VERSION 5.8 ;
BUSBITCHARS "[]" ;
DIVIDERCHAR "/" ;
UNITS
    DATABASE MICRONS 1000 ;
END UNITS

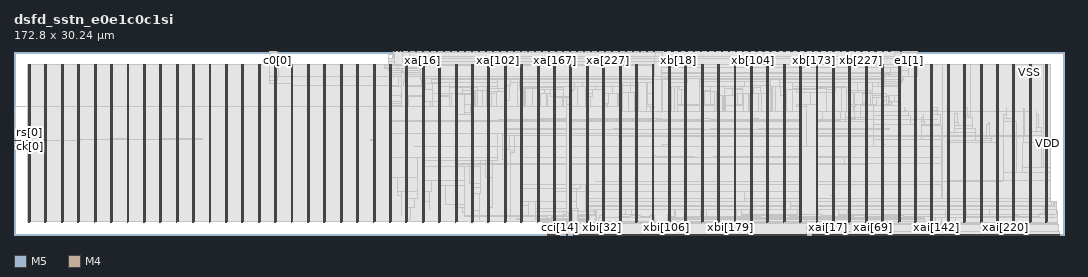
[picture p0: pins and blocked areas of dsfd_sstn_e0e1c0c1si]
MACRO dsfd_sstn_e0e1c0c1si
  FOREIGN dsfd_sstn_e0e1c0c1si 0 0 ;
  CLASS BLOCK ;
  SIZE 172.8 BY 30.24 ;
  PIN c0[0]
    DIRECTION INPUT ;
    USE SIGNAL ;
    PORT
      LAYER M5 ;
        RECT  43.296 30.156 43.32 30.24 ;
    END
  END c0[0]
  PIN c0[1]
    DIRECTION INPUT ;
    USE SIGNAL ;
    PORT
      LAYER M5 ;
        RECT  43.44 30.156 43.464 30.24 ;
    END
  END c0[1]
  PIN c1[0]
    DIRECTION INPUT ;
    USE SIGNAL ;
    PORT
      LAYER M5 ;
        RECT  148.464 30.156 148.488 30.24 ;
    END
  END c1[0]
  PIN c1[1]
    DIRECTION INPUT ;
    USE SIGNAL ;
    PORT
      LAYER M5 ;
        RECT  148.608 30.156 148.632 30.24 ;
    END
  END c1[1]
  PIN cc[0]
    DIRECTION OUTPUT ;
    USE SIGNAL ;
    PORT
      LAYER M5 ;
        RECT  62.592 30.156 62.616 30.24 ;
    END
  END cc[0]
  PIN cc[10]
    DIRECTION OUTPUT ;
    USE SIGNAL ;
    PORT
      LAYER M5 ;
        RECT  63.552 30.156 63.576 30.24 ;
    END
  END cc[10]
  PIN cc[11]
    DIRECTION OUTPUT ;
    USE SIGNAL ;
    PORT
      LAYER M5 ;
        RECT  63.648 30.156 63.672 30.24 ;
    END
  END cc[11]
  PIN cc[12]
    DIRECTION OUTPUT ;
    USE SIGNAL ;
    PORT
      LAYER M5 ;
        RECT  63.744 30.156 63.768 30.24 ;
    END
  END cc[12]
  PIN cc[13]
    DIRECTION OUTPUT ;
    USE SIGNAL ;
    PORT
      LAYER M5 ;
        RECT  63.84 30.156 63.864 30.24 ;
    END
  END cc[13]
  PIN cc[14]
    DIRECTION OUTPUT ;
    USE SIGNAL ;
    PORT
      LAYER M5 ;
        RECT  63.936 30.156 63.96 30.24 ;
    END
  END cc[14]
  PIN cc[1]
    DIRECTION OUTPUT ;
    USE SIGNAL ;
    PORT
      LAYER M5 ;
        RECT  62.688 30.156 62.712 30.24 ;
    END
  END cc[1]
  PIN cc[2]
    DIRECTION OUTPUT ;
    USE SIGNAL ;
    PORT
      LAYER M5 ;
        RECT  62.784 30.156 62.808 30.24 ;
    END
  END cc[2]
  PIN cc[3]
    DIRECTION OUTPUT ;
    USE SIGNAL ;
    PORT
      LAYER M5 ;
        RECT  62.88 30.156 62.904 30.24 ;
    END
  END cc[3]
  PIN cc[4]
    DIRECTION OUTPUT ;
    USE SIGNAL ;
    PORT
      LAYER M5 ;
        RECT  62.976 30.156 63 30.24 ;
    END
  END cc[4]
  PIN cc[5]
    DIRECTION OUTPUT ;
    USE SIGNAL ;
    PORT
      LAYER M5 ;
        RECT  63.072 30.156 63.096 30.24 ;
    END
  END cc[5]
  PIN cc[6]
    DIRECTION OUTPUT ;
    USE SIGNAL ;
    PORT
      LAYER M5 ;
        RECT  63.168 30.156 63.192 30.24 ;
    END
  END cc[6]
  PIN cc[7]
    DIRECTION OUTPUT ;
    USE SIGNAL ;
    PORT
      LAYER M5 ;
        RECT  63.264 30.156 63.288 30.24 ;
    END
  END cc[7]
  PIN cc[8]
    DIRECTION OUTPUT ;
    USE SIGNAL ;
    PORT
      LAYER M5 ;
        RECT  63.36 30.156 63.384 30.24 ;
    END
  END cc[8]
  PIN cc[9]
    DIRECTION OUTPUT ;
    USE SIGNAL ;
    PORT
      LAYER M5 ;
        RECT  63.456 30.156 63.48 30.24 ;
    END
  END cc[9]
  PIN cci[0]
    DIRECTION INPUT ;
    USE SIGNAL ;
    PORT
      LAYER M5 ;
        RECT  87.792 0 87.816 0.084 ;
    END
  END cci[0]
  PIN cci[10]
    DIRECTION INPUT ;
    USE SIGNAL ;
    PORT
      LAYER M5 ;
        RECT  89.232 0 89.256 0.084 ;
    END
  END cci[10]
  PIN cci[11]
    DIRECTION INPUT ;
    USE SIGNAL ;
    PORT
      LAYER M5 ;
        RECT  89.376 0 89.4 0.084 ;
    END
  END cci[11]
  PIN cci[12]
    DIRECTION INPUT ;
    USE SIGNAL ;
    PORT
      LAYER M5 ;
        RECT  89.52 0 89.544 0.084 ;
    END
  END cci[12]
  PIN cci[13]
    DIRECTION INPUT ;
    USE SIGNAL ;
    PORT
      LAYER M5 ;
        RECT  89.664 0 89.688 0.084 ;
    END
  END cci[13]
  PIN cci[14]
    DIRECTION INPUT ;
    USE SIGNAL ;
    PORT
      LAYER M5 ;
        RECT  89.808 0 89.832 0.084 ;
    END
  END cci[14]
  PIN cci[1]
    DIRECTION INPUT ;
    USE SIGNAL ;
    PORT
      LAYER M5 ;
        RECT  87.936 0 87.96 0.084 ;
    END
  END cci[1]
  PIN cci[2]
    DIRECTION INPUT ;
    USE SIGNAL ;
    PORT
      LAYER M5 ;
        RECT  88.08 0 88.104 0.084 ;
    END
  END cci[2]
  PIN cci[3]
    DIRECTION INPUT ;
    USE SIGNAL ;
    PORT
      LAYER M5 ;
        RECT  88.224 0 88.248 0.084 ;
    END
  END cci[3]
  PIN cci[4]
    DIRECTION INPUT ;
    USE SIGNAL ;
    PORT
      LAYER M5 ;
        RECT  88.368 0 88.392 0.084 ;
    END
  END cci[4]
  PIN cci[5]
    DIRECTION INPUT ;
    USE SIGNAL ;
    PORT
      LAYER M5 ;
        RECT  88.512 0 88.536 0.084 ;
    END
  END cci[5]
  PIN cci[6]
    DIRECTION INPUT ;
    USE SIGNAL ;
    PORT
      LAYER M5 ;
        RECT  88.656 0 88.68 0.084 ;
    END
  END cci[6]
  PIN cci[7]
    DIRECTION INPUT ;
    USE SIGNAL ;
    PORT
      LAYER M5 ;
        RECT  88.8 0 88.824 0.084 ;
    END
  END cci[7]
  PIN cci[8]
    DIRECTION INPUT ;
    USE SIGNAL ;
    PORT
      LAYER M5 ;
        RECT  88.944 0 88.968 0.084 ;
    END
  END cci[8]
  PIN cci[9]
    DIRECTION INPUT ;
    USE SIGNAL ;
    PORT
      LAYER M5 ;
        RECT  89.088 0 89.112 0.084 ;
    END
  END cci[9]
  PIN ck[0]
    DIRECTION INPUT ;
    USE SIGNAL ;
    PORT
      LAYER M4 ;
        RECT  0 14.592 0.084 14.616 ;
    END
    PORT
      LAYER M4 ;
        RECT  0.06 14.592 0.227 14.616 ;
    END
  END ck[0]
  PIN e0[0]
    DIRECTION INPUT ;
    USE SIGNAL ;
    PORT
      LAYER M5 ;
        RECT  42.048 30.156 42.072 30.24 ;
    END
  END e0[0]
  PIN e0[1]
    DIRECTION INPUT ;
    USE SIGNAL ;
    PORT
      LAYER M5 ;
        RECT  42.192 30.156 42.216 30.24 ;
    END
  END e0[1]
  PIN e1[0]
    DIRECTION INPUT ;
    USE SIGNAL ;
    PORT
      LAYER M5 ;
        RECT  147.216 30.156 147.24 30.24 ;
    END
  END e1[0]
  PIN e1[1]
    DIRECTION INPUT ;
    USE SIGNAL ;
    PORT
      LAYER M5 ;
        RECT  147.36 30.156 147.384 30.24 ;
    END
  END e1[1]
  PIN rs[0]
    DIRECTION INPUT ;
    USE SIGNAL ;
    PORT
      LAYER M4 ;
        RECT  0 15.6 0.084 15.624 ;
    END
    PORT
      LAYER M4 ;
        RECT  0.06 15.6 2.408 15.624 ;
    END
  END rs[0]
  PIN si[0]
    DIRECTION INPUT ;
    USE SIGNAL ;
    PORT
      LAYER M5 ;
        RECT  145.968 30.156 145.992 30.24 ;
    END
  END si[0]
  PIN si[1]
    DIRECTION INPUT ;
    USE SIGNAL ;
    PORT
      LAYER M5 ;
        RECT  146.112 30.156 146.136 30.24 ;
    END
  END si[1]
  PIN so[0]
    DIRECTION OUTPUT ;
    USE SIGNAL ;
    PORT
      LAYER M5 ;
        RECT  90.912 0 90.936 0.084 ;
    END
  END so[0]
  PIN so[1]
    DIRECTION OUTPUT ;
    USE SIGNAL ;
    PORT
      LAYER M5 ;
        RECT  91.056 0 91.08 0.084 ;
    END
  END so[1]
  PIN xa[0]
    DIRECTION OUTPUT ;
    USE SIGNAL ;
    PORT
      LAYER M5 ;
        RECT  64.992 30.156 65.016 30.24 ;
    END
  END xa[0]
  PIN xa[100]
    DIRECTION OUTPUT ;
    USE SIGNAL ;
    PORT
      LAYER M5 ;
        RECT  79.392 30.156 79.416 30.24 ;
    END
  END xa[100]
  PIN xa[101]
    DIRECTION OUTPUT ;
    USE SIGNAL ;
    PORT
      LAYER M5 ;
        RECT  79.536 30.156 79.56 30.24 ;
    END
  END xa[101]
  PIN xa[102]
    DIRECTION OUTPUT ;
    USE SIGNAL ;
    PORT
      LAYER M5 ;
        RECT  79.68 30.156 79.704 30.24 ;
    END
  END xa[102]
  PIN xa[103]
    DIRECTION OUTPUT ;
    USE SIGNAL ;
    PORT
      LAYER M5 ;
        RECT  79.824 30.156 79.848 30.24 ;
    END
  END xa[103]
  PIN xa[104]
    DIRECTION OUTPUT ;
    USE SIGNAL ;
    PORT
      LAYER M5 ;
        RECT  79.968 30.156 79.992 30.24 ;
    END
  END xa[104]
  PIN xa[105]
    DIRECTION OUTPUT ;
    USE SIGNAL ;
    PORT
      LAYER M5 ;
        RECT  80.112 30.156 80.136 30.24 ;
    END
  END xa[105]
  PIN xa[106]
    DIRECTION OUTPUT ;
    USE SIGNAL ;
    PORT
      LAYER M5 ;
        RECT  80.256 30.156 80.28 30.24 ;
    END
  END xa[106]
  PIN xa[107]
    DIRECTION OUTPUT ;
    USE SIGNAL ;
    PORT
      LAYER M5 ;
        RECT  80.4 30.156 80.424 30.24 ;
    END
  END xa[107]
  PIN xa[108]
    DIRECTION OUTPUT ;
    USE SIGNAL ;
    PORT
      LAYER M5 ;
        RECT  80.544 30.156 80.568 30.24 ;
    END
  END xa[108]
  PIN xa[109]
    DIRECTION OUTPUT ;
    USE SIGNAL ;
    PORT
      LAYER M5 ;
        RECT  80.688 30.156 80.712 30.24 ;
    END
  END xa[109]
  PIN xa[10]
    DIRECTION OUTPUT ;
    USE SIGNAL ;
    PORT
      LAYER M5 ;
        RECT  66.432 30.156 66.456 30.24 ;
    END
  END xa[10]
  PIN xa[110]
    DIRECTION OUTPUT ;
    USE SIGNAL ;
    PORT
      LAYER M5 ;
        RECT  80.832 30.156 80.856 30.24 ;
    END
  END xa[110]
  PIN xa[111]
    DIRECTION OUTPUT ;
    USE SIGNAL ;
    PORT
      LAYER M5 ;
        RECT  80.976 30.156 81 30.24 ;
    END
  END xa[111]
  PIN xa[112]
    DIRECTION OUTPUT ;
    USE SIGNAL ;
    PORT
      LAYER M5 ;
        RECT  81.12 30.156 81.144 30.24 ;
    END
  END xa[112]
  PIN xa[113]
    DIRECTION OUTPUT ;
    USE SIGNAL ;
    PORT
      LAYER M5 ;
        RECT  81.264 30.156 81.288 30.24 ;
    END
  END xa[113]
  PIN xa[114]
    DIRECTION OUTPUT ;
    USE SIGNAL ;
    PORT
      LAYER M5 ;
        RECT  81.408 30.156 81.432 30.24 ;
    END
  END xa[114]
  PIN xa[115]
    DIRECTION OUTPUT ;
    USE SIGNAL ;
    PORT
      LAYER M5 ;
        RECT  81.552 30.156 81.576 30.24 ;
    END
  END xa[115]
  PIN xa[116]
    DIRECTION OUTPUT ;
    USE SIGNAL ;
    PORT
      LAYER M5 ;
        RECT  81.696 30.156 81.72 30.24 ;
    END
  END xa[116]
  PIN xa[117]
    DIRECTION OUTPUT ;
    USE SIGNAL ;
    PORT
      LAYER M5 ;
        RECT  81.84 30.156 81.864 30.24 ;
    END
  END xa[117]
  PIN xa[118]
    DIRECTION OUTPUT ;
    USE SIGNAL ;
    PORT
      LAYER M5 ;
        RECT  81.984 30.156 82.008 30.24 ;
    END
  END xa[118]
  PIN xa[119]
    DIRECTION OUTPUT ;
    USE SIGNAL ;
    PORT
      LAYER M5 ;
        RECT  82.128 30.156 82.152 30.24 ;
    END
  END xa[119]
  PIN xa[11]
    DIRECTION OUTPUT ;
    USE SIGNAL ;
    PORT
      LAYER M5 ;
        RECT  66.576 30.156 66.6 30.24 ;
    END
  END xa[11]
  PIN xa[120]
    DIRECTION OUTPUT ;
    USE SIGNAL ;
    PORT
      LAYER M5 ;
        RECT  82.272 30.156 82.296 30.24 ;
    END
  END xa[120]
  PIN xa[121]
    DIRECTION OUTPUT ;
    USE SIGNAL ;
    PORT
      LAYER M5 ;
        RECT  82.416 30.156 82.44 30.24 ;
    END
  END xa[121]
  PIN xa[122]
    DIRECTION OUTPUT ;
    USE SIGNAL ;
    PORT
      LAYER M5 ;
        RECT  82.56 30.156 82.584 30.24 ;
    END
  END xa[122]
  PIN xa[123]
    DIRECTION OUTPUT ;
    USE SIGNAL ;
    PORT
      LAYER M5 ;
        RECT  82.704 30.156 82.728 30.24 ;
    END
  END xa[123]
  PIN xa[124]
    DIRECTION OUTPUT ;
    USE SIGNAL ;
    PORT
      LAYER M5 ;
        RECT  82.848 30.156 82.872 30.24 ;
    END
  END xa[124]
  PIN xa[125]
    DIRECTION OUTPUT ;
    USE SIGNAL ;
    PORT
      LAYER M5 ;
        RECT  82.992 30.156 83.016 30.24 ;
    END
  END xa[125]
  PIN xa[126]
    DIRECTION OUTPUT ;
    USE SIGNAL ;
    PORT
      LAYER M5 ;
        RECT  83.136 30.156 83.16 30.24 ;
    END
  END xa[126]
  PIN xa[127]
    DIRECTION OUTPUT ;
    USE SIGNAL ;
    PORT
      LAYER M5 ;
        RECT  83.28 30.156 83.304 30.24 ;
    END
  END xa[127]
  PIN xa[128]
    DIRECTION OUTPUT ;
    USE SIGNAL ;
    PORT
      LAYER M5 ;
        RECT  83.424 30.156 83.448 30.24 ;
    END
  END xa[128]
  PIN xa[129]
    DIRECTION OUTPUT ;
    USE SIGNAL ;
    PORT
      LAYER M5 ;
        RECT  83.568 30.156 83.592 30.24 ;
    END
  END xa[129]
  PIN xa[12]
    DIRECTION OUTPUT ;
    USE SIGNAL ;
    PORT
      LAYER M5 ;
        RECT  66.72 30.156 66.744 30.24 ;
    END
  END xa[12]
  PIN xa[130]
    DIRECTION OUTPUT ;
    USE SIGNAL ;
    PORT
      LAYER M5 ;
        RECT  83.712 30.156 83.736 30.24 ;
    END
  END xa[130]
  PIN xa[131]
    DIRECTION OUTPUT ;
    USE SIGNAL ;
    PORT
      LAYER M5 ;
        RECT  83.856 30.156 83.88 30.24 ;
    END
  END xa[131]
  PIN xa[132]
    DIRECTION OUTPUT ;
    USE SIGNAL ;
    PORT
      LAYER M5 ;
        RECT  84 30.156 84.024 30.24 ;
    END
  END xa[132]
  PIN xa[133]
    DIRECTION OUTPUT ;
    USE SIGNAL ;
    PORT
      LAYER M5 ;
        RECT  84.144 30.156 84.168 30.24 ;
    END
  END xa[133]
  PIN xa[134]
    DIRECTION OUTPUT ;
    USE SIGNAL ;
    PORT
      LAYER M5 ;
        RECT  84.288 30.156 84.312 30.24 ;
    END
  END xa[134]
  PIN xa[135]
    DIRECTION OUTPUT ;
    USE SIGNAL ;
    PORT
      LAYER M5 ;
        RECT  84.432 30.156 84.456 30.24 ;
    END
  END xa[135]
  PIN xa[136]
    DIRECTION OUTPUT ;
    USE SIGNAL ;
    PORT
      LAYER M5 ;
        RECT  84.576 30.156 84.6 30.24 ;
    END
  END xa[136]
  PIN xa[137]
    DIRECTION OUTPUT ;
    USE SIGNAL ;
    PORT
      LAYER M5 ;
        RECT  84.72 30.156 84.744 30.24 ;
    END
  END xa[137]
  PIN xa[138]
    DIRECTION OUTPUT ;
    USE SIGNAL ;
    PORT
      LAYER M5 ;
        RECT  84.864 30.156 84.888 30.24 ;
    END
  END xa[138]
  PIN xa[139]
    DIRECTION OUTPUT ;
    USE SIGNAL ;
    PORT
      LAYER M5 ;
        RECT  85.008 30.156 85.032 30.24 ;
    END
  END xa[139]
  PIN xa[13]
    DIRECTION OUTPUT ;
    USE SIGNAL ;
    PORT
      LAYER M5 ;
        RECT  66.864 30.156 66.888 30.24 ;
    END
  END xa[13]
  PIN xa[140]
    DIRECTION OUTPUT ;
    USE SIGNAL ;
    PORT
      LAYER M5 ;
        RECT  85.152 30.156 85.176 30.24 ;
    END
  END xa[140]
  PIN xa[141]
    DIRECTION OUTPUT ;
    USE SIGNAL ;
    PORT
      LAYER M5 ;
        RECT  85.296 30.156 85.32 30.24 ;
    END
  END xa[141]
  PIN xa[142]
    DIRECTION OUTPUT ;
    USE SIGNAL ;
    PORT
      LAYER M5 ;
        RECT  85.44 30.156 85.464 30.24 ;
    END
  END xa[142]
  PIN xa[143]
    DIRECTION OUTPUT ;
    USE SIGNAL ;
    PORT
      LAYER M5 ;
        RECT  85.584 30.156 85.608 30.24 ;
    END
  END xa[143]
  PIN xa[144]
    DIRECTION OUTPUT ;
    USE SIGNAL ;
    PORT
      LAYER M5 ;
        RECT  85.728 30.156 85.752 30.24 ;
    END
  END xa[144]
  PIN xa[145]
    DIRECTION OUTPUT ;
    USE SIGNAL ;
    PORT
      LAYER M5 ;
        RECT  85.872 30.156 85.896 30.24 ;
    END
  END xa[145]
  PIN xa[146]
    DIRECTION OUTPUT ;
    USE SIGNAL ;
    PORT
      LAYER M5 ;
        RECT  86.016 30.156 86.04 30.24 ;
    END
  END xa[146]
  PIN xa[147]
    DIRECTION OUTPUT ;
    USE SIGNAL ;
    PORT
      LAYER M5 ;
        RECT  86.16 30.156 86.184 30.24 ;
    END
  END xa[147]
  PIN xa[148]
    DIRECTION OUTPUT ;
    USE SIGNAL ;
    PORT
      LAYER M5 ;
        RECT  86.304 30.156 86.328 30.24 ;
    END
  END xa[148]
  PIN xa[149]
    DIRECTION OUTPUT ;
    USE SIGNAL ;
    PORT
      LAYER M5 ;
        RECT  86.448 30.156 86.472 30.24 ;
    END
  END xa[149]
  PIN xa[14]
    DIRECTION OUTPUT ;
    USE SIGNAL ;
    PORT
      LAYER M5 ;
        RECT  67.008 30.156 67.032 30.24 ;
    END
  END xa[14]
  PIN xa[150]
    DIRECTION OUTPUT ;
    USE SIGNAL ;
    PORT
      LAYER M5 ;
        RECT  86.592 30.156 86.616 30.24 ;
    END
  END xa[150]
  PIN xa[151]
    DIRECTION OUTPUT ;
    USE SIGNAL ;
    PORT
      LAYER M5 ;
        RECT  86.736 30.156 86.76 30.24 ;
    END
  END xa[151]
  PIN xa[152]
    DIRECTION OUTPUT ;
    USE SIGNAL ;
    PORT
      LAYER M5 ;
        RECT  86.88 30.156 86.904 30.24 ;
    END
  END xa[152]
  PIN xa[153]
    DIRECTION OUTPUT ;
    USE SIGNAL ;
    PORT
      LAYER M5 ;
        RECT  87.024 30.156 87.048 30.24 ;
    END
  END xa[153]
  PIN xa[154]
    DIRECTION OUTPUT ;
    USE SIGNAL ;
    PORT
      LAYER M5 ;
        RECT  87.168 30.156 87.192 30.24 ;
    END
  END xa[154]
  PIN xa[155]
    DIRECTION OUTPUT ;
    USE SIGNAL ;
    PORT
      LAYER M5 ;
        RECT  87.312 30.156 87.336 30.24 ;
    END
  END xa[155]
  PIN xa[156]
    DIRECTION OUTPUT ;
    USE SIGNAL ;
    PORT
      LAYER M5 ;
        RECT  87.456 30.156 87.48 30.24 ;
    END
  END xa[156]
  PIN xa[157]
    DIRECTION OUTPUT ;
    USE SIGNAL ;
    PORT
      LAYER M5 ;
        RECT  87.6 30.156 87.624 30.24 ;
    END
  END xa[157]
  PIN xa[158]
    DIRECTION OUTPUT ;
    USE SIGNAL ;
    PORT
      LAYER M5 ;
        RECT  87.744 30.156 87.768 30.24 ;
    END
  END xa[158]
  PIN xa[159]
    DIRECTION OUTPUT ;
    USE SIGNAL ;
    PORT
      LAYER M5 ;
        RECT  87.888 30.156 87.912 30.24 ;
    END
  END xa[159]
  PIN xa[15]
    DIRECTION OUTPUT ;
    USE SIGNAL ;
    PORT
      LAYER M5 ;
        RECT  67.152 30.156 67.176 30.24 ;
    END
  END xa[15]
  PIN xa[160]
    DIRECTION OUTPUT ;
    USE SIGNAL ;
    PORT
      LAYER M5 ;
        RECT  88.032 30.156 88.056 30.24 ;
    END
  END xa[160]
  PIN xa[161]
    DIRECTION OUTPUT ;
    USE SIGNAL ;
    PORT
      LAYER M5 ;
        RECT  88.176 30.156 88.2 30.24 ;
    END
  END xa[161]
  PIN xa[162]
    DIRECTION OUTPUT ;
    USE SIGNAL ;
    PORT
      LAYER M5 ;
        RECT  88.32 30.156 88.344 30.24 ;
    END
  END xa[162]
  PIN xa[163]
    DIRECTION OUTPUT ;
    USE SIGNAL ;
    PORT
      LAYER M5 ;
        RECT  88.464 30.156 88.488 30.24 ;
    END
  END xa[163]
  PIN xa[164]
    DIRECTION OUTPUT ;
    USE SIGNAL ;
    PORT
      LAYER M5 ;
        RECT  88.608 30.156 88.632 30.24 ;
    END
  END xa[164]
  PIN xa[165]
    DIRECTION OUTPUT ;
    USE SIGNAL ;
    PORT
      LAYER M5 ;
        RECT  88.752 30.156 88.776 30.24 ;
    END
  END xa[165]
  PIN xa[166]
    DIRECTION OUTPUT ;
    USE SIGNAL ;
    PORT
      LAYER M5 ;
        RECT  88.896 30.156 88.92 30.24 ;
    END
  END xa[166]
  PIN xa[167]
    DIRECTION OUTPUT ;
    USE SIGNAL ;
    PORT
      LAYER M5 ;
        RECT  89.04 30.156 89.064 30.24 ;
    END
  END xa[167]
  PIN xa[168]
    DIRECTION OUTPUT ;
    USE SIGNAL ;
    PORT
      LAYER M5 ;
        RECT  89.184 30.156 89.208 30.24 ;
    END
  END xa[168]
  PIN xa[169]
    DIRECTION OUTPUT ;
    USE SIGNAL ;
    PORT
      LAYER M5 ;
        RECT  89.328 30.156 89.352 30.24 ;
    END
  END xa[169]
  PIN xa[16]
    DIRECTION OUTPUT ;
    USE SIGNAL ;
    PORT
      LAYER M5 ;
        RECT  67.296 30.156 67.32 30.24 ;
    END
  END xa[16]
  PIN xa[170]
    DIRECTION OUTPUT ;
    USE SIGNAL ;
    PORT
      LAYER M5 ;
        RECT  89.472 30.156 89.496 30.24 ;
    END
  END xa[170]
  PIN xa[171]
    DIRECTION OUTPUT ;
    USE SIGNAL ;
    PORT
      LAYER M5 ;
        RECT  89.616 30.156 89.64 30.24 ;
    END
  END xa[171]
  PIN xa[172]
    DIRECTION OUTPUT ;
    USE SIGNAL ;
    PORT
      LAYER M5 ;
        RECT  89.76 30.156 89.784 30.24 ;
    END
  END xa[172]
  PIN xa[173]
    DIRECTION OUTPUT ;
    USE SIGNAL ;
    PORT
      LAYER M5 ;
        RECT  89.904 30.156 89.928 30.24 ;
    END
  END xa[173]
  PIN xa[174]
    DIRECTION OUTPUT ;
    USE SIGNAL ;
    PORT
      LAYER M5 ;
        RECT  90.048 30.156 90.072 30.24 ;
    END
  END xa[174]
  PIN xa[175]
    DIRECTION OUTPUT ;
    USE SIGNAL ;
    PORT
      LAYER M5 ;
        RECT  90.192 30.156 90.216 30.24 ;
    END
  END xa[175]
  PIN xa[176]
    DIRECTION OUTPUT ;
    USE SIGNAL ;
    PORT
      LAYER M5 ;
        RECT  90.336 30.156 90.36 30.24 ;
    END
  END xa[176]
  PIN xa[177]
    DIRECTION OUTPUT ;
    USE SIGNAL ;
    PORT
      LAYER M5 ;
        RECT  90.48 30.156 90.504 30.24 ;
    END
  END xa[177]
  PIN xa[178]
    DIRECTION OUTPUT ;
    USE SIGNAL ;
    PORT
      LAYER M5 ;
        RECT  90.624 30.156 90.648 30.24 ;
    END
  END xa[178]
  PIN xa[179]
    DIRECTION OUTPUT ;
    USE SIGNAL ;
    PORT
      LAYER M5 ;
        RECT  90.768 30.156 90.792 30.24 ;
    END
  END xa[179]
  PIN xa[17]
    DIRECTION OUTPUT ;
    USE SIGNAL ;
    PORT
      LAYER M5 ;
        RECT  67.44 30.156 67.464 30.24 ;
    END
  END xa[17]
  PIN xa[180]
    DIRECTION OUTPUT ;
    USE SIGNAL ;
    PORT
      LAYER M5 ;
        RECT  90.912 30.156 90.936 30.24 ;
    END
  END xa[180]
  PIN xa[181]
    DIRECTION OUTPUT ;
    USE SIGNAL ;
    PORT
      LAYER M5 ;
        RECT  91.056 30.156 91.08 30.24 ;
    END
  END xa[181]
  PIN xa[182]
    DIRECTION OUTPUT ;
    USE SIGNAL ;
    PORT
      LAYER M5 ;
        RECT  91.2 30.156 91.224 30.24 ;
    END
  END xa[182]
  PIN xa[183]
    DIRECTION OUTPUT ;
    USE SIGNAL ;
    PORT
      LAYER M5 ;
        RECT  91.344 30.156 91.368 30.24 ;
    END
  END xa[183]
  PIN xa[184]
    DIRECTION OUTPUT ;
    USE SIGNAL ;
    PORT
      LAYER M5 ;
        RECT  91.488 30.156 91.512 30.24 ;
    END
  END xa[184]
  PIN xa[185]
    DIRECTION OUTPUT ;
    USE SIGNAL ;
    PORT
      LAYER M5 ;
        RECT  91.632 30.156 91.656 30.24 ;
    END
  END xa[185]
  PIN xa[186]
    DIRECTION OUTPUT ;
    USE SIGNAL ;
    PORT
      LAYER M5 ;
        RECT  91.776 30.156 91.8 30.24 ;
    END
  END xa[186]
  PIN xa[187]
    DIRECTION OUTPUT ;
    USE SIGNAL ;
    PORT
      LAYER M5 ;
        RECT  91.92 30.156 91.944 30.24 ;
    END
  END xa[187]
  PIN xa[188]
    DIRECTION OUTPUT ;
    USE SIGNAL ;
    PORT
      LAYER M5 ;
        RECT  92.064 30.156 92.088 30.24 ;
    END
  END xa[188]
  PIN xa[189]
    DIRECTION OUTPUT ;
    USE SIGNAL ;
    PORT
      LAYER M5 ;
        RECT  92.208 30.156 92.232 30.24 ;
    END
  END xa[189]
  PIN xa[18]
    DIRECTION OUTPUT ;
    USE SIGNAL ;
    PORT
      LAYER M5 ;
        RECT  67.584 30.156 67.608 30.24 ;
    END
  END xa[18]
  PIN xa[190]
    DIRECTION OUTPUT ;
    USE SIGNAL ;
    PORT
      LAYER M5 ;
        RECT  92.352 30.156 92.376 30.24 ;
    END
  END xa[190]
  PIN xa[191]
    DIRECTION OUTPUT ;
    USE SIGNAL ;
    PORT
      LAYER M5 ;
        RECT  92.496 30.156 92.52 30.24 ;
    END
  END xa[191]
  PIN xa[192]
    DIRECTION OUTPUT ;
    USE SIGNAL ;
    PORT
      LAYER M5 ;
        RECT  92.64 30.156 92.664 30.24 ;
    END
  END xa[192]
  PIN xa[193]
    DIRECTION OUTPUT ;
    USE SIGNAL ;
    PORT
      LAYER M5 ;
        RECT  92.784 30.156 92.808 30.24 ;
    END
  END xa[193]
  PIN xa[194]
    DIRECTION OUTPUT ;
    USE SIGNAL ;
    PORT
      LAYER M5 ;
        RECT  92.928 30.156 92.952 30.24 ;
    END
  END xa[194]
  PIN xa[195]
    DIRECTION OUTPUT ;
    USE SIGNAL ;
    PORT
      LAYER M5 ;
        RECT  93.072 30.156 93.096 30.24 ;
    END
  END xa[195]
  PIN xa[196]
    DIRECTION OUTPUT ;
    USE SIGNAL ;
    PORT
      LAYER M5 ;
        RECT  93.216 30.156 93.24 30.24 ;
    END
  END xa[196]
  PIN xa[197]
    DIRECTION OUTPUT ;
    USE SIGNAL ;
    PORT
      LAYER M5 ;
        RECT  93.36 30.156 93.384 30.24 ;
    END
  END xa[197]
  PIN xa[198]
    DIRECTION OUTPUT ;
    USE SIGNAL ;
    PORT
      LAYER M5 ;
        RECT  93.504 30.156 93.528 30.24 ;
    END
  END xa[198]
  PIN xa[199]
    DIRECTION OUTPUT ;
    USE SIGNAL ;
    PORT
      LAYER M5 ;
        RECT  93.648 30.156 93.672 30.24 ;
    END
  END xa[199]
  PIN xa[19]
    DIRECTION OUTPUT ;
    USE SIGNAL ;
    PORT
      LAYER M5 ;
        RECT  67.728 30.156 67.752 30.24 ;
    END
  END xa[19]
  PIN xa[1]
    DIRECTION OUTPUT ;
    USE SIGNAL ;
    PORT
      LAYER M5 ;
        RECT  65.136 30.156 65.16 30.24 ;
    END
  END xa[1]
  PIN xa[200]
    DIRECTION OUTPUT ;
    USE SIGNAL ;
    PORT
      LAYER M5 ;
        RECT  93.792 30.156 93.816 30.24 ;
    END
  END xa[200]
  PIN xa[201]
    DIRECTION OUTPUT ;
    USE SIGNAL ;
    PORT
      LAYER M5 ;
        RECT  93.936 30.156 93.96 30.24 ;
    END
  END xa[201]
  PIN xa[202]
    DIRECTION OUTPUT ;
    USE SIGNAL ;
    PORT
      LAYER M5 ;
        RECT  94.08 30.156 94.104 30.24 ;
    END
  END xa[202]
  PIN xa[203]
    DIRECTION OUTPUT ;
    USE SIGNAL ;
    PORT
      LAYER M5 ;
        RECT  94.224 30.156 94.248 30.24 ;
    END
  END xa[203]
  PIN xa[204]
    DIRECTION OUTPUT ;
    USE SIGNAL ;
    PORT
      LAYER M5 ;
        RECT  94.368 30.156 94.392 30.24 ;
    END
  END xa[204]
  PIN xa[205]
    DIRECTION OUTPUT ;
    USE SIGNAL ;
    PORT
      LAYER M5 ;
        RECT  94.512 30.156 94.536 30.24 ;
    END
  END xa[205]
  PIN xa[206]
    DIRECTION OUTPUT ;
    USE SIGNAL ;
    PORT
      LAYER M5 ;
        RECT  94.656 30.156 94.68 30.24 ;
    END
  END xa[206]
  PIN xa[207]
    DIRECTION OUTPUT ;
    USE SIGNAL ;
    PORT
      LAYER M5 ;
        RECT  94.8 30.156 94.824 30.24 ;
    END
  END xa[207]
  PIN xa[208]
    DIRECTION OUTPUT ;
    USE SIGNAL ;
    PORT
      LAYER M5 ;
        RECT  94.944 30.156 94.968 30.24 ;
    END
  END xa[208]
  PIN xa[209]
    DIRECTION OUTPUT ;
    USE SIGNAL ;
    PORT
      LAYER M5 ;
        RECT  95.088 30.156 95.112 30.24 ;
    END
  END xa[209]
  PIN xa[20]
    DIRECTION OUTPUT ;
    USE SIGNAL ;
    PORT
      LAYER M5 ;
        RECT  67.872 30.156 67.896 30.24 ;
    END
  END xa[20]
  PIN xa[210]
    DIRECTION OUTPUT ;
    USE SIGNAL ;
    PORT
      LAYER M5 ;
        RECT  95.232 30.156 95.256 30.24 ;
    END
  END xa[210]
  PIN xa[211]
    DIRECTION OUTPUT ;
    USE SIGNAL ;
    PORT
      LAYER M5 ;
        RECT  95.376 30.156 95.4 30.24 ;
    END
  END xa[211]
  PIN xa[212]
    DIRECTION OUTPUT ;
    USE SIGNAL ;
    PORT
      LAYER M5 ;
        RECT  95.52 30.156 95.544 30.24 ;
    END
  END xa[212]
  PIN xa[213]
    DIRECTION OUTPUT ;
    USE SIGNAL ;
    PORT
      LAYER M5 ;
        RECT  95.664 30.156 95.688 30.24 ;
    END
  END xa[213]
  PIN xa[214]
    DIRECTION OUTPUT ;
    USE SIGNAL ;
    PORT
      LAYER M5 ;
        RECT  95.808 30.156 95.832 30.24 ;
    END
  END xa[214]
  PIN xa[215]
    DIRECTION OUTPUT ;
    USE SIGNAL ;
    PORT
      LAYER M5 ;
        RECT  95.952 30.156 95.976 30.24 ;
    END
  END xa[215]
  PIN xa[216]
    DIRECTION OUTPUT ;
    USE SIGNAL ;
    PORT
      LAYER M5 ;
        RECT  96.096 30.156 96.12 30.24 ;
    END
  END xa[216]
  PIN xa[217]
    DIRECTION OUTPUT ;
    USE SIGNAL ;
    PORT
      LAYER M5 ;
        RECT  96.24 30.156 96.264 30.24 ;
    END
  END xa[217]
  PIN xa[218]
    DIRECTION OUTPUT ;
    USE SIGNAL ;
    PORT
      LAYER M5 ;
        RECT  96.384 30.156 96.408 30.24 ;
    END
  END xa[218]
  PIN xa[219]
    DIRECTION OUTPUT ;
    USE SIGNAL ;
    PORT
      LAYER M5 ;
        RECT  96.528 30.156 96.552 30.24 ;
    END
  END xa[219]
  PIN xa[21]
    DIRECTION OUTPUT ;
    USE SIGNAL ;
    PORT
      LAYER M5 ;
        RECT  68.016 30.156 68.04 30.24 ;
    END
  END xa[21]
  PIN xa[220]
    DIRECTION OUTPUT ;
    USE SIGNAL ;
    PORT
      LAYER M5 ;
        RECT  96.672 30.156 96.696 30.24 ;
    END
  END xa[220]
  PIN xa[221]
    DIRECTION OUTPUT ;
    USE SIGNAL ;
    PORT
      LAYER M5 ;
        RECT  96.816 30.156 96.84 30.24 ;
    END
  END xa[221]
  PIN xa[222]
    DIRECTION OUTPUT ;
    USE SIGNAL ;
    PORT
      LAYER M5 ;
        RECT  96.96 30.156 96.984 30.24 ;
    END
  END xa[222]
  PIN xa[223]
    DIRECTION OUTPUT ;
    USE SIGNAL ;
    PORT
      LAYER M5 ;
        RECT  97.104 30.156 97.128 30.24 ;
    END
  END xa[223]
  PIN xa[224]
    DIRECTION OUTPUT ;
    USE SIGNAL ;
    PORT
      LAYER M5 ;
        RECT  97.248 30.156 97.272 30.24 ;
    END
  END xa[224]
  PIN xa[225]
    DIRECTION OUTPUT ;
    USE SIGNAL ;
    PORT
      LAYER M5 ;
        RECT  97.392 30.156 97.416 30.24 ;
    END
  END xa[225]
  PIN xa[226]
    DIRECTION OUTPUT ;
    USE SIGNAL ;
    PORT
      LAYER M5 ;
        RECT  97.536 30.156 97.56 30.24 ;
    END
  END xa[226]
  PIN xa[227]
    DIRECTION OUTPUT ;
    USE SIGNAL ;
    PORT
      LAYER M5 ;
        RECT  97.68 30.156 97.704 30.24 ;
    END
  END xa[227]
  PIN xa[228]
    DIRECTION OUTPUT ;
    USE SIGNAL ;
    PORT
      LAYER M5 ;
        RECT  97.824 30.156 97.848 30.24 ;
    END
  END xa[228]
  PIN xa[229]
    DIRECTION OUTPUT ;
    USE SIGNAL ;
    PORT
      LAYER M5 ;
        RECT  97.968 30.156 97.992 30.24 ;
    END
  END xa[229]
  PIN xa[22]
    DIRECTION OUTPUT ;
    USE SIGNAL ;
    PORT
      LAYER M5 ;
        RECT  68.16 30.156 68.184 30.24 ;
    END
  END xa[22]
  PIN xa[230]
    DIRECTION OUTPUT ;
    USE SIGNAL ;
    PORT
      LAYER M5 ;
        RECT  98.112 30.156 98.136 30.24 ;
    END
  END xa[230]
  PIN xa[231]
    DIRECTION OUTPUT ;
    USE SIGNAL ;
    PORT
      LAYER M5 ;
        RECT  98.256 30.156 98.28 30.24 ;
    END
  END xa[231]
  PIN xa[232]
    DIRECTION OUTPUT ;
    USE SIGNAL ;
    PORT
      LAYER M5 ;
        RECT  98.4 30.156 98.424 30.24 ;
    END
  END xa[232]
  PIN xa[233]
    DIRECTION OUTPUT ;
    USE SIGNAL ;
    PORT
      LAYER M5 ;
        RECT  98.544 30.156 98.568 30.24 ;
    END
  END xa[233]
  PIN xa[234]
    DIRECTION OUTPUT ;
    USE SIGNAL ;
    PORT
      LAYER M5 ;
        RECT  98.688 30.156 98.712 30.24 ;
    END
  END xa[234]
  PIN xa[235]
    DIRECTION OUTPUT ;
    USE SIGNAL ;
    PORT
      LAYER M5 ;
        RECT  98.832 30.156 98.856 30.24 ;
    END
  END xa[235]
  PIN xa[236]
    DIRECTION OUTPUT ;
    USE SIGNAL ;
    PORT
      LAYER M5 ;
        RECT  98.976 30.156 99 30.24 ;
    END
  END xa[236]
  PIN xa[237]
    DIRECTION OUTPUT ;
    USE SIGNAL ;
    PORT
      LAYER M5 ;
        RECT  99.12 30.156 99.144 30.24 ;
    END
  END xa[237]
  PIN xa[238]
    DIRECTION OUTPUT ;
    USE SIGNAL ;
    PORT
      LAYER M5 ;
        RECT  99.264 30.156 99.288 30.24 ;
    END
  END xa[238]
  PIN xa[239]
    DIRECTION OUTPUT ;
    USE SIGNAL ;
    PORT
      LAYER M5 ;
        RECT  99.408 30.156 99.432 30.24 ;
    END
  END xa[239]
  PIN xa[23]
    DIRECTION OUTPUT ;
    USE SIGNAL ;
    PORT
      LAYER M5 ;
        RECT  68.304 30.156 68.328 30.24 ;
    END
  END xa[23]
  PIN xa[240]
    DIRECTION OUTPUT ;
    USE SIGNAL ;
    PORT
      LAYER M5 ;
        RECT  99.552 30.156 99.576 30.24 ;
    END
  END xa[240]
  PIN xa[241]
    DIRECTION OUTPUT ;
    USE SIGNAL ;
    PORT
      LAYER M5 ;
        RECT  99.696 30.156 99.72 30.24 ;
    END
  END xa[241]
  PIN xa[242]
    DIRECTION OUTPUT ;
    USE SIGNAL ;
    PORT
      LAYER M5 ;
        RECT  99.84 30.156 99.864 30.24 ;
    END
  END xa[242]
  PIN xa[243]
    DIRECTION OUTPUT ;
    USE SIGNAL ;
    PORT
      LAYER M5 ;
        RECT  99.984 30.156 100.008 30.24 ;
    END
  END xa[243]
  PIN xa[244]
    DIRECTION OUTPUT ;
    USE SIGNAL ;
    PORT
      LAYER M5 ;
        RECT  100.128 30.156 100.152 30.24 ;
    END
  END xa[244]
  PIN xa[245]
    DIRECTION OUTPUT ;
    USE SIGNAL ;
    PORT
      LAYER M5 ;
        RECT  100.272 30.156 100.296 30.24 ;
    END
  END xa[245]
  PIN xa[246]
    DIRECTION OUTPUT ;
    USE SIGNAL ;
    PORT
      LAYER M5 ;
        RECT  100.416 30.156 100.44 30.24 ;
    END
  END xa[246]
  PIN xa[247]
    DIRECTION OUTPUT ;
    USE SIGNAL ;
    PORT
      LAYER M5 ;
        RECT  100.56 30.156 100.584 30.24 ;
    END
  END xa[247]
  PIN xa[248]
    DIRECTION OUTPUT ;
    USE SIGNAL ;
    PORT
      LAYER M5 ;
        RECT  100.704 30.156 100.728 30.24 ;
    END
  END xa[248]
  PIN xa[249]
    DIRECTION OUTPUT ;
    USE SIGNAL ;
    PORT
      LAYER M5 ;
        RECT  100.848 30.156 100.872 30.24 ;
    END
  END xa[249]
  PIN xa[24]
    DIRECTION OUTPUT ;
    USE SIGNAL ;
    PORT
      LAYER M5 ;
        RECT  68.448 30.156 68.472 30.24 ;
    END
  END xa[24]
  PIN xa[250]
    DIRECTION OUTPUT ;
    USE SIGNAL ;
    PORT
      LAYER M5 ;
        RECT  100.992 30.156 101.016 30.24 ;
    END
  END xa[250]
  PIN xa[251]
    DIRECTION OUTPUT ;
    USE SIGNAL ;
    PORT
      LAYER M5 ;
        RECT  101.136 30.156 101.16 30.24 ;
    END
  END xa[251]
  PIN xa[252]
    DIRECTION OUTPUT ;
    USE SIGNAL ;
    PORT
      LAYER M5 ;
        RECT  101.28 30.156 101.304 30.24 ;
    END
  END xa[252]
  PIN xa[253]
    DIRECTION OUTPUT ;
    USE SIGNAL ;
    PORT
      LAYER M5 ;
        RECT  101.424 30.156 101.448 30.24 ;
    END
  END xa[253]
  PIN xa[254]
    DIRECTION OUTPUT ;
    USE SIGNAL ;
    PORT
      LAYER M5 ;
        RECT  101.568 30.156 101.592 30.24 ;
    END
  END xa[254]
  PIN xa[255]
    DIRECTION OUTPUT ;
    USE SIGNAL ;
    PORT
      LAYER M5 ;
        RECT  101.712 30.156 101.736 30.24 ;
    END
  END xa[255]
  PIN xa[256]
    DIRECTION OUTPUT ;
    USE SIGNAL ;
    PORT
      LAYER M5 ;
        RECT  101.856 30.156 101.88 30.24 ;
    END
  END xa[256]
  PIN xa[257]
    DIRECTION OUTPUT ;
    USE SIGNAL ;
    PORT
      LAYER M5 ;
        RECT  102 30.156 102.024 30.24 ;
    END
  END xa[257]
  PIN xa[258]
    DIRECTION OUTPUT ;
    USE SIGNAL ;
    PORT
      LAYER M5 ;
        RECT  102.144 30.156 102.168 30.24 ;
    END
  END xa[258]
  PIN xa[259]
    DIRECTION OUTPUT ;
    USE SIGNAL ;
    PORT
      LAYER M5 ;
        RECT  102.288 30.156 102.312 30.24 ;
    END
  END xa[259]
  PIN xa[25]
    DIRECTION OUTPUT ;
    USE SIGNAL ;
    PORT
      LAYER M5 ;
        RECT  68.592 30.156 68.616 30.24 ;
    END
  END xa[25]
  PIN xa[260]
    DIRECTION OUTPUT ;
    USE SIGNAL ;
    PORT
      LAYER M5 ;
        RECT  102.432 30.156 102.456 30.24 ;
    END
  END xa[260]
  PIN xa[261]
    DIRECTION OUTPUT ;
    USE SIGNAL ;
    PORT
      LAYER M5 ;
        RECT  102.576 30.156 102.6 30.24 ;
    END
  END xa[261]
  PIN xa[262]
    DIRECTION OUTPUT ;
    USE SIGNAL ;
    PORT
      LAYER M5 ;
        RECT  102.72 30.156 102.744 30.24 ;
    END
  END xa[262]
  PIN xa[263]
    DIRECTION OUTPUT ;
    USE SIGNAL ;
    PORT
      LAYER M5 ;
        RECT  102.864 30.156 102.888 30.24 ;
    END
  END xa[263]
  PIN xa[264]
    DIRECTION OUTPUT ;
    USE SIGNAL ;
    PORT
      LAYER M5 ;
        RECT  103.008 30.156 103.032 30.24 ;
    END
  END xa[264]
  PIN xa[265]
    DIRECTION OUTPUT ;
    USE SIGNAL ;
    PORT
      LAYER M5 ;
        RECT  103.152 30.156 103.176 30.24 ;
    END
  END xa[265]
  PIN xa[266]
    DIRECTION OUTPUT ;
    USE SIGNAL ;
    PORT
      LAYER M5 ;
        RECT  103.296 30.156 103.32 30.24 ;
    END
  END xa[266]
  PIN xa[267]
    DIRECTION OUTPUT ;
    USE SIGNAL ;
    PORT
      LAYER M5 ;
        RECT  103.44 30.156 103.464 30.24 ;
    END
  END xa[267]
  PIN xa[268]
    DIRECTION OUTPUT ;
    USE SIGNAL ;
    PORT
      LAYER M5 ;
        RECT  103.584 30.156 103.608 30.24 ;
    END
  END xa[268]
  PIN xa[269]
    DIRECTION OUTPUT ;
    USE SIGNAL ;
    PORT
      LAYER M5 ;
        RECT  103.728 30.156 103.752 30.24 ;
    END
  END xa[269]
  PIN xa[26]
    DIRECTION OUTPUT ;
    USE SIGNAL ;
    PORT
      LAYER M5 ;
        RECT  68.736 30.156 68.76 30.24 ;
    END
  END xa[26]
  PIN xa[270]
    DIRECTION OUTPUT ;
    USE SIGNAL ;
    PORT
      LAYER M5 ;
        RECT  103.872 30.156 103.896 30.24 ;
    END
  END xa[270]
  PIN xa[271]
    DIRECTION OUTPUT ;
    USE SIGNAL ;
    PORT
      LAYER M5 ;
        RECT  104.016 30.156 104.04 30.24 ;
    END
  END xa[271]
  PIN xa[272]
    DIRECTION OUTPUT ;
    USE SIGNAL ;
    PORT
      LAYER M5 ;
        RECT  104.16 30.156 104.184 30.24 ;
    END
  END xa[272]
  PIN xa[273]
    DIRECTION OUTPUT ;
    USE SIGNAL ;
    PORT
      LAYER M5 ;
        RECT  104.304 30.156 104.328 30.24 ;
    END
  END xa[273]
  PIN xa[274]
    DIRECTION OUTPUT ;
    USE SIGNAL ;
    PORT
      LAYER M5 ;
        RECT  104.448 30.156 104.472 30.24 ;
    END
  END xa[274]
  PIN xa[275]
    DIRECTION OUTPUT ;
    USE SIGNAL ;
    PORT
      LAYER M5 ;
        RECT  104.592 30.156 104.616 30.24 ;
    END
  END xa[275]
  PIN xa[276]
    DIRECTION OUTPUT ;
    USE SIGNAL ;
    PORT
      LAYER M5 ;
        RECT  104.736 30.156 104.76 30.24 ;
    END
  END xa[276]
  PIN xa[277]
    DIRECTION OUTPUT ;
    USE SIGNAL ;
    PORT
      LAYER M5 ;
        RECT  104.88 30.156 104.904 30.24 ;
    END
  END xa[277]
  PIN xa[278]
    DIRECTION OUTPUT ;
    USE SIGNAL ;
    PORT
      LAYER M5 ;
        RECT  105.024 30.156 105.048 30.24 ;
    END
  END xa[278]
  PIN xa[279]
    DIRECTION OUTPUT ;
    USE SIGNAL ;
    PORT
      LAYER M5 ;
        RECT  105.168 30.156 105.192 30.24 ;
    END
  END xa[279]
  PIN xa[27]
    DIRECTION OUTPUT ;
    USE SIGNAL ;
    PORT
      LAYER M5 ;
        RECT  68.88 30.156 68.904 30.24 ;
    END
  END xa[27]
  PIN xa[280]
    DIRECTION OUTPUT ;
    USE SIGNAL ;
    PORT
      LAYER M5 ;
        RECT  105.312 30.156 105.336 30.24 ;
    END
  END xa[280]
  PIN xa[281]
    DIRECTION OUTPUT ;
    USE SIGNAL ;
    PORT
      LAYER M5 ;
        RECT  105.456 30.156 105.48 30.24 ;
    END
  END xa[281]
  PIN xa[282]
    DIRECTION OUTPUT ;
    USE SIGNAL ;
    PORT
      LAYER M5 ;
        RECT  105.6 30.156 105.624 30.24 ;
    END
  END xa[282]
  PIN xa[28]
    DIRECTION OUTPUT ;
    USE SIGNAL ;
    PORT
      LAYER M5 ;
        RECT  69.024 30.156 69.048 30.24 ;
    END
  END xa[28]
  PIN xa[29]
    DIRECTION OUTPUT ;
    USE SIGNAL ;
    PORT
      LAYER M5 ;
        RECT  69.168 30.156 69.192 30.24 ;
    END
  END xa[29]
  PIN xa[2]
    DIRECTION OUTPUT ;
    USE SIGNAL ;
    PORT
      LAYER M5 ;
        RECT  65.28 30.156 65.304 30.24 ;
    END
  END xa[2]
  PIN xa[30]
    DIRECTION OUTPUT ;
    USE SIGNAL ;
    PORT
      LAYER M5 ;
        RECT  69.312 30.156 69.336 30.24 ;
    END
  END xa[30]
  PIN xa[31]
    DIRECTION OUTPUT ;
    USE SIGNAL ;
    PORT
      LAYER M5 ;
        RECT  69.456 30.156 69.48 30.24 ;
    END
  END xa[31]
  PIN xa[32]
    DIRECTION OUTPUT ;
    USE SIGNAL ;
    PORT
      LAYER M5 ;
        RECT  69.6 30.156 69.624 30.24 ;
    END
  END xa[32]
  PIN xa[33]
    DIRECTION OUTPUT ;
    USE SIGNAL ;
    PORT
      LAYER M5 ;
        RECT  69.744 30.156 69.768 30.24 ;
    END
  END xa[33]
  PIN xa[34]
    DIRECTION OUTPUT ;
    USE SIGNAL ;
    PORT
      LAYER M5 ;
        RECT  69.888 30.156 69.912 30.24 ;
    END
  END xa[34]
  PIN xa[35]
    DIRECTION OUTPUT ;
    USE SIGNAL ;
    PORT
      LAYER M5 ;
        RECT  70.032 30.156 70.056 30.24 ;
    END
  END xa[35]
  PIN xa[36]
    DIRECTION OUTPUT ;
    USE SIGNAL ;
    PORT
      LAYER M5 ;
        RECT  70.176 30.156 70.2 30.24 ;
    END
  END xa[36]
  PIN xa[37]
    DIRECTION OUTPUT ;
    USE SIGNAL ;
    PORT
      LAYER M5 ;
        RECT  70.32 30.156 70.344 30.24 ;
    END
  END xa[37]
  PIN xa[38]
    DIRECTION OUTPUT ;
    USE SIGNAL ;
    PORT
      LAYER M5 ;
        RECT  70.464 30.156 70.488 30.24 ;
    END
  END xa[38]
  PIN xa[39]
    DIRECTION OUTPUT ;
    USE SIGNAL ;
    PORT
      LAYER M5 ;
        RECT  70.608 30.156 70.632 30.24 ;
    END
  END xa[39]
  PIN xa[3]
    DIRECTION OUTPUT ;
    USE SIGNAL ;
    PORT
      LAYER M5 ;
        RECT  65.424 30.156 65.448 30.24 ;
    END
  END xa[3]
  PIN xa[40]
    DIRECTION OUTPUT ;
    USE SIGNAL ;
    PORT
      LAYER M5 ;
        RECT  70.752 30.156 70.776 30.24 ;
    END
  END xa[40]
  PIN xa[41]
    DIRECTION OUTPUT ;
    USE SIGNAL ;
    PORT
      LAYER M5 ;
        RECT  70.896 30.156 70.92 30.24 ;
    END
  END xa[41]
  PIN xa[42]
    DIRECTION OUTPUT ;
    USE SIGNAL ;
    PORT
      LAYER M5 ;
        RECT  71.04 30.156 71.064 30.24 ;
    END
  END xa[42]
  PIN xa[43]
    DIRECTION OUTPUT ;
    USE SIGNAL ;
    PORT
      LAYER M5 ;
        RECT  71.184 30.156 71.208 30.24 ;
    END
  END xa[43]
  PIN xa[44]
    DIRECTION OUTPUT ;
    USE SIGNAL ;
    PORT
      LAYER M5 ;
        RECT  71.328 30.156 71.352 30.24 ;
    END
  END xa[44]
  PIN xa[45]
    DIRECTION OUTPUT ;
    USE SIGNAL ;
    PORT
      LAYER M5 ;
        RECT  71.472 30.156 71.496 30.24 ;
    END
  END xa[45]
  PIN xa[46]
    DIRECTION OUTPUT ;
    USE SIGNAL ;
    PORT
      LAYER M5 ;
        RECT  71.616 30.156 71.64 30.24 ;
    END
  END xa[46]
  PIN xa[47]
    DIRECTION OUTPUT ;
    USE SIGNAL ;
    PORT
      LAYER M5 ;
        RECT  71.76 30.156 71.784 30.24 ;
    END
  END xa[47]
  PIN xa[48]
    DIRECTION OUTPUT ;
    USE SIGNAL ;
    PORT
      LAYER M5 ;
        RECT  71.904 30.156 71.928 30.24 ;
    END
  END xa[48]
  PIN xa[49]
    DIRECTION OUTPUT ;
    USE SIGNAL ;
    PORT
      LAYER M5 ;
        RECT  72.048 30.156 72.072 30.24 ;
    END
  END xa[49]
  PIN xa[4]
    DIRECTION OUTPUT ;
    USE SIGNAL ;
    PORT
      LAYER M5 ;
        RECT  65.568 30.156 65.592 30.24 ;
    END
  END xa[4]
  PIN xa[50]
    DIRECTION OUTPUT ;
    USE SIGNAL ;
    PORT
      LAYER M5 ;
        RECT  72.192 30.156 72.216 30.24 ;
    END
  END xa[50]
  PIN xa[51]
    DIRECTION OUTPUT ;
    USE SIGNAL ;
    PORT
      LAYER M5 ;
        RECT  72.336 30.156 72.36 30.24 ;
    END
  END xa[51]
  PIN xa[52]
    DIRECTION OUTPUT ;
    USE SIGNAL ;
    PORT
      LAYER M5 ;
        RECT  72.48 30.156 72.504 30.24 ;
    END
  END xa[52]
  PIN xa[53]
    DIRECTION OUTPUT ;
    USE SIGNAL ;
    PORT
      LAYER M5 ;
        RECT  72.624 30.156 72.648 30.24 ;
    END
  END xa[53]
  PIN xa[54]
    DIRECTION OUTPUT ;
    USE SIGNAL ;
    PORT
      LAYER M5 ;
        RECT  72.768 30.156 72.792 30.24 ;
    END
  END xa[54]
  PIN xa[55]
    DIRECTION OUTPUT ;
    USE SIGNAL ;
    PORT
      LAYER M5 ;
        RECT  72.912 30.156 72.936 30.24 ;
    END
  END xa[55]
  PIN xa[56]
    DIRECTION OUTPUT ;
    USE SIGNAL ;
    PORT
      LAYER M5 ;
        RECT  73.056 30.156 73.08 30.24 ;
    END
  END xa[56]
  PIN xa[57]
    DIRECTION OUTPUT ;
    USE SIGNAL ;
    PORT
      LAYER M5 ;
        RECT  73.2 30.156 73.224 30.24 ;
    END
  END xa[57]
  PIN xa[58]
    DIRECTION OUTPUT ;
    USE SIGNAL ;
    PORT
      LAYER M5 ;
        RECT  73.344 30.156 73.368 30.24 ;
    END
  END xa[58]
  PIN xa[59]
    DIRECTION OUTPUT ;
    USE SIGNAL ;
    PORT
      LAYER M5 ;
        RECT  73.488 30.156 73.512 30.24 ;
    END
  END xa[59]
  PIN xa[5]
    DIRECTION OUTPUT ;
    USE SIGNAL ;
    PORT
      LAYER M5 ;
        RECT  65.712 30.156 65.736 30.24 ;
    END
  END xa[5]
  PIN xa[60]
    DIRECTION OUTPUT ;
    USE SIGNAL ;
    PORT
      LAYER M5 ;
        RECT  73.632 30.156 73.656 30.24 ;
    END
  END xa[60]
  PIN xa[61]
    DIRECTION OUTPUT ;
    USE SIGNAL ;
    PORT
      LAYER M5 ;
        RECT  73.776 30.156 73.8 30.24 ;
    END
  END xa[61]
  PIN xa[62]
    DIRECTION OUTPUT ;
    USE SIGNAL ;
    PORT
      LAYER M5 ;
        RECT  73.92 30.156 73.944 30.24 ;
    END
  END xa[62]
  PIN xa[63]
    DIRECTION OUTPUT ;
    USE SIGNAL ;
    PORT
      LAYER M5 ;
        RECT  74.064 30.156 74.088 30.24 ;
    END
  END xa[63]
  PIN xa[64]
    DIRECTION OUTPUT ;
    USE SIGNAL ;
    PORT
      LAYER M5 ;
        RECT  74.208 30.156 74.232 30.24 ;
    END
  END xa[64]
  PIN xa[65]
    DIRECTION OUTPUT ;
    USE SIGNAL ;
    PORT
      LAYER M5 ;
        RECT  74.352 30.156 74.376 30.24 ;
    END
  END xa[65]
  PIN xa[66]
    DIRECTION OUTPUT ;
    USE SIGNAL ;
    PORT
      LAYER M5 ;
        RECT  74.496 30.156 74.52 30.24 ;
    END
  END xa[66]
  PIN xa[67]
    DIRECTION OUTPUT ;
    USE SIGNAL ;
    PORT
      LAYER M5 ;
        RECT  74.64 30.156 74.664 30.24 ;
    END
  END xa[67]
  PIN xa[68]
    DIRECTION OUTPUT ;
    USE SIGNAL ;
    PORT
      LAYER M5 ;
        RECT  74.784 30.156 74.808 30.24 ;
    END
  END xa[68]
  PIN xa[69]
    DIRECTION OUTPUT ;
    USE SIGNAL ;
    PORT
      LAYER M5 ;
        RECT  74.928 30.156 74.952 30.24 ;
    END
  END xa[69]
  PIN xa[6]
    DIRECTION OUTPUT ;
    USE SIGNAL ;
    PORT
      LAYER M5 ;
        RECT  65.856 30.156 65.88 30.24 ;
    END
  END xa[6]
  PIN xa[70]
    DIRECTION OUTPUT ;
    USE SIGNAL ;
    PORT
      LAYER M5 ;
        RECT  75.072 30.156 75.096 30.24 ;
    END
  END xa[70]
  PIN xa[71]
    DIRECTION OUTPUT ;
    USE SIGNAL ;
    PORT
      LAYER M5 ;
        RECT  75.216 30.156 75.24 30.24 ;
    END
  END xa[71]
  PIN xa[72]
    DIRECTION OUTPUT ;
    USE SIGNAL ;
    PORT
      LAYER M5 ;
        RECT  75.36 30.156 75.384 30.24 ;
    END
  END xa[72]
  PIN xa[73]
    DIRECTION OUTPUT ;
    USE SIGNAL ;
    PORT
      LAYER M5 ;
        RECT  75.504 30.156 75.528 30.24 ;
    END
  END xa[73]
  PIN xa[74]
    DIRECTION OUTPUT ;
    USE SIGNAL ;
    PORT
      LAYER M5 ;
        RECT  75.648 30.156 75.672 30.24 ;
    END
  END xa[74]
  PIN xa[75]
    DIRECTION OUTPUT ;
    USE SIGNAL ;
    PORT
      LAYER M5 ;
        RECT  75.792 30.156 75.816 30.24 ;
    END
  END xa[75]
  PIN xa[76]
    DIRECTION OUTPUT ;
    USE SIGNAL ;
    PORT
      LAYER M5 ;
        RECT  75.936 30.156 75.96 30.24 ;
    END
  END xa[76]
  PIN xa[77]
    DIRECTION OUTPUT ;
    USE SIGNAL ;
    PORT
      LAYER M5 ;
        RECT  76.08 30.156 76.104 30.24 ;
    END
  END xa[77]
  PIN xa[78]
    DIRECTION OUTPUT ;
    USE SIGNAL ;
    PORT
      LAYER M5 ;
        RECT  76.224 30.156 76.248 30.24 ;
    END
  END xa[78]
  PIN xa[79]
    DIRECTION OUTPUT ;
    USE SIGNAL ;
    PORT
      LAYER M5 ;
        RECT  76.368 30.156 76.392 30.24 ;
    END
  END xa[79]
  PIN xa[7]
    DIRECTION OUTPUT ;
    USE SIGNAL ;
    PORT
      LAYER M5 ;
        RECT  66 30.156 66.024 30.24 ;
    END
  END xa[7]
  PIN xa[80]
    DIRECTION OUTPUT ;
    USE SIGNAL ;
    PORT
      LAYER M5 ;
        RECT  76.512 30.156 76.536 30.24 ;
    END
  END xa[80]
  PIN xa[81]
    DIRECTION OUTPUT ;
    USE SIGNAL ;
    PORT
      LAYER M5 ;
        RECT  76.656 30.156 76.68 30.24 ;
    END
  END xa[81]
  PIN xa[82]
    DIRECTION OUTPUT ;
    USE SIGNAL ;
    PORT
      LAYER M5 ;
        RECT  76.8 30.156 76.824 30.24 ;
    END
  END xa[82]
  PIN xa[83]
    DIRECTION OUTPUT ;
    USE SIGNAL ;
    PORT
      LAYER M5 ;
        RECT  76.944 30.156 76.968 30.24 ;
    END
  END xa[83]
  PIN xa[84]
    DIRECTION OUTPUT ;
    USE SIGNAL ;
    PORT
      LAYER M5 ;
        RECT  77.088 30.156 77.112 30.24 ;
    END
  END xa[84]
  PIN xa[85]
    DIRECTION OUTPUT ;
    USE SIGNAL ;
    PORT
      LAYER M5 ;
        RECT  77.232 30.156 77.256 30.24 ;
    END
  END xa[85]
  PIN xa[86]
    DIRECTION OUTPUT ;
    USE SIGNAL ;
    PORT
      LAYER M5 ;
        RECT  77.376 30.156 77.4 30.24 ;
    END
  END xa[86]
  PIN xa[87]
    DIRECTION OUTPUT ;
    USE SIGNAL ;
    PORT
      LAYER M5 ;
        RECT  77.52 30.156 77.544 30.24 ;
    END
  END xa[87]
  PIN xa[88]
    DIRECTION OUTPUT ;
    USE SIGNAL ;
    PORT
      LAYER M5 ;
        RECT  77.664 30.156 77.688 30.24 ;
    END
  END xa[88]
  PIN xa[89]
    DIRECTION OUTPUT ;
    USE SIGNAL ;
    PORT
      LAYER M5 ;
        RECT  77.808 30.156 77.832 30.24 ;
    END
  END xa[89]
  PIN xa[8]
    DIRECTION OUTPUT ;
    USE SIGNAL ;
    PORT
      LAYER M5 ;
        RECT  66.144 30.156 66.168 30.24 ;
    END
  END xa[8]
  PIN xa[90]
    DIRECTION OUTPUT ;
    USE SIGNAL ;
    PORT
      LAYER M5 ;
        RECT  77.952 30.156 77.976 30.24 ;
    END
  END xa[90]
  PIN xa[91]
    DIRECTION OUTPUT ;
    USE SIGNAL ;
    PORT
      LAYER M5 ;
        RECT  78.096 30.156 78.12 30.24 ;
    END
  END xa[91]
  PIN xa[92]
    DIRECTION OUTPUT ;
    USE SIGNAL ;
    PORT
      LAYER M5 ;
        RECT  78.24 30.156 78.264 30.24 ;
    END
  END xa[92]
  PIN xa[93]
    DIRECTION OUTPUT ;
    USE SIGNAL ;
    PORT
      LAYER M5 ;
        RECT  78.384 30.156 78.408 30.24 ;
    END
  END xa[93]
  PIN xa[94]
    DIRECTION OUTPUT ;
    USE SIGNAL ;
    PORT
      LAYER M5 ;
        RECT  78.528 30.156 78.552 30.24 ;
    END
  END xa[94]
  PIN xa[95]
    DIRECTION OUTPUT ;
    USE SIGNAL ;
    PORT
      LAYER M5 ;
        RECT  78.672 30.156 78.696 30.24 ;
    END
  END xa[95]
  PIN xa[96]
    DIRECTION OUTPUT ;
    USE SIGNAL ;
    PORT
      LAYER M5 ;
        RECT  78.816 30.156 78.84 30.24 ;
    END
  END xa[96]
  PIN xa[97]
    DIRECTION OUTPUT ;
    USE SIGNAL ;
    PORT
      LAYER M5 ;
        RECT  78.96 30.156 78.984 30.24 ;
    END
  END xa[97]
  PIN xa[98]
    DIRECTION OUTPUT ;
    USE SIGNAL ;
    PORT
      LAYER M5 ;
        RECT  79.104 30.156 79.128 30.24 ;
    END
  END xa[98]
  PIN xa[99]
    DIRECTION OUTPUT ;
    USE SIGNAL ;
    PORT
      LAYER M5 ;
        RECT  79.248 30.156 79.272 30.24 ;
    END
  END xa[99]
  PIN xa[9]
    DIRECTION OUTPUT ;
    USE SIGNAL ;
    PORT
      LAYER M5 ;
        RECT  66.288 30.156 66.312 30.24 ;
    END
  END xa[9]
  PIN xai[0]
    DIRECTION INPUT ;
    USE SIGNAL ;
    PORT
      LAYER M5 ;
        RECT  131.424 0 131.448 0.084 ;
    END
  END xai[0]
  PIN xai[100]
    DIRECTION INPUT ;
    USE SIGNAL ;
    PORT
      LAYER M5 ;
        RECT  145.824 0 145.848 0.084 ;
    END
  END xai[100]
  PIN xai[101]
    DIRECTION INPUT ;
    USE SIGNAL ;
    PORT
      LAYER M5 ;
        RECT  145.968 0 145.992 0.084 ;
    END
  END xai[101]
  PIN xai[102]
    DIRECTION INPUT ;
    USE SIGNAL ;
    PORT
      LAYER M5 ;
        RECT  146.112 0 146.136 0.084 ;
    END
  END xai[102]
  PIN xai[103]
    DIRECTION INPUT ;
    USE SIGNAL ;
    PORT
      LAYER M5 ;
        RECT  146.256 0 146.28 0.084 ;
    END
  END xai[103]
  PIN xai[104]
    DIRECTION INPUT ;
    USE SIGNAL ;
    PORT
      LAYER M5 ;
        RECT  146.4 0 146.424 0.084 ;
    END
  END xai[104]
  PIN xai[105]
    DIRECTION INPUT ;
    USE SIGNAL ;
    PORT
      LAYER M5 ;
        RECT  146.544 0 146.568 0.084 ;
    END
  END xai[105]
  PIN xai[106]
    DIRECTION INPUT ;
    USE SIGNAL ;
    PORT
      LAYER M5 ;
        RECT  146.688 0 146.712 0.084 ;
    END
  END xai[106]
  PIN xai[107]
    DIRECTION INPUT ;
    USE SIGNAL ;
    PORT
      LAYER M5 ;
        RECT  146.832 0 146.856 0.084 ;
    END
  END xai[107]
  PIN xai[108]
    DIRECTION INPUT ;
    USE SIGNAL ;
    PORT
      LAYER M5 ;
        RECT  146.976 0 147 0.084 ;
    END
  END xai[108]
  PIN xai[109]
    DIRECTION INPUT ;
    USE SIGNAL ;
    PORT
      LAYER M5 ;
        RECT  147.12 0 147.144 0.084 ;
    END
  END xai[109]
  PIN xai[10]
    DIRECTION INPUT ;
    USE SIGNAL ;
    PORT
      LAYER M5 ;
        RECT  132.864 0 132.888 0.084 ;
    END
  END xai[10]
  PIN xai[110]
    DIRECTION INPUT ;
    USE SIGNAL ;
    PORT
      LAYER M5 ;
        RECT  147.264 0 147.288 0.084 ;
    END
  END xai[110]
  PIN xai[111]
    DIRECTION INPUT ;
    USE SIGNAL ;
    PORT
      LAYER M5 ;
        RECT  147.408 0 147.432 0.084 ;
    END
  END xai[111]
  PIN xai[112]
    DIRECTION INPUT ;
    USE SIGNAL ;
    PORT
      LAYER M5 ;
        RECT  147.552 0 147.576 0.084 ;
    END
  END xai[112]
  PIN xai[113]
    DIRECTION INPUT ;
    USE SIGNAL ;
    PORT
      LAYER M5 ;
        RECT  147.696 0 147.72 0.084 ;
    END
  END xai[113]
  PIN xai[114]
    DIRECTION INPUT ;
    USE SIGNAL ;
    PORT
      LAYER M5 ;
        RECT  147.84 0 147.864 0.084 ;
    END
  END xai[114]
  PIN xai[115]
    DIRECTION INPUT ;
    USE SIGNAL ;
    PORT
      LAYER M5 ;
        RECT  147.984 0 148.008 0.084 ;
    END
  END xai[115]
  PIN xai[116]
    DIRECTION INPUT ;
    USE SIGNAL ;
    PORT
      LAYER M5 ;
        RECT  148.128 0 148.152 0.084 ;
    END
  END xai[116]
  PIN xai[117]
    DIRECTION INPUT ;
    USE SIGNAL ;
    PORT
      LAYER M5 ;
        RECT  148.272 0 148.296 0.084 ;
    END
  END xai[117]
  PIN xai[118]
    DIRECTION INPUT ;
    USE SIGNAL ;
    PORT
      LAYER M5 ;
        RECT  148.416 0 148.44 0.084 ;
    END
  END xai[118]
  PIN xai[119]
    DIRECTION INPUT ;
    USE SIGNAL ;
    PORT
      LAYER M5 ;
        RECT  148.56 0 148.584 0.084 ;
    END
  END xai[119]
  PIN xai[11]
    DIRECTION INPUT ;
    USE SIGNAL ;
    PORT
      LAYER M5 ;
        RECT  133.008 0 133.032 0.084 ;
    END
  END xai[11]
  PIN xai[120]
    DIRECTION INPUT ;
    USE SIGNAL ;
    PORT
      LAYER M5 ;
        RECT  148.704 0 148.728 0.084 ;
    END
  END xai[120]
  PIN xai[121]
    DIRECTION INPUT ;
    USE SIGNAL ;
    PORT
      LAYER M5 ;
        RECT  148.848 0 148.872 0.084 ;
    END
  END xai[121]
  PIN xai[122]
    DIRECTION INPUT ;
    USE SIGNAL ;
    PORT
      LAYER M5 ;
        RECT  148.992 0 149.016 0.084 ;
    END
  END xai[122]
  PIN xai[123]
    DIRECTION INPUT ;
    USE SIGNAL ;
    PORT
      LAYER M5 ;
        RECT  149.136 0 149.16 0.084 ;
    END
  END xai[123]
  PIN xai[124]
    DIRECTION INPUT ;
    USE SIGNAL ;
    PORT
      LAYER M5 ;
        RECT  149.28 0 149.304 0.084 ;
    END
  END xai[124]
  PIN xai[125]
    DIRECTION INPUT ;
    USE SIGNAL ;
    PORT
      LAYER M5 ;
        RECT  149.424 0 149.448 0.084 ;
    END
  END xai[125]
  PIN xai[126]
    DIRECTION INPUT ;
    USE SIGNAL ;
    PORT
      LAYER M5 ;
        RECT  149.568 0 149.592 0.084 ;
    END
  END xai[126]
  PIN xai[127]
    DIRECTION INPUT ;
    USE SIGNAL ;
    PORT
      LAYER M5 ;
        RECT  149.712 0 149.736 0.084 ;
    END
  END xai[127]
  PIN xai[128]
    DIRECTION INPUT ;
    USE SIGNAL ;
    PORT
      LAYER M5 ;
        RECT  149.856 0 149.88 0.084 ;
    END
  END xai[128]
  PIN xai[129]
    DIRECTION INPUT ;
    USE SIGNAL ;
    PORT
      LAYER M5 ;
        RECT  150 0 150.024 0.084 ;
    END
  END xai[129]
  PIN xai[12]
    DIRECTION INPUT ;
    USE SIGNAL ;
    PORT
      LAYER M5 ;
        RECT  133.152 0 133.176 0.084 ;
    END
  END xai[12]
  PIN xai[130]
    DIRECTION INPUT ;
    USE SIGNAL ;
    PORT
      LAYER M5 ;
        RECT  150.144 0 150.168 0.084 ;
    END
  END xai[130]
  PIN xai[131]
    DIRECTION INPUT ;
    USE SIGNAL ;
    PORT
      LAYER M5 ;
        RECT  150.288 0 150.312 0.084 ;
    END
  END xai[131]
  PIN xai[132]
    DIRECTION INPUT ;
    USE SIGNAL ;
    PORT
      LAYER M5 ;
        RECT  150.432 0 150.456 0.084 ;
    END
  END xai[132]
  PIN xai[133]
    DIRECTION INPUT ;
    USE SIGNAL ;
    PORT
      LAYER M5 ;
        RECT  150.576 0 150.6 0.084 ;
    END
  END xai[133]
  PIN xai[134]
    DIRECTION INPUT ;
    USE SIGNAL ;
    PORT
      LAYER M5 ;
        RECT  150.72 0 150.744 0.084 ;
    END
  END xai[134]
  PIN xai[135]
    DIRECTION INPUT ;
    USE SIGNAL ;
    PORT
      LAYER M5 ;
        RECT  150.864 0 150.888 0.084 ;
    END
  END xai[135]
  PIN xai[136]
    DIRECTION INPUT ;
    USE SIGNAL ;
    PORT
      LAYER M5 ;
        RECT  151.008 0 151.032 0.084 ;
    END
  END xai[136]
  PIN xai[137]
    DIRECTION INPUT ;
    USE SIGNAL ;
    PORT
      LAYER M5 ;
        RECT  151.152 0 151.176 0.084 ;
    END
  END xai[137]
  PIN xai[138]
    DIRECTION INPUT ;
    USE SIGNAL ;
    PORT
      LAYER M5 ;
        RECT  151.296 0 151.32 0.084 ;
    END
  END xai[138]
  PIN xai[139]
    DIRECTION INPUT ;
    USE SIGNAL ;
    PORT
      LAYER M5 ;
        RECT  151.44 0 151.464 0.084 ;
    END
  END xai[139]
  PIN xai[13]
    DIRECTION INPUT ;
    USE SIGNAL ;
    PORT
      LAYER M5 ;
        RECT  133.296 0 133.32 0.084 ;
    END
  END xai[13]
  PIN xai[140]
    DIRECTION INPUT ;
    USE SIGNAL ;
    PORT
      LAYER M5 ;
        RECT  151.584 0 151.608 0.084 ;
    END
  END xai[140]
  PIN xai[141]
    DIRECTION INPUT ;
    USE SIGNAL ;
    PORT
      LAYER M5 ;
        RECT  151.728 0 151.752 0.084 ;
    END
  END xai[141]
  PIN xai[142]
    DIRECTION INPUT ;
    USE SIGNAL ;
    PORT
      LAYER M5 ;
        RECT  151.872 0 151.896 0.084 ;
    END
  END xai[142]
  PIN xai[143]
    DIRECTION INPUT ;
    USE SIGNAL ;
    PORT
      LAYER M5 ;
        RECT  152.016 0 152.04 0.084 ;
    END
  END xai[143]
  PIN xai[144]
    DIRECTION INPUT ;
    USE SIGNAL ;
    PORT
      LAYER M5 ;
        RECT  152.16 0 152.184 0.084 ;
    END
  END xai[144]
  PIN xai[145]
    DIRECTION INPUT ;
    USE SIGNAL ;
    PORT
      LAYER M5 ;
        RECT  152.304 0 152.328 0.084 ;
    END
  END xai[145]
  PIN xai[146]
    DIRECTION INPUT ;
    USE SIGNAL ;
    PORT
      LAYER M5 ;
        RECT  152.448 0 152.472 0.084 ;
    END
  END xai[146]
  PIN xai[147]
    DIRECTION INPUT ;
    USE SIGNAL ;
    PORT
      LAYER M5 ;
        RECT  152.592 0 152.616 0.084 ;
    END
  END xai[147]
  PIN xai[148]
    DIRECTION INPUT ;
    USE SIGNAL ;
    PORT
      LAYER M5 ;
        RECT  152.736 0 152.76 0.084 ;
    END
  END xai[148]
  PIN xai[149]
    DIRECTION INPUT ;
    USE SIGNAL ;
    PORT
      LAYER M5 ;
        RECT  152.88 0 152.904 0.084 ;
    END
  END xai[149]
  PIN xai[14]
    DIRECTION INPUT ;
    USE SIGNAL ;
    PORT
      LAYER M5 ;
        RECT  133.44 0 133.464 0.084 ;
    END
  END xai[14]
  PIN xai[150]
    DIRECTION INPUT ;
    USE SIGNAL ;
    PORT
      LAYER M5 ;
        RECT  153.024 0 153.048 0.084 ;
    END
  END xai[150]
  PIN xai[151]
    DIRECTION INPUT ;
    USE SIGNAL ;
    PORT
      LAYER M5 ;
        RECT  153.168 0 153.192 0.084 ;
    END
  END xai[151]
  PIN xai[152]
    DIRECTION INPUT ;
    USE SIGNAL ;
    PORT
      LAYER M5 ;
        RECT  153.312 0 153.336 0.084 ;
    END
  END xai[152]
  PIN xai[153]
    DIRECTION INPUT ;
    USE SIGNAL ;
    PORT
      LAYER M5 ;
        RECT  153.456 0 153.48 0.084 ;
    END
  END xai[153]
  PIN xai[154]
    DIRECTION INPUT ;
    USE SIGNAL ;
    PORT
      LAYER M5 ;
        RECT  153.6 0 153.624 0.084 ;
    END
  END xai[154]
  PIN xai[155]
    DIRECTION INPUT ;
    USE SIGNAL ;
    PORT
      LAYER M5 ;
        RECT  153.744 0 153.768 0.084 ;
    END
  END xai[155]
  PIN xai[156]
    DIRECTION INPUT ;
    USE SIGNAL ;
    PORT
      LAYER M5 ;
        RECT  153.888 0 153.912 0.084 ;
    END
  END xai[156]
  PIN xai[157]
    DIRECTION INPUT ;
    USE SIGNAL ;
    PORT
      LAYER M5 ;
        RECT  154.032 0 154.056 0.084 ;
    END
  END xai[157]
  PIN xai[158]
    DIRECTION INPUT ;
    USE SIGNAL ;
    PORT
      LAYER M5 ;
        RECT  154.176 0 154.2 0.084 ;
    END
  END xai[158]
  PIN xai[159]
    DIRECTION INPUT ;
    USE SIGNAL ;
    PORT
      LAYER M5 ;
        RECT  154.32 0 154.344 0.084 ;
    END
  END xai[159]
  PIN xai[15]
    DIRECTION INPUT ;
    USE SIGNAL ;
    PORT
      LAYER M5 ;
        RECT  133.584 0 133.608 0.084 ;
    END
  END xai[15]
  PIN xai[160]
    DIRECTION INPUT ;
    USE SIGNAL ;
    PORT
      LAYER M5 ;
        RECT  154.464 0 154.488 0.084 ;
    END
  END xai[160]
  PIN xai[161]
    DIRECTION INPUT ;
    USE SIGNAL ;
    PORT
      LAYER M5 ;
        RECT  154.608 0 154.632 0.084 ;
    END
  END xai[161]
  PIN xai[162]
    DIRECTION INPUT ;
    USE SIGNAL ;
    PORT
      LAYER M5 ;
        RECT  154.752 0 154.776 0.084 ;
    END
  END xai[162]
  PIN xai[163]
    DIRECTION INPUT ;
    USE SIGNAL ;
    PORT
      LAYER M5 ;
        RECT  154.896 0 154.92 0.084 ;
    END
  END xai[163]
  PIN xai[164]
    DIRECTION INPUT ;
    USE SIGNAL ;
    PORT
      LAYER M5 ;
        RECT  155.04 0 155.064 0.084 ;
    END
  END xai[164]
  PIN xai[165]
    DIRECTION INPUT ;
    USE SIGNAL ;
    PORT
      LAYER M5 ;
        RECT  155.184 0 155.208 0.084 ;
    END
  END xai[165]
  PIN xai[166]
    DIRECTION INPUT ;
    USE SIGNAL ;
    PORT
      LAYER M5 ;
        RECT  155.328 0 155.352 0.084 ;
    END
  END xai[166]
  PIN xai[167]
    DIRECTION INPUT ;
    USE SIGNAL ;
    PORT
      LAYER M5 ;
        RECT  155.472 0 155.496 0.084 ;
    END
  END xai[167]
  PIN xai[168]
    DIRECTION INPUT ;
    USE SIGNAL ;
    PORT
      LAYER M5 ;
        RECT  155.616 0 155.64 0.084 ;
    END
  END xai[168]
  PIN xai[169]
    DIRECTION INPUT ;
    USE SIGNAL ;
    PORT
      LAYER M5 ;
        RECT  155.76 0 155.784 0.084 ;
    END
  END xai[169]
  PIN xai[16]
    DIRECTION INPUT ;
    USE SIGNAL ;
    PORT
      LAYER M5 ;
        RECT  133.728 0 133.752 0.084 ;
    END
  END xai[16]
  PIN xai[170]
    DIRECTION INPUT ;
    USE SIGNAL ;
    PORT
      LAYER M5 ;
        RECT  155.904 0 155.928 0.084 ;
    END
  END xai[170]
  PIN xai[171]
    DIRECTION INPUT ;
    USE SIGNAL ;
    PORT
      LAYER M5 ;
        RECT  156.048 0 156.072 0.084 ;
    END
  END xai[171]
  PIN xai[172]
    DIRECTION INPUT ;
    USE SIGNAL ;
    PORT
      LAYER M5 ;
        RECT  156.192 0 156.216 0.084 ;
    END
  END xai[172]
  PIN xai[173]
    DIRECTION INPUT ;
    USE SIGNAL ;
    PORT
      LAYER M5 ;
        RECT  156.336 0 156.36 0.084 ;
    END
  END xai[173]
  PIN xai[174]
    DIRECTION INPUT ;
    USE SIGNAL ;
    PORT
      LAYER M5 ;
        RECT  156.48 0 156.504 0.084 ;
    END
  END xai[174]
  PIN xai[175]
    DIRECTION INPUT ;
    USE SIGNAL ;
    PORT
      LAYER M5 ;
        RECT  156.624 0 156.648 0.084 ;
    END
  END xai[175]
  PIN xai[176]
    DIRECTION INPUT ;
    USE SIGNAL ;
    PORT
      LAYER M5 ;
        RECT  156.768 0 156.792 0.084 ;
    END
  END xai[176]
  PIN xai[177]
    DIRECTION INPUT ;
    USE SIGNAL ;
    PORT
      LAYER M5 ;
        RECT  156.912 0 156.936 0.084 ;
    END
  END xai[177]
  PIN xai[178]
    DIRECTION INPUT ;
    USE SIGNAL ;
    PORT
      LAYER M5 ;
        RECT  157.056 0 157.08 0.084 ;
    END
  END xai[178]
  PIN xai[179]
    DIRECTION INPUT ;
    USE SIGNAL ;
    PORT
      LAYER M5 ;
        RECT  157.2 0 157.224 0.084 ;
    END
  END xai[179]
  PIN xai[17]
    DIRECTION INPUT ;
    USE SIGNAL ;
    PORT
      LAYER M5 ;
        RECT  133.872 0 133.896 0.084 ;
    END
  END xai[17]
  PIN xai[180]
    DIRECTION INPUT ;
    USE SIGNAL ;
    PORT
      LAYER M5 ;
        RECT  157.344 0 157.368 0.084 ;
    END
  END xai[180]
  PIN xai[181]
    DIRECTION INPUT ;
    USE SIGNAL ;
    PORT
      LAYER M5 ;
        RECT  157.488 0 157.512 0.084 ;
    END
  END xai[181]
  PIN xai[182]
    DIRECTION INPUT ;
    USE SIGNAL ;
    PORT
      LAYER M5 ;
        RECT  157.632 0 157.656 0.084 ;
    END
  END xai[182]
  PIN xai[183]
    DIRECTION INPUT ;
    USE SIGNAL ;
    PORT
      LAYER M5 ;
        RECT  157.776 0 157.8 0.084 ;
    END
  END xai[183]
  PIN xai[184]
    DIRECTION INPUT ;
    USE SIGNAL ;
    PORT
      LAYER M5 ;
        RECT  157.92 0 157.944 0.084 ;
    END
  END xai[184]
  PIN xai[185]
    DIRECTION INPUT ;
    USE SIGNAL ;
    PORT
      LAYER M5 ;
        RECT  158.064 0 158.088 0.084 ;
    END
  END xai[185]
  PIN xai[186]
    DIRECTION INPUT ;
    USE SIGNAL ;
    PORT
      LAYER M5 ;
        RECT  158.208 0 158.232 0.084 ;
    END
  END xai[186]
  PIN xai[187]
    DIRECTION INPUT ;
    USE SIGNAL ;
    PORT
      LAYER M5 ;
        RECT  158.352 0 158.376 0.084 ;
    END
  END xai[187]
  PIN xai[188]
    DIRECTION INPUT ;
    USE SIGNAL ;
    PORT
      LAYER M5 ;
        RECT  158.496 0 158.52 0.084 ;
    END
  END xai[188]
  PIN xai[189]
    DIRECTION INPUT ;
    USE SIGNAL ;
    PORT
      LAYER M5 ;
        RECT  158.64 0 158.664 0.084 ;
    END
  END xai[189]
  PIN xai[18]
    DIRECTION INPUT ;
    USE SIGNAL ;
    PORT
      LAYER M5 ;
        RECT  134.016 0 134.04 0.084 ;
    END
  END xai[18]
  PIN xai[190]
    DIRECTION INPUT ;
    USE SIGNAL ;
    PORT
      LAYER M5 ;
        RECT  158.784 0 158.808 0.084 ;
    END
  END xai[190]
  PIN xai[191]
    DIRECTION INPUT ;
    USE SIGNAL ;
    PORT
      LAYER M5 ;
        RECT  158.928 0 158.952 0.084 ;
    END
  END xai[191]
  PIN xai[192]
    DIRECTION INPUT ;
    USE SIGNAL ;
    PORT
      LAYER M5 ;
        RECT  159.072 0 159.096 0.084 ;
    END
  END xai[192]
  PIN xai[193]
    DIRECTION INPUT ;
    USE SIGNAL ;
    PORT
      LAYER M5 ;
        RECT  159.216 0 159.24 0.084 ;
    END
  END xai[193]
  PIN xai[194]
    DIRECTION INPUT ;
    USE SIGNAL ;
    PORT
      LAYER M5 ;
        RECT  159.36 0 159.384 0.084 ;
    END
  END xai[194]
  PIN xai[195]
    DIRECTION INPUT ;
    USE SIGNAL ;
    PORT
      LAYER M5 ;
        RECT  159.504 0 159.528 0.084 ;
    END
  END xai[195]
  PIN xai[196]
    DIRECTION INPUT ;
    USE SIGNAL ;
    PORT
      LAYER M5 ;
        RECT  159.648 0 159.672 0.084 ;
    END
  END xai[196]
  PIN xai[197]
    DIRECTION INPUT ;
    USE SIGNAL ;
    PORT
      LAYER M5 ;
        RECT  159.792 0 159.816 0.084 ;
    END
  END xai[197]
  PIN xai[198]
    DIRECTION INPUT ;
    USE SIGNAL ;
    PORT
      LAYER M5 ;
        RECT  159.936 0 159.96 0.084 ;
    END
  END xai[198]
  PIN xai[199]
    DIRECTION INPUT ;
    USE SIGNAL ;
    PORT
      LAYER M5 ;
        RECT  160.08 0 160.104 0.084 ;
    END
  END xai[199]
  PIN xai[19]
    DIRECTION INPUT ;
    USE SIGNAL ;
    PORT
      LAYER M5 ;
        RECT  134.16 0 134.184 0.084 ;
    END
  END xai[19]
  PIN xai[1]
    DIRECTION INPUT ;
    USE SIGNAL ;
    PORT
      LAYER M5 ;
        RECT  131.568 0 131.592 0.084 ;
    END
  END xai[1]
  PIN xai[200]
    DIRECTION INPUT ;
    USE SIGNAL ;
    PORT
      LAYER M5 ;
        RECT  160.224 0 160.248 0.084 ;
    END
  END xai[200]
  PIN xai[201]
    DIRECTION INPUT ;
    USE SIGNAL ;
    PORT
      LAYER M5 ;
        RECT  160.368 0 160.392 0.084 ;
    END
  END xai[201]
  PIN xai[202]
    DIRECTION INPUT ;
    USE SIGNAL ;
    PORT
      LAYER M5 ;
        RECT  160.512 0 160.536 0.084 ;
    END
  END xai[202]
  PIN xai[203]
    DIRECTION INPUT ;
    USE SIGNAL ;
    PORT
      LAYER M5 ;
        RECT  160.656 0 160.68 0.084 ;
    END
  END xai[203]
  PIN xai[204]
    DIRECTION INPUT ;
    USE SIGNAL ;
    PORT
      LAYER M5 ;
        RECT  160.8 0 160.824 0.084 ;
    END
  END xai[204]
  PIN xai[205]
    DIRECTION INPUT ;
    USE SIGNAL ;
    PORT
      LAYER M5 ;
        RECT  160.944 0 160.968 0.084 ;
    END
  END xai[205]
  PIN xai[206]
    DIRECTION INPUT ;
    USE SIGNAL ;
    PORT
      LAYER M5 ;
        RECT  161.088 0 161.112 0.084 ;
    END
  END xai[206]
  PIN xai[207]
    DIRECTION INPUT ;
    USE SIGNAL ;
    PORT
      LAYER M5 ;
        RECT  161.232 0 161.256 0.084 ;
    END
  END xai[207]
  PIN xai[208]
    DIRECTION INPUT ;
    USE SIGNAL ;
    PORT
      LAYER M5 ;
        RECT  161.376 0 161.4 0.084 ;
    END
  END xai[208]
  PIN xai[209]
    DIRECTION INPUT ;
    USE SIGNAL ;
    PORT
      LAYER M5 ;
        RECT  161.52 0 161.544 0.084 ;
    END
  END xai[209]
  PIN xai[20]
    DIRECTION INPUT ;
    USE SIGNAL ;
    PORT
      LAYER M5 ;
        RECT  134.304 0 134.328 0.084 ;
    END
  END xai[20]
  PIN xai[210]
    DIRECTION INPUT ;
    USE SIGNAL ;
    PORT
      LAYER M5 ;
        RECT  161.664 0 161.688 0.084 ;
    END
  END xai[210]
  PIN xai[211]
    DIRECTION INPUT ;
    USE SIGNAL ;
    PORT
      LAYER M5 ;
        RECT  161.808 0 161.832 0.084 ;
    END
  END xai[211]
  PIN xai[212]
    DIRECTION INPUT ;
    USE SIGNAL ;
    PORT
      LAYER M5 ;
        RECT  161.952 0 161.976 0.084 ;
    END
  END xai[212]
  PIN xai[213]
    DIRECTION INPUT ;
    USE SIGNAL ;
    PORT
      LAYER M5 ;
        RECT  162.096 0 162.12 0.084 ;
    END
  END xai[213]
  PIN xai[214]
    DIRECTION INPUT ;
    USE SIGNAL ;
    PORT
      LAYER M5 ;
        RECT  162.24 0 162.264 0.084 ;
    END
  END xai[214]
  PIN xai[215]
    DIRECTION INPUT ;
    USE SIGNAL ;
    PORT
      LAYER M5 ;
        RECT  162.384 0 162.408 0.084 ;
    END
  END xai[215]
  PIN xai[216]
    DIRECTION INPUT ;
    USE SIGNAL ;
    PORT
      LAYER M5 ;
        RECT  162.528 0 162.552 0.084 ;
    END
  END xai[216]
  PIN xai[217]
    DIRECTION INPUT ;
    USE SIGNAL ;
    PORT
      LAYER M5 ;
        RECT  162.672 0 162.696 0.084 ;
    END
  END xai[217]
  PIN xai[218]
    DIRECTION INPUT ;
    USE SIGNAL ;
    PORT
      LAYER M5 ;
        RECT  162.816 0 162.84 0.084 ;
    END
  END xai[218]
  PIN xai[219]
    DIRECTION INPUT ;
    USE SIGNAL ;
    PORT
      LAYER M5 ;
        RECT  162.96 0 162.984 0.084 ;
    END
  END xai[219]
  PIN xai[21]
    DIRECTION INPUT ;
    USE SIGNAL ;
    PORT
      LAYER M5 ;
        RECT  134.448 0 134.472 0.084 ;
    END
  END xai[21]
  PIN xai[220]
    DIRECTION INPUT ;
    USE SIGNAL ;
    PORT
      LAYER M5 ;
        RECT  163.104 0 163.128 0.084 ;
    END
  END xai[220]
  PIN xai[221]
    DIRECTION INPUT ;
    USE SIGNAL ;
    PORT
      LAYER M5 ;
        RECT  163.248 0 163.272 0.084 ;
    END
  END xai[221]
  PIN xai[222]
    DIRECTION INPUT ;
    USE SIGNAL ;
    PORT
      LAYER M5 ;
        RECT  163.392 0 163.416 0.084 ;
    END
  END xai[222]
  PIN xai[223]
    DIRECTION INPUT ;
    USE SIGNAL ;
    PORT
      LAYER M5 ;
        RECT  163.536 0 163.56 0.084 ;
    END
  END xai[223]
  PIN xai[224]
    DIRECTION INPUT ;
    USE SIGNAL ;
    PORT
      LAYER M5 ;
        RECT  163.68 0 163.704 0.084 ;
    END
  END xai[224]
  PIN xai[225]
    DIRECTION INPUT ;
    USE SIGNAL ;
    PORT
      LAYER M5 ;
        RECT  163.824 0 163.848 0.084 ;
    END
  END xai[225]
  PIN xai[226]
    DIRECTION INPUT ;
    USE SIGNAL ;
    PORT
      LAYER M5 ;
        RECT  163.968 0 163.992 0.084 ;
    END
  END xai[226]
  PIN xai[227]
    DIRECTION INPUT ;
    USE SIGNAL ;
    PORT
      LAYER M5 ;
        RECT  164.112 0 164.136 0.084 ;
    END
  END xai[227]
  PIN xai[228]
    DIRECTION INPUT ;
    USE SIGNAL ;
    PORT
      LAYER M5 ;
        RECT  164.256 0 164.28 0.084 ;
    END
  END xai[228]
  PIN xai[229]
    DIRECTION INPUT ;
    USE SIGNAL ;
    PORT
      LAYER M5 ;
        RECT  164.4 0 164.424 0.084 ;
    END
  END xai[229]
  PIN xai[22]
    DIRECTION INPUT ;
    USE SIGNAL ;
    PORT
      LAYER M5 ;
        RECT  134.592 0 134.616 0.084 ;
    END
  END xai[22]
  PIN xai[230]
    DIRECTION INPUT ;
    USE SIGNAL ;
    PORT
      LAYER M5 ;
        RECT  164.544 0 164.568 0.084 ;
    END
  END xai[230]
  PIN xai[231]
    DIRECTION INPUT ;
    USE SIGNAL ;
    PORT
      LAYER M5 ;
        RECT  164.688 0 164.712 0.084 ;
    END
  END xai[231]
  PIN xai[232]
    DIRECTION INPUT ;
    USE SIGNAL ;
    PORT
      LAYER M5 ;
        RECT  164.832 0 164.856 0.084 ;
    END
  END xai[232]
  PIN xai[233]
    DIRECTION INPUT ;
    USE SIGNAL ;
    PORT
      LAYER M5 ;
        RECT  164.976 0 165 0.084 ;
    END
  END xai[233]
  PIN xai[234]
    DIRECTION INPUT ;
    USE SIGNAL ;
    PORT
      LAYER M5 ;
        RECT  165.12 0 165.144 0.084 ;
    END
  END xai[234]
  PIN xai[235]
    DIRECTION INPUT ;
    USE SIGNAL ;
    PORT
      LAYER M5 ;
        RECT  165.264 0 165.288 0.084 ;
    END
  END xai[235]
  PIN xai[236]
    DIRECTION INPUT ;
    USE SIGNAL ;
    PORT
      LAYER M5 ;
        RECT  165.408 0 165.432 0.084 ;
    END
  END xai[236]
  PIN xai[237]
    DIRECTION INPUT ;
    USE SIGNAL ;
    PORT
      LAYER M5 ;
        RECT  165.552 0 165.576 0.084 ;
    END
  END xai[237]
  PIN xai[238]
    DIRECTION INPUT ;
    USE SIGNAL ;
    PORT
      LAYER M5 ;
        RECT  165.696 0 165.72 0.084 ;
    END
  END xai[238]
  PIN xai[239]
    DIRECTION INPUT ;
    USE SIGNAL ;
    PORT
      LAYER M5 ;
        RECT  165.84 0 165.864 0.084 ;
    END
  END xai[239]
  PIN xai[23]
    DIRECTION INPUT ;
    USE SIGNAL ;
    PORT
      LAYER M5 ;
        RECT  134.736 0 134.76 0.084 ;
    END
  END xai[23]
  PIN xai[240]
    DIRECTION INPUT ;
    USE SIGNAL ;
    PORT
      LAYER M5 ;
        RECT  165.984 0 166.008 0.084 ;
    END
  END xai[240]
  PIN xai[241]
    DIRECTION INPUT ;
    USE SIGNAL ;
    PORT
      LAYER M5 ;
        RECT  166.128 0 166.152 0.084 ;
    END
  END xai[241]
  PIN xai[242]
    DIRECTION INPUT ;
    USE SIGNAL ;
    PORT
      LAYER M5 ;
        RECT  166.272 0 166.296 0.084 ;
    END
  END xai[242]
  PIN xai[243]
    DIRECTION INPUT ;
    USE SIGNAL ;
    PORT
      LAYER M5 ;
        RECT  166.416 0 166.44 0.084 ;
    END
  END xai[243]
  PIN xai[244]
    DIRECTION INPUT ;
    USE SIGNAL ;
    PORT
      LAYER M5 ;
        RECT  166.56 0 166.584 0.084 ;
    END
  END xai[244]
  PIN xai[245]
    DIRECTION INPUT ;
    USE SIGNAL ;
    PORT
      LAYER M5 ;
        RECT  166.704 0 166.728 0.084 ;
    END
  END xai[245]
  PIN xai[246]
    DIRECTION INPUT ;
    USE SIGNAL ;
    PORT
      LAYER M5 ;
        RECT  166.848 0 166.872 0.084 ;
    END
  END xai[246]
  PIN xai[247]
    DIRECTION INPUT ;
    USE SIGNAL ;
    PORT
      LAYER M5 ;
        RECT  166.992 0 167.016 0.084 ;
    END
  END xai[247]
  PIN xai[248]
    DIRECTION INPUT ;
    USE SIGNAL ;
    PORT
      LAYER M5 ;
        RECT  167.136 0 167.16 0.084 ;
    END
  END xai[248]
  PIN xai[249]
    DIRECTION INPUT ;
    USE SIGNAL ;
    PORT
      LAYER M5 ;
        RECT  167.28 0 167.304 0.084 ;
    END
  END xai[249]
  PIN xai[24]
    DIRECTION INPUT ;
    USE SIGNAL ;
    PORT
      LAYER M5 ;
        RECT  134.88 0 134.904 0.084 ;
    END
  END xai[24]
  PIN xai[250]
    DIRECTION INPUT ;
    USE SIGNAL ;
    PORT
      LAYER M5 ;
        RECT  167.424 0 167.448 0.084 ;
    END
  END xai[250]
  PIN xai[251]
    DIRECTION INPUT ;
    USE SIGNAL ;
    PORT
      LAYER M5 ;
        RECT  167.568 0 167.592 0.084 ;
    END
  END xai[251]
  PIN xai[252]
    DIRECTION INPUT ;
    USE SIGNAL ;
    PORT
      LAYER M5 ;
        RECT  167.712 0 167.736 0.084 ;
    END
  END xai[252]
  PIN xai[253]
    DIRECTION INPUT ;
    USE SIGNAL ;
    PORT
      LAYER M5 ;
        RECT  167.856 0 167.88 0.084 ;
    END
  END xai[253]
  PIN xai[254]
    DIRECTION INPUT ;
    USE SIGNAL ;
    PORT
      LAYER M5 ;
        RECT  168 0 168.024 0.084 ;
    END
  END xai[254]
  PIN xai[255]
    DIRECTION INPUT ;
    USE SIGNAL ;
    PORT
      LAYER M5 ;
        RECT  168.144 0 168.168 0.084 ;
    END
  END xai[255]
  PIN xai[256]
    DIRECTION INPUT ;
    USE SIGNAL ;
    PORT
      LAYER M5 ;
        RECT  168.288 0 168.312 0.084 ;
    END
  END xai[256]
  PIN xai[257]
    DIRECTION INPUT ;
    USE SIGNAL ;
    PORT
      LAYER M5 ;
        RECT  168.432 0 168.456 0.084 ;
    END
  END xai[257]
  PIN xai[258]
    DIRECTION INPUT ;
    USE SIGNAL ;
    PORT
      LAYER M5 ;
        RECT  168.576 0 168.6 0.084 ;
    END
  END xai[258]
  PIN xai[259]
    DIRECTION INPUT ;
    USE SIGNAL ;
    PORT
      LAYER M5 ;
        RECT  168.72 0 168.744 0.084 ;
    END
  END xai[259]
  PIN xai[25]
    DIRECTION INPUT ;
    USE SIGNAL ;
    PORT
      LAYER M5 ;
        RECT  135.024 0 135.048 0.084 ;
    END
  END xai[25]
  PIN xai[260]
    DIRECTION INPUT ;
    USE SIGNAL ;
    PORT
      LAYER M5 ;
        RECT  168.864 0 168.888 0.084 ;
    END
  END xai[260]
  PIN xai[261]
    DIRECTION INPUT ;
    USE SIGNAL ;
    PORT
      LAYER M5 ;
        RECT  169.008 0 169.032 0.084 ;
    END
  END xai[261]
  PIN xai[262]
    DIRECTION INPUT ;
    USE SIGNAL ;
    PORT
      LAYER M5 ;
        RECT  169.152 0 169.176 0.084 ;
    END
  END xai[262]
  PIN xai[263]
    DIRECTION INPUT ;
    USE SIGNAL ;
    PORT
      LAYER M5 ;
        RECT  169.296 0 169.32 0.084 ;
    END
  END xai[263]
  PIN xai[264]
    DIRECTION INPUT ;
    USE SIGNAL ;
    PORT
      LAYER M5 ;
        RECT  169.44 0 169.464 0.084 ;
    END
  END xai[264]
  PIN xai[265]
    DIRECTION INPUT ;
    USE SIGNAL ;
    PORT
      LAYER M5 ;
        RECT  169.584 0 169.608 0.084 ;
    END
  END xai[265]
  PIN xai[266]
    DIRECTION INPUT ;
    USE SIGNAL ;
    PORT
      LAYER M5 ;
        RECT  169.728 0 169.752 0.084 ;
    END
  END xai[266]
  PIN xai[267]
    DIRECTION INPUT ;
    USE SIGNAL ;
    PORT
      LAYER M5 ;
        RECT  169.872 0 169.896 0.084 ;
    END
  END xai[267]
  PIN xai[268]
    DIRECTION INPUT ;
    USE SIGNAL ;
    PORT
      LAYER M5 ;
        RECT  170.016 0 170.04 0.084 ;
    END
  END xai[268]
  PIN xai[269]
    DIRECTION INPUT ;
    USE SIGNAL ;
    PORT
      LAYER M5 ;
        RECT  170.16 0 170.184 0.084 ;
    END
  END xai[269]
  PIN xai[26]
    DIRECTION INPUT ;
    USE SIGNAL ;
    PORT
      LAYER M5 ;
        RECT  135.168 0 135.192 0.084 ;
    END
  END xai[26]
  PIN xai[270]
    DIRECTION INPUT ;
    USE SIGNAL ;
    PORT
      LAYER M5 ;
        RECT  170.304 0 170.328 0.084 ;
    END
  END xai[270]
  PIN xai[271]
    DIRECTION INPUT ;
    USE SIGNAL ;
    PORT
      LAYER M5 ;
        RECT  170.448 0 170.472 0.084 ;
    END
  END xai[271]
  PIN xai[272]
    DIRECTION INPUT ;
    USE SIGNAL ;
    PORT
      LAYER M5 ;
        RECT  170.592 0 170.616 0.084 ;
    END
  END xai[272]
  PIN xai[273]
    DIRECTION INPUT ;
    USE SIGNAL ;
    PORT
      LAYER M5 ;
        RECT  170.736 0 170.76 0.084 ;
    END
  END xai[273]
  PIN xai[274]
    DIRECTION INPUT ;
    USE SIGNAL ;
    PORT
      LAYER M5 ;
        RECT  170.88 0 170.904 0.084 ;
    END
  END xai[274]
  PIN xai[275]
    DIRECTION INPUT ;
    USE SIGNAL ;
    PORT
      LAYER M5 ;
        RECT  171.024 0 171.048 0.084 ;
    END
  END xai[275]
  PIN xai[276]
    DIRECTION INPUT ;
    USE SIGNAL ;
    PORT
      LAYER M5 ;
        RECT  171.168 0 171.192 0.084 ;
    END
  END xai[276]
  PIN xai[277]
    DIRECTION INPUT ;
    USE SIGNAL ;
    PORT
      LAYER M5 ;
        RECT  171.312 0 171.336 0.084 ;
    END
  END xai[277]
  PIN xai[278]
    DIRECTION INPUT ;
    USE SIGNAL ;
    PORT
      LAYER M5 ;
        RECT  171.456 0 171.48 0.084 ;
    END
  END xai[278]
  PIN xai[279]
    DIRECTION INPUT ;
    USE SIGNAL ;
    PORT
      LAYER M5 ;
        RECT  171.6 0 171.624 0.084 ;
    END
  END xai[279]
  PIN xai[27]
    DIRECTION INPUT ;
    USE SIGNAL ;
    PORT
      LAYER M5 ;
        RECT  135.312 0 135.336 0.084 ;
    END
  END xai[27]
  PIN xai[280]
    DIRECTION INPUT ;
    USE SIGNAL ;
    PORT
      LAYER M5 ;
        RECT  171.744 0 171.768 0.084 ;
    END
  END xai[280]
  PIN xai[281]
    DIRECTION INPUT ;
    USE SIGNAL ;
    PORT
      LAYER M5 ;
        RECT  171.888 0 171.912 0.084 ;
    END
  END xai[281]
  PIN xai[282]
    DIRECTION INPUT ;
    USE SIGNAL ;
    PORT
      LAYER M5 ;
        RECT  172.032 0 172.056 0.084 ;
    END
  END xai[282]
  PIN xai[28]
    DIRECTION INPUT ;
    USE SIGNAL ;
    PORT
      LAYER M5 ;
        RECT  135.456 0 135.48 0.084 ;
    END
  END xai[28]
  PIN xai[29]
    DIRECTION INPUT ;
    USE SIGNAL ;
    PORT
      LAYER M5 ;
        RECT  135.6 0 135.624 0.084 ;
    END
  END xai[29]
  PIN xai[2]
    DIRECTION INPUT ;
    USE SIGNAL ;
    PORT
      LAYER M5 ;
        RECT  131.712 0 131.736 0.084 ;
    END
  END xai[2]
  PIN xai[30]
    DIRECTION INPUT ;
    USE SIGNAL ;
    PORT
      LAYER M5 ;
        RECT  135.744 0 135.768 0.084 ;
    END
  END xai[30]
  PIN xai[31]
    DIRECTION INPUT ;
    USE SIGNAL ;
    PORT
      LAYER M5 ;
        RECT  135.888 0 135.912 0.084 ;
    END
  END xai[31]
  PIN xai[32]
    DIRECTION INPUT ;
    USE SIGNAL ;
    PORT
      LAYER M5 ;
        RECT  136.032 0 136.056 0.084 ;
    END
  END xai[32]
  PIN xai[33]
    DIRECTION INPUT ;
    USE SIGNAL ;
    PORT
      LAYER M5 ;
        RECT  136.176 0 136.2 0.084 ;
    END
  END xai[33]
  PIN xai[34]
    DIRECTION INPUT ;
    USE SIGNAL ;
    PORT
      LAYER M5 ;
        RECT  136.32 0 136.344 0.084 ;
    END
  END xai[34]
  PIN xai[35]
    DIRECTION INPUT ;
    USE SIGNAL ;
    PORT
      LAYER M5 ;
        RECT  136.464 0 136.488 0.084 ;
    END
  END xai[35]
  PIN xai[36]
    DIRECTION INPUT ;
    USE SIGNAL ;
    PORT
      LAYER M5 ;
        RECT  136.608 0 136.632 0.084 ;
    END
  END xai[36]
  PIN xai[37]
    DIRECTION INPUT ;
    USE SIGNAL ;
    PORT
      LAYER M5 ;
        RECT  136.752 0 136.776 0.084 ;
    END
  END xai[37]
  PIN xai[38]
    DIRECTION INPUT ;
    USE SIGNAL ;
    PORT
      LAYER M5 ;
        RECT  136.896 0 136.92 0.084 ;
    END
  END xai[38]
  PIN xai[39]
    DIRECTION INPUT ;
    USE SIGNAL ;
    PORT
      LAYER M5 ;
        RECT  137.04 0 137.064 0.084 ;
    END
  END xai[39]
  PIN xai[3]
    DIRECTION INPUT ;
    USE SIGNAL ;
    PORT
      LAYER M5 ;
        RECT  131.856 0 131.88 0.084 ;
    END
  END xai[3]
  PIN xai[40]
    DIRECTION INPUT ;
    USE SIGNAL ;
    PORT
      LAYER M5 ;
        RECT  137.184 0 137.208 0.084 ;
    END
  END xai[40]
  PIN xai[41]
    DIRECTION INPUT ;
    USE SIGNAL ;
    PORT
      LAYER M5 ;
        RECT  137.328 0 137.352 0.084 ;
    END
  END xai[41]
  PIN xai[42]
    DIRECTION INPUT ;
    USE SIGNAL ;
    PORT
      LAYER M5 ;
        RECT  137.472 0 137.496 0.084 ;
    END
  END xai[42]
  PIN xai[43]
    DIRECTION INPUT ;
    USE SIGNAL ;
    PORT
      LAYER M5 ;
        RECT  137.616 0 137.64 0.084 ;
    END
  END xai[43]
  PIN xai[44]
    DIRECTION INPUT ;
    USE SIGNAL ;
    PORT
      LAYER M5 ;
        RECT  137.76 0 137.784 0.084 ;
    END
  END xai[44]
  PIN xai[45]
    DIRECTION INPUT ;
    USE SIGNAL ;
    PORT
      LAYER M5 ;
        RECT  137.904 0 137.928 0.084 ;
    END
  END xai[45]
  PIN xai[46]
    DIRECTION INPUT ;
    USE SIGNAL ;
    PORT
      LAYER M5 ;
        RECT  138.048 0 138.072 0.084 ;
    END
  END xai[46]
  PIN xai[47]
    DIRECTION INPUT ;
    USE SIGNAL ;
    PORT
      LAYER M5 ;
        RECT  138.192 0 138.216 0.084 ;
    END
  END xai[47]
  PIN xai[48]
    DIRECTION INPUT ;
    USE SIGNAL ;
    PORT
      LAYER M5 ;
        RECT  138.336 0 138.36 0.084 ;
    END
  END xai[48]
  PIN xai[49]
    DIRECTION INPUT ;
    USE SIGNAL ;
    PORT
      LAYER M5 ;
        RECT  138.48 0 138.504 0.084 ;
    END
  END xai[49]
  PIN xai[4]
    DIRECTION INPUT ;
    USE SIGNAL ;
    PORT
      LAYER M5 ;
        RECT  132 0 132.024 0.084 ;
    END
  END xai[4]
  PIN xai[50]
    DIRECTION INPUT ;
    USE SIGNAL ;
    PORT
      LAYER M5 ;
        RECT  138.624 0 138.648 0.084 ;
    END
  END xai[50]
  PIN xai[51]
    DIRECTION INPUT ;
    USE SIGNAL ;
    PORT
      LAYER M5 ;
        RECT  138.768 0 138.792 0.084 ;
    END
  END xai[51]
  PIN xai[52]
    DIRECTION INPUT ;
    USE SIGNAL ;
    PORT
      LAYER M5 ;
        RECT  138.912 0 138.936 0.084 ;
    END
  END xai[52]
  PIN xai[53]
    DIRECTION INPUT ;
    USE SIGNAL ;
    PORT
      LAYER M5 ;
        RECT  139.056 0 139.08 0.084 ;
    END
  END xai[53]
  PIN xai[54]
    DIRECTION INPUT ;
    USE SIGNAL ;
    PORT
      LAYER M5 ;
        RECT  139.2 0 139.224 0.084 ;
    END
  END xai[54]
  PIN xai[55]
    DIRECTION INPUT ;
    USE SIGNAL ;
    PORT
      LAYER M5 ;
        RECT  139.344 0 139.368 0.084 ;
    END
  END xai[55]
  PIN xai[56]
    DIRECTION INPUT ;
    USE SIGNAL ;
    PORT
      LAYER M5 ;
        RECT  139.488 0 139.512 0.084 ;
    END
  END xai[56]
  PIN xai[57]
    DIRECTION INPUT ;
    USE SIGNAL ;
    PORT
      LAYER M5 ;
        RECT  139.632 0 139.656 0.084 ;
    END
  END xai[57]
  PIN xai[58]
    DIRECTION INPUT ;
    USE SIGNAL ;
    PORT
      LAYER M5 ;
        RECT  139.776 0 139.8 0.084 ;
    END
  END xai[58]
  PIN xai[59]
    DIRECTION INPUT ;
    USE SIGNAL ;
    PORT
      LAYER M5 ;
        RECT  139.92 0 139.944 0.084 ;
    END
  END xai[59]
  PIN xai[5]
    DIRECTION INPUT ;
    USE SIGNAL ;
    PORT
      LAYER M5 ;
        RECT  132.144 0 132.168 0.084 ;
    END
  END xai[5]
  PIN xai[60]
    DIRECTION INPUT ;
    USE SIGNAL ;
    PORT
      LAYER M5 ;
        RECT  140.064 0 140.088 0.084 ;
    END
  END xai[60]
  PIN xai[61]
    DIRECTION INPUT ;
    USE SIGNAL ;
    PORT
      LAYER M5 ;
        RECT  140.208 0 140.232 0.084 ;
    END
  END xai[61]
  PIN xai[62]
    DIRECTION INPUT ;
    USE SIGNAL ;
    PORT
      LAYER M5 ;
        RECT  140.352 0 140.376 0.084 ;
    END
  END xai[62]
  PIN xai[63]
    DIRECTION INPUT ;
    USE SIGNAL ;
    PORT
      LAYER M5 ;
        RECT  140.496 0 140.52 0.084 ;
    END
  END xai[63]
  PIN xai[64]
    DIRECTION INPUT ;
    USE SIGNAL ;
    PORT
      LAYER M5 ;
        RECT  140.64 0 140.664 0.084 ;
    END
  END xai[64]
  PIN xai[65]
    DIRECTION INPUT ;
    USE SIGNAL ;
    PORT
      LAYER M5 ;
        RECT  140.784 0 140.808 0.084 ;
    END
  END xai[65]
  PIN xai[66]
    DIRECTION INPUT ;
    USE SIGNAL ;
    PORT
      LAYER M5 ;
        RECT  140.928 0 140.952 0.084 ;
    END
  END xai[66]
  PIN xai[67]
    DIRECTION INPUT ;
    USE SIGNAL ;
    PORT
      LAYER M5 ;
        RECT  141.072 0 141.096 0.084 ;
    END
  END xai[67]
  PIN xai[68]
    DIRECTION INPUT ;
    USE SIGNAL ;
    PORT
      LAYER M5 ;
        RECT  141.216 0 141.24 0.084 ;
    END
  END xai[68]
  PIN xai[69]
    DIRECTION INPUT ;
    USE SIGNAL ;
    PORT
      LAYER M5 ;
        RECT  141.36 0 141.384 0.084 ;
    END
  END xai[69]
  PIN xai[6]
    DIRECTION INPUT ;
    USE SIGNAL ;
    PORT
      LAYER M5 ;
        RECT  132.288 0 132.312 0.084 ;
    END
  END xai[6]
  PIN xai[70]
    DIRECTION INPUT ;
    USE SIGNAL ;
    PORT
      LAYER M5 ;
        RECT  141.504 0 141.528 0.084 ;
    END
  END xai[70]
  PIN xai[71]
    DIRECTION INPUT ;
    USE SIGNAL ;
    PORT
      LAYER M5 ;
        RECT  141.648 0 141.672 0.084 ;
    END
  END xai[71]
  PIN xai[72]
    DIRECTION INPUT ;
    USE SIGNAL ;
    PORT
      LAYER M5 ;
        RECT  141.792 0 141.816 0.084 ;
    END
  END xai[72]
  PIN xai[73]
    DIRECTION INPUT ;
    USE SIGNAL ;
    PORT
      LAYER M5 ;
        RECT  141.936 0 141.96 0.084 ;
    END
  END xai[73]
  PIN xai[74]
    DIRECTION INPUT ;
    USE SIGNAL ;
    PORT
      LAYER M5 ;
        RECT  142.08 0 142.104 0.084 ;
    END
  END xai[74]
  PIN xai[75]
    DIRECTION INPUT ;
    USE SIGNAL ;
    PORT
      LAYER M5 ;
        RECT  142.224 0 142.248 0.084 ;
    END
  END xai[75]
  PIN xai[76]
    DIRECTION INPUT ;
    USE SIGNAL ;
    PORT
      LAYER M5 ;
        RECT  142.368 0 142.392 0.084 ;
    END
  END xai[76]
  PIN xai[77]
    DIRECTION INPUT ;
    USE SIGNAL ;
    PORT
      LAYER M5 ;
        RECT  142.512 0 142.536 0.084 ;
    END
  END xai[77]
  PIN xai[78]
    DIRECTION INPUT ;
    USE SIGNAL ;
    PORT
      LAYER M5 ;
        RECT  142.656 0 142.68 0.084 ;
    END
  END xai[78]
  PIN xai[79]
    DIRECTION INPUT ;
    USE SIGNAL ;
    PORT
      LAYER M5 ;
        RECT  142.8 0 142.824 0.084 ;
    END
  END xai[79]
  PIN xai[7]
    DIRECTION INPUT ;
    USE SIGNAL ;
    PORT
      LAYER M5 ;
        RECT  132.432 0 132.456 0.084 ;
    END
  END xai[7]
  PIN xai[80]
    DIRECTION INPUT ;
    USE SIGNAL ;
    PORT
      LAYER M5 ;
        RECT  142.944 0 142.968 0.084 ;
    END
  END xai[80]
  PIN xai[81]
    DIRECTION INPUT ;
    USE SIGNAL ;
    PORT
      LAYER M5 ;
        RECT  143.088 0 143.112 0.084 ;
    END
  END xai[81]
  PIN xai[82]
    DIRECTION INPUT ;
    USE SIGNAL ;
    PORT
      LAYER M5 ;
        RECT  143.232 0 143.256 0.084 ;
    END
  END xai[82]
  PIN xai[83]
    DIRECTION INPUT ;
    USE SIGNAL ;
    PORT
      LAYER M5 ;
        RECT  143.376 0 143.4 0.084 ;
    END
  END xai[83]
  PIN xai[84]
    DIRECTION INPUT ;
    USE SIGNAL ;
    PORT
      LAYER M5 ;
        RECT  143.52 0 143.544 0.084 ;
    END
  END xai[84]
  PIN xai[85]
    DIRECTION INPUT ;
    USE SIGNAL ;
    PORT
      LAYER M5 ;
        RECT  143.664 0 143.688 0.084 ;
    END
  END xai[85]
  PIN xai[86]
    DIRECTION INPUT ;
    USE SIGNAL ;
    PORT
      LAYER M5 ;
        RECT  143.808 0 143.832 0.084 ;
    END
  END xai[86]
  PIN xai[87]
    DIRECTION INPUT ;
    USE SIGNAL ;
    PORT
      LAYER M5 ;
        RECT  143.952 0 143.976 0.084 ;
    END
  END xai[87]
  PIN xai[88]
    DIRECTION INPUT ;
    USE SIGNAL ;
    PORT
      LAYER M5 ;
        RECT  144.096 0 144.12 0.084 ;
    END
  END xai[88]
  PIN xai[89]
    DIRECTION INPUT ;
    USE SIGNAL ;
    PORT
      LAYER M5 ;
        RECT  144.24 0 144.264 0.084 ;
    END
  END xai[89]
  PIN xai[8]
    DIRECTION INPUT ;
    USE SIGNAL ;
    PORT
      LAYER M5 ;
        RECT  132.576 0 132.6 0.084 ;
    END
  END xai[8]
  PIN xai[90]
    DIRECTION INPUT ;
    USE SIGNAL ;
    PORT
      LAYER M5 ;
        RECT  144.384 0 144.408 0.084 ;
    END
  END xai[90]
  PIN xai[91]
    DIRECTION INPUT ;
    USE SIGNAL ;
    PORT
      LAYER M5 ;
        RECT  144.528 0 144.552 0.084 ;
    END
  END xai[91]
  PIN xai[92]
    DIRECTION INPUT ;
    USE SIGNAL ;
    PORT
      LAYER M5 ;
        RECT  144.672 0 144.696 0.084 ;
    END
  END xai[92]
  PIN xai[93]
    DIRECTION INPUT ;
    USE SIGNAL ;
    PORT
      LAYER M5 ;
        RECT  144.816 0 144.84 0.084 ;
    END
  END xai[93]
  PIN xai[94]
    DIRECTION INPUT ;
    USE SIGNAL ;
    PORT
      LAYER M5 ;
        RECT  144.96 0 144.984 0.084 ;
    END
  END xai[94]
  PIN xai[95]
    DIRECTION INPUT ;
    USE SIGNAL ;
    PORT
      LAYER M5 ;
        RECT  145.104 0 145.128 0.084 ;
    END
  END xai[95]
  PIN xai[96]
    DIRECTION INPUT ;
    USE SIGNAL ;
    PORT
      LAYER M5 ;
        RECT  145.248 0 145.272 0.084 ;
    END
  END xai[96]
  PIN xai[97]
    DIRECTION INPUT ;
    USE SIGNAL ;
    PORT
      LAYER M5 ;
        RECT  145.392 0 145.416 0.084 ;
    END
  END xai[97]
  PIN xai[98]
    DIRECTION INPUT ;
    USE SIGNAL ;
    PORT
      LAYER M5 ;
        RECT  145.536 0 145.56 0.084 ;
    END
  END xai[98]
  PIN xai[99]
    DIRECTION INPUT ;
    USE SIGNAL ;
    PORT
      LAYER M5 ;
        RECT  145.68 0 145.704 0.084 ;
    END
  END xai[99]
  PIN xai[9]
    DIRECTION INPUT ;
    USE SIGNAL ;
    PORT
      LAYER M5 ;
        RECT  132.72 0 132.744 0.084 ;
    END
  END xai[9]
  PIN xb[0]
    DIRECTION OUTPUT ;
    USE SIGNAL ;
    PORT
      LAYER M5 ;
        RECT  106.704 30.156 106.728 30.24 ;
    END
  END xb[0]
  PIN xb[100]
    DIRECTION OUTPUT ;
    USE SIGNAL ;
    PORT
      LAYER M5 ;
        RECT  121.104 30.156 121.128 30.24 ;
    END
  END xb[100]
  PIN xb[101]
    DIRECTION OUTPUT ;
    USE SIGNAL ;
    PORT
      LAYER M5 ;
        RECT  121.248 30.156 121.272 30.24 ;
    END
  END xb[101]
  PIN xb[102]
    DIRECTION OUTPUT ;
    USE SIGNAL ;
    PORT
      LAYER M5 ;
        RECT  121.392 30.156 121.416 30.24 ;
    END
  END xb[102]
  PIN xb[103]
    DIRECTION OUTPUT ;
    USE SIGNAL ;
    PORT
      LAYER M5 ;
        RECT  121.536 30.156 121.56 30.24 ;
    END
  END xb[103]
  PIN xb[104]
    DIRECTION OUTPUT ;
    USE SIGNAL ;
    PORT
      LAYER M5 ;
        RECT  121.68 30.156 121.704 30.24 ;
    END
  END xb[104]
  PIN xb[105]
    DIRECTION OUTPUT ;
    USE SIGNAL ;
    PORT
      LAYER M5 ;
        RECT  121.824 30.156 121.848 30.24 ;
    END
  END xb[105]
  PIN xb[106]
    DIRECTION OUTPUT ;
    USE SIGNAL ;
    PORT
      LAYER M5 ;
        RECT  121.968 30.156 121.992 30.24 ;
    END
  END xb[106]
  PIN xb[107]
    DIRECTION OUTPUT ;
    USE SIGNAL ;
    PORT
      LAYER M5 ;
        RECT  122.112 30.156 122.136 30.24 ;
    END
  END xb[107]
  PIN xb[108]
    DIRECTION OUTPUT ;
    USE SIGNAL ;
    PORT
      LAYER M5 ;
        RECT  122.256 30.156 122.28 30.24 ;
    END
  END xb[108]
  PIN xb[109]
    DIRECTION OUTPUT ;
    USE SIGNAL ;
    PORT
      LAYER M5 ;
        RECT  122.4 30.156 122.424 30.24 ;
    END
  END xb[109]
  PIN xb[10]
    DIRECTION OUTPUT ;
    USE SIGNAL ;
    PORT
      LAYER M5 ;
        RECT  108.144 30.156 108.168 30.24 ;
    END
  END xb[10]
  PIN xb[110]
    DIRECTION OUTPUT ;
    USE SIGNAL ;
    PORT
      LAYER M5 ;
        RECT  122.544 30.156 122.568 30.24 ;
    END
  END xb[110]
  PIN xb[111]
    DIRECTION OUTPUT ;
    USE SIGNAL ;
    PORT
      LAYER M5 ;
        RECT  122.688 30.156 122.712 30.24 ;
    END
  END xb[111]
  PIN xb[112]
    DIRECTION OUTPUT ;
    USE SIGNAL ;
    PORT
      LAYER M5 ;
        RECT  122.832 30.156 122.856 30.24 ;
    END
  END xb[112]
  PIN xb[113]
    DIRECTION OUTPUT ;
    USE SIGNAL ;
    PORT
      LAYER M5 ;
        RECT  122.976 30.156 123 30.24 ;
    END
  END xb[113]
  PIN xb[114]
    DIRECTION OUTPUT ;
    USE SIGNAL ;
    PORT
      LAYER M5 ;
        RECT  123.12 30.156 123.144 30.24 ;
    END
  END xb[114]
  PIN xb[115]
    DIRECTION OUTPUT ;
    USE SIGNAL ;
    PORT
      LAYER M5 ;
        RECT  123.264 30.156 123.288 30.24 ;
    END
  END xb[115]
  PIN xb[116]
    DIRECTION OUTPUT ;
    USE SIGNAL ;
    PORT
      LAYER M5 ;
        RECT  123.408 30.156 123.432 30.24 ;
    END
  END xb[116]
  PIN xb[117]
    DIRECTION OUTPUT ;
    USE SIGNAL ;
    PORT
      LAYER M5 ;
        RECT  123.552 30.156 123.576 30.24 ;
    END
  END xb[117]
  PIN xb[118]
    DIRECTION OUTPUT ;
    USE SIGNAL ;
    PORT
      LAYER M5 ;
        RECT  123.696 30.156 123.72 30.24 ;
    END
  END xb[118]
  PIN xb[119]
    DIRECTION OUTPUT ;
    USE SIGNAL ;
    PORT
      LAYER M5 ;
        RECT  123.84 30.156 123.864 30.24 ;
    END
  END xb[119]
  PIN xb[11]
    DIRECTION OUTPUT ;
    USE SIGNAL ;
    PORT
      LAYER M5 ;
        RECT  108.288 30.156 108.312 30.24 ;
    END
  END xb[11]
  PIN xb[120]
    DIRECTION OUTPUT ;
    USE SIGNAL ;
    PORT
      LAYER M5 ;
        RECT  123.984 30.156 124.008 30.24 ;
    END
  END xb[120]
  PIN xb[121]
    DIRECTION OUTPUT ;
    USE SIGNAL ;
    PORT
      LAYER M5 ;
        RECT  124.128 30.156 124.152 30.24 ;
    END
  END xb[121]
  PIN xb[122]
    DIRECTION OUTPUT ;
    USE SIGNAL ;
    PORT
      LAYER M5 ;
        RECT  124.272 30.156 124.296 30.24 ;
    END
  END xb[122]
  PIN xb[123]
    DIRECTION OUTPUT ;
    USE SIGNAL ;
    PORT
      LAYER M5 ;
        RECT  124.416 30.156 124.44 30.24 ;
    END
  END xb[123]
  PIN xb[124]
    DIRECTION OUTPUT ;
    USE SIGNAL ;
    PORT
      LAYER M5 ;
        RECT  124.56 30.156 124.584 30.24 ;
    END
  END xb[124]
  PIN xb[125]
    DIRECTION OUTPUT ;
    USE SIGNAL ;
    PORT
      LAYER M5 ;
        RECT  124.704 30.156 124.728 30.24 ;
    END
  END xb[125]
  PIN xb[126]
    DIRECTION OUTPUT ;
    USE SIGNAL ;
    PORT
      LAYER M5 ;
        RECT  124.848 30.156 124.872 30.24 ;
    END
  END xb[126]
  PIN xb[127]
    DIRECTION OUTPUT ;
    USE SIGNAL ;
    PORT
      LAYER M5 ;
        RECT  124.992 30.156 125.016 30.24 ;
    END
  END xb[127]
  PIN xb[128]
    DIRECTION OUTPUT ;
    USE SIGNAL ;
    PORT
      LAYER M5 ;
        RECT  125.136 30.156 125.16 30.24 ;
    END
  END xb[128]
  PIN xb[129]
    DIRECTION OUTPUT ;
    USE SIGNAL ;
    PORT
      LAYER M5 ;
        RECT  125.28 30.156 125.304 30.24 ;
    END
  END xb[129]
  PIN xb[12]
    DIRECTION OUTPUT ;
    USE SIGNAL ;
    PORT
      LAYER M5 ;
        RECT  108.432 30.156 108.456 30.24 ;
    END
  END xb[12]
  PIN xb[130]
    DIRECTION OUTPUT ;
    USE SIGNAL ;
    PORT
      LAYER M5 ;
        RECT  125.424 30.156 125.448 30.24 ;
    END
  END xb[130]
  PIN xb[131]
    DIRECTION OUTPUT ;
    USE SIGNAL ;
    PORT
      LAYER M5 ;
        RECT  125.568 30.156 125.592 30.24 ;
    END
  END xb[131]
  PIN xb[132]
    DIRECTION OUTPUT ;
    USE SIGNAL ;
    PORT
      LAYER M5 ;
        RECT  125.712 30.156 125.736 30.24 ;
    END
  END xb[132]
  PIN xb[133]
    DIRECTION OUTPUT ;
    USE SIGNAL ;
    PORT
      LAYER M5 ;
        RECT  125.856 30.156 125.88 30.24 ;
    END
  END xb[133]
  PIN xb[134]
    DIRECTION OUTPUT ;
    USE SIGNAL ;
    PORT
      LAYER M5 ;
        RECT  126 30.156 126.024 30.24 ;
    END
  END xb[134]
  PIN xb[135]
    DIRECTION OUTPUT ;
    USE SIGNAL ;
    PORT
      LAYER M5 ;
        RECT  126.144 30.156 126.168 30.24 ;
    END
  END xb[135]
  PIN xb[136]
    DIRECTION OUTPUT ;
    USE SIGNAL ;
    PORT
      LAYER M5 ;
        RECT  126.288 30.156 126.312 30.24 ;
    END
  END xb[136]
  PIN xb[137]
    DIRECTION OUTPUT ;
    USE SIGNAL ;
    PORT
      LAYER M5 ;
        RECT  126.432 30.156 126.456 30.24 ;
    END
  END xb[137]
  PIN xb[138]
    DIRECTION OUTPUT ;
    USE SIGNAL ;
    PORT
      LAYER M5 ;
        RECT  126.576 30.156 126.6 30.24 ;
    END
  END xb[138]
  PIN xb[139]
    DIRECTION OUTPUT ;
    USE SIGNAL ;
    PORT
      LAYER M5 ;
        RECT  126.72 30.156 126.744 30.24 ;
    END
  END xb[139]
  PIN xb[13]
    DIRECTION OUTPUT ;
    USE SIGNAL ;
    PORT
      LAYER M5 ;
        RECT  108.576 30.156 108.6 30.24 ;
    END
  END xb[13]
  PIN xb[140]
    DIRECTION OUTPUT ;
    USE SIGNAL ;
    PORT
      LAYER M5 ;
        RECT  126.864 30.156 126.888 30.24 ;
    END
  END xb[140]
  PIN xb[141]
    DIRECTION OUTPUT ;
    USE SIGNAL ;
    PORT
      LAYER M5 ;
        RECT  127.008 30.156 127.032 30.24 ;
    END
  END xb[141]
  PIN xb[142]
    DIRECTION OUTPUT ;
    USE SIGNAL ;
    PORT
      LAYER M5 ;
        RECT  127.152 30.156 127.176 30.24 ;
    END
  END xb[142]
  PIN xb[143]
    DIRECTION OUTPUT ;
    USE SIGNAL ;
    PORT
      LAYER M5 ;
        RECT  127.296 30.156 127.32 30.24 ;
    END
  END xb[143]
  PIN xb[144]
    DIRECTION OUTPUT ;
    USE SIGNAL ;
    PORT
      LAYER M5 ;
        RECT  127.44 30.156 127.464 30.24 ;
    END
  END xb[144]
  PIN xb[145]
    DIRECTION OUTPUT ;
    USE SIGNAL ;
    PORT
      LAYER M5 ;
        RECT  127.584 30.156 127.608 30.24 ;
    END
  END xb[145]
  PIN xb[146]
    DIRECTION OUTPUT ;
    USE SIGNAL ;
    PORT
      LAYER M5 ;
        RECT  127.728 30.156 127.752 30.24 ;
    END
  END xb[146]
  PIN xb[147]
    DIRECTION OUTPUT ;
    USE SIGNAL ;
    PORT
      LAYER M5 ;
        RECT  127.872 30.156 127.896 30.24 ;
    END
  END xb[147]
  PIN xb[148]
    DIRECTION OUTPUT ;
    USE SIGNAL ;
    PORT
      LAYER M5 ;
        RECT  128.016 30.156 128.04 30.24 ;
    END
  END xb[148]
  PIN xb[149]
    DIRECTION OUTPUT ;
    USE SIGNAL ;
    PORT
      LAYER M5 ;
        RECT  128.16 30.156 128.184 30.24 ;
    END
  END xb[149]
  PIN xb[14]
    DIRECTION OUTPUT ;
    USE SIGNAL ;
    PORT
      LAYER M5 ;
        RECT  108.72 30.156 108.744 30.24 ;
    END
  END xb[14]
  PIN xb[150]
    DIRECTION OUTPUT ;
    USE SIGNAL ;
    PORT
      LAYER M5 ;
        RECT  128.304 30.156 128.328 30.24 ;
    END
  END xb[150]
  PIN xb[151]
    DIRECTION OUTPUT ;
    USE SIGNAL ;
    PORT
      LAYER M5 ;
        RECT  128.448 30.156 128.472 30.24 ;
    END
  END xb[151]
  PIN xb[152]
    DIRECTION OUTPUT ;
    USE SIGNAL ;
    PORT
      LAYER M5 ;
        RECT  128.592 30.156 128.616 30.24 ;
    END
  END xb[152]
  PIN xb[153]
    DIRECTION OUTPUT ;
    USE SIGNAL ;
    PORT
      LAYER M5 ;
        RECT  128.736 30.156 128.76 30.24 ;
    END
  END xb[153]
  PIN xb[154]
    DIRECTION OUTPUT ;
    USE SIGNAL ;
    PORT
      LAYER M5 ;
        RECT  128.88 30.156 128.904 30.24 ;
    END
  END xb[154]
  PIN xb[155]
    DIRECTION OUTPUT ;
    USE SIGNAL ;
    PORT
      LAYER M5 ;
        RECT  129.024 30.156 129.048 30.24 ;
    END
  END xb[155]
  PIN xb[156]
    DIRECTION OUTPUT ;
    USE SIGNAL ;
    PORT
      LAYER M5 ;
        RECT  129.168 30.156 129.192 30.24 ;
    END
  END xb[156]
  PIN xb[157]
    DIRECTION OUTPUT ;
    USE SIGNAL ;
    PORT
      LAYER M5 ;
        RECT  129.312 30.156 129.336 30.24 ;
    END
  END xb[157]
  PIN xb[158]
    DIRECTION OUTPUT ;
    USE SIGNAL ;
    PORT
      LAYER M5 ;
        RECT  129.456 30.156 129.48 30.24 ;
    END
  END xb[158]
  PIN xb[159]
    DIRECTION OUTPUT ;
    USE SIGNAL ;
    PORT
      LAYER M5 ;
        RECT  129.6 30.156 129.624 30.24 ;
    END
  END xb[159]
  PIN xb[15]
    DIRECTION OUTPUT ;
    USE SIGNAL ;
    PORT
      LAYER M5 ;
        RECT  108.864 30.156 108.888 30.24 ;
    END
  END xb[15]
  PIN xb[160]
    DIRECTION OUTPUT ;
    USE SIGNAL ;
    PORT
      LAYER M5 ;
        RECT  129.744 30.156 129.768 30.24 ;
    END
  END xb[160]
  PIN xb[161]
    DIRECTION OUTPUT ;
    USE SIGNAL ;
    PORT
      LAYER M5 ;
        RECT  129.888 30.156 129.912 30.24 ;
    END
  END xb[161]
  PIN xb[162]
    DIRECTION OUTPUT ;
    USE SIGNAL ;
    PORT
      LAYER M5 ;
        RECT  130.032 30.156 130.056 30.24 ;
    END
  END xb[162]
  PIN xb[163]
    DIRECTION OUTPUT ;
    USE SIGNAL ;
    PORT
      LAYER M5 ;
        RECT  130.176 30.156 130.2 30.24 ;
    END
  END xb[163]
  PIN xb[164]
    DIRECTION OUTPUT ;
    USE SIGNAL ;
    PORT
      LAYER M5 ;
        RECT  130.32 30.156 130.344 30.24 ;
    END
  END xb[164]
  PIN xb[165]
    DIRECTION OUTPUT ;
    USE SIGNAL ;
    PORT
      LAYER M5 ;
        RECT  130.464 30.156 130.488 30.24 ;
    END
  END xb[165]
  PIN xb[166]
    DIRECTION OUTPUT ;
    USE SIGNAL ;
    PORT
      LAYER M5 ;
        RECT  130.608 30.156 130.632 30.24 ;
    END
  END xb[166]
  PIN xb[167]
    DIRECTION OUTPUT ;
    USE SIGNAL ;
    PORT
      LAYER M5 ;
        RECT  130.752 30.156 130.776 30.24 ;
    END
  END xb[167]
  PIN xb[168]
    DIRECTION OUTPUT ;
    USE SIGNAL ;
    PORT
      LAYER M5 ;
        RECT  130.896 30.156 130.92 30.24 ;
    END
  END xb[168]
  PIN xb[169]
    DIRECTION OUTPUT ;
    USE SIGNAL ;
    PORT
      LAYER M5 ;
        RECT  131.04 30.156 131.064 30.24 ;
    END
  END xb[169]
  PIN xb[16]
    DIRECTION OUTPUT ;
    USE SIGNAL ;
    PORT
      LAYER M5 ;
        RECT  109.008 30.156 109.032 30.24 ;
    END
  END xb[16]
  PIN xb[170]
    DIRECTION OUTPUT ;
    USE SIGNAL ;
    PORT
      LAYER M5 ;
        RECT  131.184 30.156 131.208 30.24 ;
    END
  END xb[170]
  PIN xb[171]
    DIRECTION OUTPUT ;
    USE SIGNAL ;
    PORT
      LAYER M5 ;
        RECT  131.328 30.156 131.352 30.24 ;
    END
  END xb[171]
  PIN xb[172]
    DIRECTION OUTPUT ;
    USE SIGNAL ;
    PORT
      LAYER M5 ;
        RECT  131.472 30.156 131.496 30.24 ;
    END
  END xb[172]
  PIN xb[173]
    DIRECTION OUTPUT ;
    USE SIGNAL ;
    PORT
      LAYER M5 ;
        RECT  131.616 30.156 131.64 30.24 ;
    END
  END xb[173]
  PIN xb[174]
    DIRECTION OUTPUT ;
    USE SIGNAL ;
    PORT
      LAYER M5 ;
        RECT  131.76 30.156 131.784 30.24 ;
    END
  END xb[174]
  PIN xb[175]
    DIRECTION OUTPUT ;
    USE SIGNAL ;
    PORT
      LAYER M5 ;
        RECT  131.904 30.156 131.928 30.24 ;
    END
  END xb[175]
  PIN xb[176]
    DIRECTION OUTPUT ;
    USE SIGNAL ;
    PORT
      LAYER M5 ;
        RECT  132.048 30.156 132.072 30.24 ;
    END
  END xb[176]
  PIN xb[177]
    DIRECTION OUTPUT ;
    USE SIGNAL ;
    PORT
      LAYER M5 ;
        RECT  132.192 30.156 132.216 30.24 ;
    END
  END xb[177]
  PIN xb[178]
    DIRECTION OUTPUT ;
    USE SIGNAL ;
    PORT
      LAYER M5 ;
        RECT  132.336 30.156 132.36 30.24 ;
    END
  END xb[178]
  PIN xb[179]
    DIRECTION OUTPUT ;
    USE SIGNAL ;
    PORT
      LAYER M5 ;
        RECT  132.48 30.156 132.504 30.24 ;
    END
  END xb[179]
  PIN xb[17]
    DIRECTION OUTPUT ;
    USE SIGNAL ;
    PORT
      LAYER M5 ;
        RECT  109.152 30.156 109.176 30.24 ;
    END
  END xb[17]
  PIN xb[180]
    DIRECTION OUTPUT ;
    USE SIGNAL ;
    PORT
      LAYER M5 ;
        RECT  132.624 30.156 132.648 30.24 ;
    END
  END xb[180]
  PIN xb[181]
    DIRECTION OUTPUT ;
    USE SIGNAL ;
    PORT
      LAYER M5 ;
        RECT  132.768 30.156 132.792 30.24 ;
    END
  END xb[181]
  PIN xb[182]
    DIRECTION OUTPUT ;
    USE SIGNAL ;
    PORT
      LAYER M5 ;
        RECT  132.912 30.156 132.936 30.24 ;
    END
  END xb[182]
  PIN xb[183]
    DIRECTION OUTPUT ;
    USE SIGNAL ;
    PORT
      LAYER M5 ;
        RECT  133.056 30.156 133.08 30.24 ;
    END
  END xb[183]
  PIN xb[184]
    DIRECTION OUTPUT ;
    USE SIGNAL ;
    PORT
      LAYER M5 ;
        RECT  133.2 30.156 133.224 30.24 ;
    END
  END xb[184]
  PIN xb[185]
    DIRECTION OUTPUT ;
    USE SIGNAL ;
    PORT
      LAYER M5 ;
        RECT  133.344 30.156 133.368 30.24 ;
    END
  END xb[185]
  PIN xb[186]
    DIRECTION OUTPUT ;
    USE SIGNAL ;
    PORT
      LAYER M5 ;
        RECT  133.488 30.156 133.512 30.24 ;
    END
  END xb[186]
  PIN xb[187]
    DIRECTION OUTPUT ;
    USE SIGNAL ;
    PORT
      LAYER M5 ;
        RECT  133.632 30.156 133.656 30.24 ;
    END
  END xb[187]
  PIN xb[188]
    DIRECTION OUTPUT ;
    USE SIGNAL ;
    PORT
      LAYER M5 ;
        RECT  133.776 30.156 133.8 30.24 ;
    END
  END xb[188]
  PIN xb[189]
    DIRECTION OUTPUT ;
    USE SIGNAL ;
    PORT
      LAYER M5 ;
        RECT  133.92 30.156 133.944 30.24 ;
    END
  END xb[189]
  PIN xb[18]
    DIRECTION OUTPUT ;
    USE SIGNAL ;
    PORT
      LAYER M5 ;
        RECT  109.296 30.156 109.32 30.24 ;
    END
  END xb[18]
  PIN xb[190]
    DIRECTION OUTPUT ;
    USE SIGNAL ;
    PORT
      LAYER M5 ;
        RECT  134.064 30.156 134.088 30.24 ;
    END
  END xb[190]
  PIN xb[191]
    DIRECTION OUTPUT ;
    USE SIGNAL ;
    PORT
      LAYER M5 ;
        RECT  134.208 30.156 134.232 30.24 ;
    END
  END xb[191]
  PIN xb[192]
    DIRECTION OUTPUT ;
    USE SIGNAL ;
    PORT
      LAYER M5 ;
        RECT  134.352 30.156 134.376 30.24 ;
    END
  END xb[192]
  PIN xb[193]
    DIRECTION OUTPUT ;
    USE SIGNAL ;
    PORT
      LAYER M5 ;
        RECT  134.496 30.156 134.52 30.24 ;
    END
  END xb[193]
  PIN xb[194]
    DIRECTION OUTPUT ;
    USE SIGNAL ;
    PORT
      LAYER M5 ;
        RECT  134.64 30.156 134.664 30.24 ;
    END
  END xb[194]
  PIN xb[195]
    DIRECTION OUTPUT ;
    USE SIGNAL ;
    PORT
      LAYER M5 ;
        RECT  134.784 30.156 134.808 30.24 ;
    END
  END xb[195]
  PIN xb[196]
    DIRECTION OUTPUT ;
    USE SIGNAL ;
    PORT
      LAYER M5 ;
        RECT  134.928 30.156 134.952 30.24 ;
    END
  END xb[196]
  PIN xb[197]
    DIRECTION OUTPUT ;
    USE SIGNAL ;
    PORT
      LAYER M5 ;
        RECT  135.072 30.156 135.096 30.24 ;
    END
  END xb[197]
  PIN xb[198]
    DIRECTION OUTPUT ;
    USE SIGNAL ;
    PORT
      LAYER M5 ;
        RECT  135.216 30.156 135.24 30.24 ;
    END
  END xb[198]
  PIN xb[199]
    DIRECTION OUTPUT ;
    USE SIGNAL ;
    PORT
      LAYER M5 ;
        RECT  135.36 30.156 135.384 30.24 ;
    END
  END xb[199]
  PIN xb[19]
    DIRECTION OUTPUT ;
    USE SIGNAL ;
    PORT
      LAYER M5 ;
        RECT  109.44 30.156 109.464 30.24 ;
    END
  END xb[19]
  PIN xb[1]
    DIRECTION OUTPUT ;
    USE SIGNAL ;
    PORT
      LAYER M5 ;
        RECT  106.848 30.156 106.872 30.24 ;
    END
  END xb[1]
  PIN xb[200]
    DIRECTION OUTPUT ;
    USE SIGNAL ;
    PORT
      LAYER M5 ;
        RECT  135.504 30.156 135.528 30.24 ;
    END
  END xb[200]
  PIN xb[201]
    DIRECTION OUTPUT ;
    USE SIGNAL ;
    PORT
      LAYER M5 ;
        RECT  135.648 30.156 135.672 30.24 ;
    END
  END xb[201]
  PIN xb[202]
    DIRECTION OUTPUT ;
    USE SIGNAL ;
    PORT
      LAYER M5 ;
        RECT  135.792 30.156 135.816 30.24 ;
    END
  END xb[202]
  PIN xb[203]
    DIRECTION OUTPUT ;
    USE SIGNAL ;
    PORT
      LAYER M5 ;
        RECT  135.936 30.156 135.96 30.24 ;
    END
  END xb[203]
  PIN xb[204]
    DIRECTION OUTPUT ;
    USE SIGNAL ;
    PORT
      LAYER M5 ;
        RECT  136.08 30.156 136.104 30.24 ;
    END
  END xb[204]
  PIN xb[205]
    DIRECTION OUTPUT ;
    USE SIGNAL ;
    PORT
      LAYER M5 ;
        RECT  136.224 30.156 136.248 30.24 ;
    END
  END xb[205]
  PIN xb[206]
    DIRECTION OUTPUT ;
    USE SIGNAL ;
    PORT
      LAYER M5 ;
        RECT  136.368 30.156 136.392 30.24 ;
    END
  END xb[206]
  PIN xb[207]
    DIRECTION OUTPUT ;
    USE SIGNAL ;
    PORT
      LAYER M5 ;
        RECT  136.512 30.156 136.536 30.24 ;
    END
  END xb[207]
  PIN xb[208]
    DIRECTION OUTPUT ;
    USE SIGNAL ;
    PORT
      LAYER M5 ;
        RECT  136.656 30.156 136.68 30.24 ;
    END
  END xb[208]
  PIN xb[209]
    DIRECTION OUTPUT ;
    USE SIGNAL ;
    PORT
      LAYER M5 ;
        RECT  136.8 30.156 136.824 30.24 ;
    END
  END xb[209]
  PIN xb[20]
    DIRECTION OUTPUT ;
    USE SIGNAL ;
    PORT
      LAYER M5 ;
        RECT  109.584 30.156 109.608 30.24 ;
    END
  END xb[20]
  PIN xb[210]
    DIRECTION OUTPUT ;
    USE SIGNAL ;
    PORT
      LAYER M5 ;
        RECT  136.944 30.156 136.968 30.24 ;
    END
  END xb[210]
  PIN xb[211]
    DIRECTION OUTPUT ;
    USE SIGNAL ;
    PORT
      LAYER M5 ;
        RECT  137.088 30.156 137.112 30.24 ;
    END
  END xb[211]
  PIN xb[212]
    DIRECTION OUTPUT ;
    USE SIGNAL ;
    PORT
      LAYER M5 ;
        RECT  137.232 30.156 137.256 30.24 ;
    END
  END xb[212]
  PIN xb[213]
    DIRECTION OUTPUT ;
    USE SIGNAL ;
    PORT
      LAYER M5 ;
        RECT  137.376 30.156 137.4 30.24 ;
    END
  END xb[213]
  PIN xb[214]
    DIRECTION OUTPUT ;
    USE SIGNAL ;
    PORT
      LAYER M5 ;
        RECT  137.52 30.156 137.544 30.24 ;
    END
  END xb[214]
  PIN xb[215]
    DIRECTION OUTPUT ;
    USE SIGNAL ;
    PORT
      LAYER M5 ;
        RECT  137.664 30.156 137.688 30.24 ;
    END
  END xb[215]
  PIN xb[216]
    DIRECTION OUTPUT ;
    USE SIGNAL ;
    PORT
      LAYER M5 ;
        RECT  137.808 30.156 137.832 30.24 ;
    END
  END xb[216]
  PIN xb[217]
    DIRECTION OUTPUT ;
    USE SIGNAL ;
    PORT
      LAYER M5 ;
        RECT  137.952 30.156 137.976 30.24 ;
    END
  END xb[217]
  PIN xb[218]
    DIRECTION OUTPUT ;
    USE SIGNAL ;
    PORT
      LAYER M5 ;
        RECT  138.096 30.156 138.12 30.24 ;
    END
  END xb[218]
  PIN xb[219]
    DIRECTION OUTPUT ;
    USE SIGNAL ;
    PORT
      LAYER M5 ;
        RECT  138.24 30.156 138.264 30.24 ;
    END
  END xb[219]
  PIN xb[21]
    DIRECTION OUTPUT ;
    USE SIGNAL ;
    PORT
      LAYER M5 ;
        RECT  109.728 30.156 109.752 30.24 ;
    END
  END xb[21]
  PIN xb[220]
    DIRECTION OUTPUT ;
    USE SIGNAL ;
    PORT
      LAYER M5 ;
        RECT  138.384 30.156 138.408 30.24 ;
    END
  END xb[220]
  PIN xb[221]
    DIRECTION OUTPUT ;
    USE SIGNAL ;
    PORT
      LAYER M5 ;
        RECT  138.528 30.156 138.552 30.24 ;
    END
  END xb[221]
  PIN xb[222]
    DIRECTION OUTPUT ;
    USE SIGNAL ;
    PORT
      LAYER M5 ;
        RECT  138.672 30.156 138.696 30.24 ;
    END
  END xb[222]
  PIN xb[223]
    DIRECTION OUTPUT ;
    USE SIGNAL ;
    PORT
      LAYER M5 ;
        RECT  138.816 30.156 138.84 30.24 ;
    END
  END xb[223]
  PIN xb[224]
    DIRECTION OUTPUT ;
    USE SIGNAL ;
    PORT
      LAYER M5 ;
        RECT  138.96 30.156 138.984 30.24 ;
    END
  END xb[224]
  PIN xb[225]
    DIRECTION OUTPUT ;
    USE SIGNAL ;
    PORT
      LAYER M5 ;
        RECT  139.104 30.156 139.128 30.24 ;
    END
  END xb[225]
  PIN xb[226]
    DIRECTION OUTPUT ;
    USE SIGNAL ;
    PORT
      LAYER M5 ;
        RECT  139.248 30.156 139.272 30.24 ;
    END
  END xb[226]
  PIN xb[227]
    DIRECTION OUTPUT ;
    USE SIGNAL ;
    PORT
      LAYER M5 ;
        RECT  139.392 30.156 139.416 30.24 ;
    END
  END xb[227]
  PIN xb[228]
    DIRECTION OUTPUT ;
    USE SIGNAL ;
    PORT
      LAYER M5 ;
        RECT  139.536 30.156 139.56 30.24 ;
    END
  END xb[228]
  PIN xb[229]
    DIRECTION OUTPUT ;
    USE SIGNAL ;
    PORT
      LAYER M5 ;
        RECT  139.68 30.156 139.704 30.24 ;
    END
  END xb[229]
  PIN xb[22]
    DIRECTION OUTPUT ;
    USE SIGNAL ;
    PORT
      LAYER M5 ;
        RECT  109.872 30.156 109.896 30.24 ;
    END
  END xb[22]
  PIN xb[230]
    DIRECTION OUTPUT ;
    USE SIGNAL ;
    PORT
      LAYER M5 ;
        RECT  139.824 30.156 139.848 30.24 ;
    END
  END xb[230]
  PIN xb[231]
    DIRECTION OUTPUT ;
    USE SIGNAL ;
    PORT
      LAYER M5 ;
        RECT  139.968 30.156 139.992 30.24 ;
    END
  END xb[231]
  PIN xb[232]
    DIRECTION OUTPUT ;
    USE SIGNAL ;
    PORT
      LAYER M5 ;
        RECT  140.112 30.156 140.136 30.24 ;
    END
  END xb[232]
  PIN xb[233]
    DIRECTION OUTPUT ;
    USE SIGNAL ;
    PORT
      LAYER M5 ;
        RECT  140.256 30.156 140.28 30.24 ;
    END
  END xb[233]
  PIN xb[234]
    DIRECTION OUTPUT ;
    USE SIGNAL ;
    PORT
      LAYER M5 ;
        RECT  140.4 30.156 140.424 30.24 ;
    END
  END xb[234]
  PIN xb[235]
    DIRECTION OUTPUT ;
    USE SIGNAL ;
    PORT
      LAYER M5 ;
        RECT  140.544 30.156 140.568 30.24 ;
    END
  END xb[235]
  PIN xb[236]
    DIRECTION OUTPUT ;
    USE SIGNAL ;
    PORT
      LAYER M5 ;
        RECT  140.688 30.156 140.712 30.24 ;
    END
  END xb[236]
  PIN xb[237]
    DIRECTION OUTPUT ;
    USE SIGNAL ;
    PORT
      LAYER M5 ;
        RECT  140.832 30.156 140.856 30.24 ;
    END
  END xb[237]
  PIN xb[238]
    DIRECTION OUTPUT ;
    USE SIGNAL ;
    PORT
      LAYER M5 ;
        RECT  140.976 30.156 141 30.24 ;
    END
  END xb[238]
  PIN xb[239]
    DIRECTION OUTPUT ;
    USE SIGNAL ;
    PORT
      LAYER M5 ;
        RECT  141.12 30.156 141.144 30.24 ;
    END
  END xb[239]
  PIN xb[23]
    DIRECTION OUTPUT ;
    USE SIGNAL ;
    PORT
      LAYER M5 ;
        RECT  110.016 30.156 110.04 30.24 ;
    END
  END xb[23]
  PIN xb[240]
    DIRECTION OUTPUT ;
    USE SIGNAL ;
    PORT
      LAYER M5 ;
        RECT  141.264 30.156 141.288 30.24 ;
    END
  END xb[240]
  PIN xb[241]
    DIRECTION OUTPUT ;
    USE SIGNAL ;
    PORT
      LAYER M5 ;
        RECT  141.408 30.156 141.432 30.24 ;
    END
  END xb[241]
  PIN xb[242]
    DIRECTION OUTPUT ;
    USE SIGNAL ;
    PORT
      LAYER M5 ;
        RECT  141.552 30.156 141.576 30.24 ;
    END
  END xb[242]
  PIN xb[243]
    DIRECTION OUTPUT ;
    USE SIGNAL ;
    PORT
      LAYER M5 ;
        RECT  141.696 30.156 141.72 30.24 ;
    END
  END xb[243]
  PIN xb[244]
    DIRECTION OUTPUT ;
    USE SIGNAL ;
    PORT
      LAYER M5 ;
        RECT  141.84 30.156 141.864 30.24 ;
    END
  END xb[244]
  PIN xb[245]
    DIRECTION OUTPUT ;
    USE SIGNAL ;
    PORT
      LAYER M5 ;
        RECT  141.984 30.156 142.008 30.24 ;
    END
  END xb[245]
  PIN xb[246]
    DIRECTION OUTPUT ;
    USE SIGNAL ;
    PORT
      LAYER M5 ;
        RECT  142.128 30.156 142.152 30.24 ;
    END
  END xb[246]
  PIN xb[247]
    DIRECTION OUTPUT ;
    USE SIGNAL ;
    PORT
      LAYER M5 ;
        RECT  142.272 30.156 142.296 30.24 ;
    END
  END xb[247]
  PIN xb[248]
    DIRECTION OUTPUT ;
    USE SIGNAL ;
    PORT
      LAYER M5 ;
        RECT  142.416 30.156 142.44 30.24 ;
    END
  END xb[248]
  PIN xb[249]
    DIRECTION OUTPUT ;
    USE SIGNAL ;
    PORT
      LAYER M5 ;
        RECT  142.56 30.156 142.584 30.24 ;
    END
  END xb[249]
  PIN xb[24]
    DIRECTION OUTPUT ;
    USE SIGNAL ;
    PORT
      LAYER M5 ;
        RECT  110.16 30.156 110.184 30.24 ;
    END
  END xb[24]
  PIN xb[250]
    DIRECTION OUTPUT ;
    USE SIGNAL ;
    PORT
      LAYER M5 ;
        RECT  142.704 30.156 142.728 30.24 ;
    END
  END xb[250]
  PIN xb[251]
    DIRECTION OUTPUT ;
    USE SIGNAL ;
    PORT
      LAYER M5 ;
        RECT  142.848 30.156 142.872 30.24 ;
    END
  END xb[251]
  PIN xb[252]
    DIRECTION OUTPUT ;
    USE SIGNAL ;
    PORT
      LAYER M5 ;
        RECT  142.992 30.156 143.016 30.24 ;
    END
  END xb[252]
  PIN xb[253]
    DIRECTION OUTPUT ;
    USE SIGNAL ;
    PORT
      LAYER M5 ;
        RECT  143.136 30.156 143.16 30.24 ;
    END
  END xb[253]
  PIN xb[254]
    DIRECTION OUTPUT ;
    USE SIGNAL ;
    PORT
      LAYER M5 ;
        RECT  143.28 30.156 143.304 30.24 ;
    END
  END xb[254]
  PIN xb[255]
    DIRECTION OUTPUT ;
    USE SIGNAL ;
    PORT
      LAYER M5 ;
        RECT  143.424 30.156 143.448 30.24 ;
    END
  END xb[255]
  PIN xb[256]
    DIRECTION OUTPUT ;
    USE SIGNAL ;
    PORT
      LAYER M5 ;
        RECT  143.568 30.156 143.592 30.24 ;
    END
  END xb[256]
  PIN xb[257]
    DIRECTION OUTPUT ;
    USE SIGNAL ;
    PORT
      LAYER M5 ;
        RECT  143.712 30.156 143.736 30.24 ;
    END
  END xb[257]
  PIN xb[258]
    DIRECTION OUTPUT ;
    USE SIGNAL ;
    PORT
      LAYER M5 ;
        RECT  143.856 30.156 143.88 30.24 ;
    END
  END xb[258]
  PIN xb[259]
    DIRECTION OUTPUT ;
    USE SIGNAL ;
    PORT
      LAYER M5 ;
        RECT  144 30.156 144.024 30.24 ;
    END
  END xb[259]
  PIN xb[25]
    DIRECTION OUTPUT ;
    USE SIGNAL ;
    PORT
      LAYER M5 ;
        RECT  110.304 30.156 110.328 30.24 ;
    END
  END xb[25]
  PIN xb[260]
    DIRECTION OUTPUT ;
    USE SIGNAL ;
    PORT
      LAYER M5 ;
        RECT  144.144 30.156 144.168 30.24 ;
    END
  END xb[260]
  PIN xb[261]
    DIRECTION OUTPUT ;
    USE SIGNAL ;
    PORT
      LAYER M5 ;
        RECT  144.288 30.156 144.312 30.24 ;
    END
  END xb[261]
  PIN xb[262]
    DIRECTION OUTPUT ;
    USE SIGNAL ;
    PORT
      LAYER M5 ;
        RECT  144.432 30.156 144.456 30.24 ;
    END
  END xb[262]
  PIN xb[263]
    DIRECTION OUTPUT ;
    USE SIGNAL ;
    PORT
      LAYER M5 ;
        RECT  144.576 30.156 144.6 30.24 ;
    END
  END xb[263]
  PIN xb[264]
    DIRECTION OUTPUT ;
    USE SIGNAL ;
    PORT
      LAYER M5 ;
        RECT  144.72 30.156 144.744 30.24 ;
    END
  END xb[264]
  PIN xb[265]
    DIRECTION OUTPUT ;
    USE SIGNAL ;
    PORT
      LAYER M5 ;
        RECT  144.864 30.156 144.888 30.24 ;
    END
  END xb[265]
  PIN xb[26]
    DIRECTION OUTPUT ;
    USE SIGNAL ;
    PORT
      LAYER M5 ;
        RECT  110.448 30.156 110.472 30.24 ;
    END
  END xb[26]
  PIN xb[27]
    DIRECTION OUTPUT ;
    USE SIGNAL ;
    PORT
      LAYER M5 ;
        RECT  110.592 30.156 110.616 30.24 ;
    END
  END xb[27]
  PIN xb[28]
    DIRECTION OUTPUT ;
    USE SIGNAL ;
    PORT
      LAYER M5 ;
        RECT  110.736 30.156 110.76 30.24 ;
    END
  END xb[28]
  PIN xb[29]
    DIRECTION OUTPUT ;
    USE SIGNAL ;
    PORT
      LAYER M5 ;
        RECT  110.88 30.156 110.904 30.24 ;
    END
  END xb[29]
  PIN xb[2]
    DIRECTION OUTPUT ;
    USE SIGNAL ;
    PORT
      LAYER M5 ;
        RECT  106.992 30.156 107.016 30.24 ;
    END
  END xb[2]
  PIN xb[30]
    DIRECTION OUTPUT ;
    USE SIGNAL ;
    PORT
      LAYER M5 ;
        RECT  111.024 30.156 111.048 30.24 ;
    END
  END xb[30]
  PIN xb[31]
    DIRECTION OUTPUT ;
    USE SIGNAL ;
    PORT
      LAYER M5 ;
        RECT  111.168 30.156 111.192 30.24 ;
    END
  END xb[31]
  PIN xb[32]
    DIRECTION OUTPUT ;
    USE SIGNAL ;
    PORT
      LAYER M5 ;
        RECT  111.312 30.156 111.336 30.24 ;
    END
  END xb[32]
  PIN xb[33]
    DIRECTION OUTPUT ;
    USE SIGNAL ;
    PORT
      LAYER M5 ;
        RECT  111.456 30.156 111.48 30.24 ;
    END
  END xb[33]
  PIN xb[34]
    DIRECTION OUTPUT ;
    USE SIGNAL ;
    PORT
      LAYER M5 ;
        RECT  111.6 30.156 111.624 30.24 ;
    END
  END xb[34]
  PIN xb[35]
    DIRECTION OUTPUT ;
    USE SIGNAL ;
    PORT
      LAYER M5 ;
        RECT  111.744 30.156 111.768 30.24 ;
    END
  END xb[35]
  PIN xb[36]
    DIRECTION OUTPUT ;
    USE SIGNAL ;
    PORT
      LAYER M5 ;
        RECT  111.888 30.156 111.912 30.24 ;
    END
  END xb[36]
  PIN xb[37]
    DIRECTION OUTPUT ;
    USE SIGNAL ;
    PORT
      LAYER M5 ;
        RECT  112.032 30.156 112.056 30.24 ;
    END
  END xb[37]
  PIN xb[38]
    DIRECTION OUTPUT ;
    USE SIGNAL ;
    PORT
      LAYER M5 ;
        RECT  112.176 30.156 112.2 30.24 ;
    END
  END xb[38]
  PIN xb[39]
    DIRECTION OUTPUT ;
    USE SIGNAL ;
    PORT
      LAYER M5 ;
        RECT  112.32 30.156 112.344 30.24 ;
    END
  END xb[39]
  PIN xb[3]
    DIRECTION OUTPUT ;
    USE SIGNAL ;
    PORT
      LAYER M5 ;
        RECT  107.136 30.156 107.16 30.24 ;
    END
  END xb[3]
  PIN xb[40]
    DIRECTION OUTPUT ;
    USE SIGNAL ;
    PORT
      LAYER M5 ;
        RECT  112.464 30.156 112.488 30.24 ;
    END
  END xb[40]
  PIN xb[41]
    DIRECTION OUTPUT ;
    USE SIGNAL ;
    PORT
      LAYER M5 ;
        RECT  112.608 30.156 112.632 30.24 ;
    END
  END xb[41]
  PIN xb[42]
    DIRECTION OUTPUT ;
    USE SIGNAL ;
    PORT
      LAYER M5 ;
        RECT  112.752 30.156 112.776 30.24 ;
    END
  END xb[42]
  PIN xb[43]
    DIRECTION OUTPUT ;
    USE SIGNAL ;
    PORT
      LAYER M5 ;
        RECT  112.896 30.156 112.92 30.24 ;
    END
  END xb[43]
  PIN xb[44]
    DIRECTION OUTPUT ;
    USE SIGNAL ;
    PORT
      LAYER M5 ;
        RECT  113.04 30.156 113.064 30.24 ;
    END
  END xb[44]
  PIN xb[45]
    DIRECTION OUTPUT ;
    USE SIGNAL ;
    PORT
      LAYER M5 ;
        RECT  113.184 30.156 113.208 30.24 ;
    END
  END xb[45]
  PIN xb[46]
    DIRECTION OUTPUT ;
    USE SIGNAL ;
    PORT
      LAYER M5 ;
        RECT  113.328 30.156 113.352 30.24 ;
    END
  END xb[46]
  PIN xb[47]
    DIRECTION OUTPUT ;
    USE SIGNAL ;
    PORT
      LAYER M5 ;
        RECT  113.472 30.156 113.496 30.24 ;
    END
  END xb[47]
  PIN xb[48]
    DIRECTION OUTPUT ;
    USE SIGNAL ;
    PORT
      LAYER M5 ;
        RECT  113.616 30.156 113.64 30.24 ;
    END
  END xb[48]
  PIN xb[49]
    DIRECTION OUTPUT ;
    USE SIGNAL ;
    PORT
      LAYER M5 ;
        RECT  113.76 30.156 113.784 30.24 ;
    END
  END xb[49]
  PIN xb[4]
    DIRECTION OUTPUT ;
    USE SIGNAL ;
    PORT
      LAYER M5 ;
        RECT  107.28 30.156 107.304 30.24 ;
    END
  END xb[4]
  PIN xb[50]
    DIRECTION OUTPUT ;
    USE SIGNAL ;
    PORT
      LAYER M5 ;
        RECT  113.904 30.156 113.928 30.24 ;
    END
  END xb[50]
  PIN xb[51]
    DIRECTION OUTPUT ;
    USE SIGNAL ;
    PORT
      LAYER M5 ;
        RECT  114.048 30.156 114.072 30.24 ;
    END
  END xb[51]
  PIN xb[52]
    DIRECTION OUTPUT ;
    USE SIGNAL ;
    PORT
      LAYER M5 ;
        RECT  114.192 30.156 114.216 30.24 ;
    END
  END xb[52]
  PIN xb[53]
    DIRECTION OUTPUT ;
    USE SIGNAL ;
    PORT
      LAYER M5 ;
        RECT  114.336 30.156 114.36 30.24 ;
    END
  END xb[53]
  PIN xb[54]
    DIRECTION OUTPUT ;
    USE SIGNAL ;
    PORT
      LAYER M5 ;
        RECT  114.48 30.156 114.504 30.24 ;
    END
  END xb[54]
  PIN xb[55]
    DIRECTION OUTPUT ;
    USE SIGNAL ;
    PORT
      LAYER M5 ;
        RECT  114.624 30.156 114.648 30.24 ;
    END
  END xb[55]
  PIN xb[56]
    DIRECTION OUTPUT ;
    USE SIGNAL ;
    PORT
      LAYER M5 ;
        RECT  114.768 30.156 114.792 30.24 ;
    END
  END xb[56]
  PIN xb[57]
    DIRECTION OUTPUT ;
    USE SIGNAL ;
    PORT
      LAYER M5 ;
        RECT  114.912 30.156 114.936 30.24 ;
    END
  END xb[57]
  PIN xb[58]
    DIRECTION OUTPUT ;
    USE SIGNAL ;
    PORT
      LAYER M5 ;
        RECT  115.056 30.156 115.08 30.24 ;
    END
  END xb[58]
  PIN xb[59]
    DIRECTION OUTPUT ;
    USE SIGNAL ;
    PORT
      LAYER M5 ;
        RECT  115.2 30.156 115.224 30.24 ;
    END
  END xb[59]
  PIN xb[5]
    DIRECTION OUTPUT ;
    USE SIGNAL ;
    PORT
      LAYER M5 ;
        RECT  107.424 30.156 107.448 30.24 ;
    END
  END xb[5]
  PIN xb[60]
    DIRECTION OUTPUT ;
    USE SIGNAL ;
    PORT
      LAYER M5 ;
        RECT  115.344 30.156 115.368 30.24 ;
    END
  END xb[60]
  PIN xb[61]
    DIRECTION OUTPUT ;
    USE SIGNAL ;
    PORT
      LAYER M5 ;
        RECT  115.488 30.156 115.512 30.24 ;
    END
  END xb[61]
  PIN xb[62]
    DIRECTION OUTPUT ;
    USE SIGNAL ;
    PORT
      LAYER M5 ;
        RECT  115.632 30.156 115.656 30.24 ;
    END
  END xb[62]
  PIN xb[63]
    DIRECTION OUTPUT ;
    USE SIGNAL ;
    PORT
      LAYER M5 ;
        RECT  115.776 30.156 115.8 30.24 ;
    END
  END xb[63]
  PIN xb[64]
    DIRECTION OUTPUT ;
    USE SIGNAL ;
    PORT
      LAYER M5 ;
        RECT  115.92 30.156 115.944 30.24 ;
    END
  END xb[64]
  PIN xb[65]
    DIRECTION OUTPUT ;
    USE SIGNAL ;
    PORT
      LAYER M5 ;
        RECT  116.064 30.156 116.088 30.24 ;
    END
  END xb[65]
  PIN xb[66]
    DIRECTION OUTPUT ;
    USE SIGNAL ;
    PORT
      LAYER M5 ;
        RECT  116.208 30.156 116.232 30.24 ;
    END
  END xb[66]
  PIN xb[67]
    DIRECTION OUTPUT ;
    USE SIGNAL ;
    PORT
      LAYER M5 ;
        RECT  116.352 30.156 116.376 30.24 ;
    END
  END xb[67]
  PIN xb[68]
    DIRECTION OUTPUT ;
    USE SIGNAL ;
    PORT
      LAYER M5 ;
        RECT  116.496 30.156 116.52 30.24 ;
    END
  END xb[68]
  PIN xb[69]
    DIRECTION OUTPUT ;
    USE SIGNAL ;
    PORT
      LAYER M5 ;
        RECT  116.64 30.156 116.664 30.24 ;
    END
  END xb[69]
  PIN xb[6]
    DIRECTION OUTPUT ;
    USE SIGNAL ;
    PORT
      LAYER M5 ;
        RECT  107.568 30.156 107.592 30.24 ;
    END
  END xb[6]
  PIN xb[70]
    DIRECTION OUTPUT ;
    USE SIGNAL ;
    PORT
      LAYER M5 ;
        RECT  116.784 30.156 116.808 30.24 ;
    END
  END xb[70]
  PIN xb[71]
    DIRECTION OUTPUT ;
    USE SIGNAL ;
    PORT
      LAYER M5 ;
        RECT  116.928 30.156 116.952 30.24 ;
    END
  END xb[71]
  PIN xb[72]
    DIRECTION OUTPUT ;
    USE SIGNAL ;
    PORT
      LAYER M5 ;
        RECT  117.072 30.156 117.096 30.24 ;
    END
  END xb[72]
  PIN xb[73]
    DIRECTION OUTPUT ;
    USE SIGNAL ;
    PORT
      LAYER M5 ;
        RECT  117.216 30.156 117.24 30.24 ;
    END
  END xb[73]
  PIN xb[74]
    DIRECTION OUTPUT ;
    USE SIGNAL ;
    PORT
      LAYER M5 ;
        RECT  117.36 30.156 117.384 30.24 ;
    END
  END xb[74]
  PIN xb[75]
    DIRECTION OUTPUT ;
    USE SIGNAL ;
    PORT
      LAYER M5 ;
        RECT  117.504 30.156 117.528 30.24 ;
    END
  END xb[75]
  PIN xb[76]
    DIRECTION OUTPUT ;
    USE SIGNAL ;
    PORT
      LAYER M5 ;
        RECT  117.648 30.156 117.672 30.24 ;
    END
  END xb[76]
  PIN xb[77]
    DIRECTION OUTPUT ;
    USE SIGNAL ;
    PORT
      LAYER M5 ;
        RECT  117.792 30.156 117.816 30.24 ;
    END
  END xb[77]
  PIN xb[78]
    DIRECTION OUTPUT ;
    USE SIGNAL ;
    PORT
      LAYER M5 ;
        RECT  117.936 30.156 117.96 30.24 ;
    END
  END xb[78]
  PIN xb[79]
    DIRECTION OUTPUT ;
    USE SIGNAL ;
    PORT
      LAYER M5 ;
        RECT  118.08 30.156 118.104 30.24 ;
    END
  END xb[79]
  PIN xb[7]
    DIRECTION OUTPUT ;
    USE SIGNAL ;
    PORT
      LAYER M5 ;
        RECT  107.712 30.156 107.736 30.24 ;
    END
  END xb[7]
  PIN xb[80]
    DIRECTION OUTPUT ;
    USE SIGNAL ;
    PORT
      LAYER M5 ;
        RECT  118.224 30.156 118.248 30.24 ;
    END
  END xb[80]
  PIN xb[81]
    DIRECTION OUTPUT ;
    USE SIGNAL ;
    PORT
      LAYER M5 ;
        RECT  118.368 30.156 118.392 30.24 ;
    END
  END xb[81]
  PIN xb[82]
    DIRECTION OUTPUT ;
    USE SIGNAL ;
    PORT
      LAYER M5 ;
        RECT  118.512 30.156 118.536 30.24 ;
    END
  END xb[82]
  PIN xb[83]
    DIRECTION OUTPUT ;
    USE SIGNAL ;
    PORT
      LAYER M5 ;
        RECT  118.656 30.156 118.68 30.24 ;
    END
  END xb[83]
  PIN xb[84]
    DIRECTION OUTPUT ;
    USE SIGNAL ;
    PORT
      LAYER M5 ;
        RECT  118.8 30.156 118.824 30.24 ;
    END
  END xb[84]
  PIN xb[85]
    DIRECTION OUTPUT ;
    USE SIGNAL ;
    PORT
      LAYER M5 ;
        RECT  118.944 30.156 118.968 30.24 ;
    END
  END xb[85]
  PIN xb[86]
    DIRECTION OUTPUT ;
    USE SIGNAL ;
    PORT
      LAYER M5 ;
        RECT  119.088 30.156 119.112 30.24 ;
    END
  END xb[86]
  PIN xb[87]
    DIRECTION OUTPUT ;
    USE SIGNAL ;
    PORT
      LAYER M5 ;
        RECT  119.232 30.156 119.256 30.24 ;
    END
  END xb[87]
  PIN xb[88]
    DIRECTION OUTPUT ;
    USE SIGNAL ;
    PORT
      LAYER M5 ;
        RECT  119.376 30.156 119.4 30.24 ;
    END
  END xb[88]
  PIN xb[89]
    DIRECTION OUTPUT ;
    USE SIGNAL ;
    PORT
      LAYER M5 ;
        RECT  119.52 30.156 119.544 30.24 ;
    END
  END xb[89]
  PIN xb[8]
    DIRECTION OUTPUT ;
    USE SIGNAL ;
    PORT
      LAYER M5 ;
        RECT  107.856 30.156 107.88 30.24 ;
    END
  END xb[8]
  PIN xb[90]
    DIRECTION OUTPUT ;
    USE SIGNAL ;
    PORT
      LAYER M5 ;
        RECT  119.664 30.156 119.688 30.24 ;
    END
  END xb[90]
  PIN xb[91]
    DIRECTION OUTPUT ;
    USE SIGNAL ;
    PORT
      LAYER M5 ;
        RECT  119.808 30.156 119.832 30.24 ;
    END
  END xb[91]
  PIN xb[92]
    DIRECTION OUTPUT ;
    USE SIGNAL ;
    PORT
      LAYER M5 ;
        RECT  119.952 30.156 119.976 30.24 ;
    END
  END xb[92]
  PIN xb[93]
    DIRECTION OUTPUT ;
    USE SIGNAL ;
    PORT
      LAYER M5 ;
        RECT  120.096 30.156 120.12 30.24 ;
    END
  END xb[93]
  PIN xb[94]
    DIRECTION OUTPUT ;
    USE SIGNAL ;
    PORT
      LAYER M5 ;
        RECT  120.24 30.156 120.264 30.24 ;
    END
  END xb[94]
  PIN xb[95]
    DIRECTION OUTPUT ;
    USE SIGNAL ;
    PORT
      LAYER M5 ;
        RECT  120.384 30.156 120.408 30.24 ;
    END
  END xb[95]
  PIN xb[96]
    DIRECTION OUTPUT ;
    USE SIGNAL ;
    PORT
      LAYER M5 ;
        RECT  120.528 30.156 120.552 30.24 ;
    END
  END xb[96]
  PIN xb[97]
    DIRECTION OUTPUT ;
    USE SIGNAL ;
    PORT
      LAYER M5 ;
        RECT  120.672 30.156 120.696 30.24 ;
    END
  END xb[97]
  PIN xb[98]
    DIRECTION OUTPUT ;
    USE SIGNAL ;
    PORT
      LAYER M5 ;
        RECT  120.816 30.156 120.84 30.24 ;
    END
  END xb[98]
  PIN xb[99]
    DIRECTION OUTPUT ;
    USE SIGNAL ;
    PORT
      LAYER M5 ;
        RECT  120.96 30.156 120.984 30.24 ;
    END
  END xb[99]
  PIN xb[9]
    DIRECTION OUTPUT ;
    USE SIGNAL ;
    PORT
      LAYER M5 ;
        RECT  108 30.156 108.024 30.24 ;
    END
  END xb[9]
  PIN xbi[0]
    DIRECTION INPUT ;
    USE SIGNAL ;
    PORT
      LAYER M5 ;
        RECT  92.16 0 92.184 0.084 ;
    END
  END xbi[0]
  PIN xbi[100]
    DIRECTION INPUT ;
    USE SIGNAL ;
    PORT
      LAYER M5 ;
        RECT  106.56 0 106.584 0.084 ;
    END
  END xbi[100]
  PIN xbi[101]
    DIRECTION INPUT ;
    USE SIGNAL ;
    PORT
      LAYER M5 ;
        RECT  106.704 0 106.728 0.084 ;
    END
  END xbi[101]
  PIN xbi[102]
    DIRECTION INPUT ;
    USE SIGNAL ;
    PORT
      LAYER M5 ;
        RECT  106.848 0 106.872 0.084 ;
    END
  END xbi[102]
  PIN xbi[103]
    DIRECTION INPUT ;
    USE SIGNAL ;
    PORT
      LAYER M5 ;
        RECT  106.992 0 107.016 0.084 ;
    END
  END xbi[103]
  PIN xbi[104]
    DIRECTION INPUT ;
    USE SIGNAL ;
    PORT
      LAYER M5 ;
        RECT  107.136 0 107.16 0.084 ;
    END
  END xbi[104]
  PIN xbi[105]
    DIRECTION INPUT ;
    USE SIGNAL ;
    PORT
      LAYER M5 ;
        RECT  107.28 0 107.304 0.084 ;
    END
  END xbi[105]
  PIN xbi[106]
    DIRECTION INPUT ;
    USE SIGNAL ;
    PORT
      LAYER M5 ;
        RECT  107.424 0 107.448 0.084 ;
    END
  END xbi[106]
  PIN xbi[107]
    DIRECTION INPUT ;
    USE SIGNAL ;
    PORT
      LAYER M5 ;
        RECT  107.568 0 107.592 0.084 ;
    END
  END xbi[107]
  PIN xbi[108]
    DIRECTION INPUT ;
    USE SIGNAL ;
    PORT
      LAYER M5 ;
        RECT  107.712 0 107.736 0.084 ;
    END
  END xbi[108]
  PIN xbi[109]
    DIRECTION INPUT ;
    USE SIGNAL ;
    PORT
      LAYER M5 ;
        RECT  107.856 0 107.88 0.084 ;
    END
  END xbi[109]
  PIN xbi[10]
    DIRECTION INPUT ;
    USE SIGNAL ;
    PORT
      LAYER M5 ;
        RECT  93.6 0 93.624 0.084 ;
    END
  END xbi[10]
  PIN xbi[110]
    DIRECTION INPUT ;
    USE SIGNAL ;
    PORT
      LAYER M5 ;
        RECT  108 0 108.024 0.084 ;
    END
  END xbi[110]
  PIN xbi[111]
    DIRECTION INPUT ;
    USE SIGNAL ;
    PORT
      LAYER M5 ;
        RECT  108.144 0 108.168 0.084 ;
    END
  END xbi[111]
  PIN xbi[112]
    DIRECTION INPUT ;
    USE SIGNAL ;
    PORT
      LAYER M5 ;
        RECT  108.288 0 108.312 0.084 ;
    END
  END xbi[112]
  PIN xbi[113]
    DIRECTION INPUT ;
    USE SIGNAL ;
    PORT
      LAYER M5 ;
        RECT  108.432 0 108.456 0.084 ;
    END
  END xbi[113]
  PIN xbi[114]
    DIRECTION INPUT ;
    USE SIGNAL ;
    PORT
      LAYER M5 ;
        RECT  108.576 0 108.6 0.084 ;
    END
  END xbi[114]
  PIN xbi[115]
    DIRECTION INPUT ;
    USE SIGNAL ;
    PORT
      LAYER M5 ;
        RECT  108.72 0 108.744 0.084 ;
    END
  END xbi[115]
  PIN xbi[116]
    DIRECTION INPUT ;
    USE SIGNAL ;
    PORT
      LAYER M5 ;
        RECT  108.864 0 108.888 0.084 ;
    END
  END xbi[116]
  PIN xbi[117]
    DIRECTION INPUT ;
    USE SIGNAL ;
    PORT
      LAYER M5 ;
        RECT  109.008 0 109.032 0.084 ;
    END
  END xbi[117]
  PIN xbi[118]
    DIRECTION INPUT ;
    USE SIGNAL ;
    PORT
      LAYER M5 ;
        RECT  109.152 0 109.176 0.084 ;
    END
  END xbi[118]
  PIN xbi[119]
    DIRECTION INPUT ;
    USE SIGNAL ;
    PORT
      LAYER M5 ;
        RECT  109.296 0 109.32 0.084 ;
    END
  END xbi[119]
  PIN xbi[11]
    DIRECTION INPUT ;
    USE SIGNAL ;
    PORT
      LAYER M5 ;
        RECT  93.744 0 93.768 0.084 ;
    END
  END xbi[11]
  PIN xbi[120]
    DIRECTION INPUT ;
    USE SIGNAL ;
    PORT
      LAYER M5 ;
        RECT  109.44 0 109.464 0.084 ;
    END
  END xbi[120]
  PIN xbi[121]
    DIRECTION INPUT ;
    USE SIGNAL ;
    PORT
      LAYER M5 ;
        RECT  109.584 0 109.608 0.084 ;
    END
  END xbi[121]
  PIN xbi[122]
    DIRECTION INPUT ;
    USE SIGNAL ;
    PORT
      LAYER M5 ;
        RECT  109.728 0 109.752 0.084 ;
    END
  END xbi[122]
  PIN xbi[123]
    DIRECTION INPUT ;
    USE SIGNAL ;
    PORT
      LAYER M5 ;
        RECT  109.872 0 109.896 0.084 ;
    END
  END xbi[123]
  PIN xbi[124]
    DIRECTION INPUT ;
    USE SIGNAL ;
    PORT
      LAYER M5 ;
        RECT  110.016 0 110.04 0.084 ;
    END
  END xbi[124]
  PIN xbi[125]
    DIRECTION INPUT ;
    USE SIGNAL ;
    PORT
      LAYER M5 ;
        RECT  110.16 0 110.184 0.084 ;
    END
  END xbi[125]
  PIN xbi[126]
    DIRECTION INPUT ;
    USE SIGNAL ;
    PORT
      LAYER M5 ;
        RECT  110.304 0 110.328 0.084 ;
    END
  END xbi[126]
  PIN xbi[127]
    DIRECTION INPUT ;
    USE SIGNAL ;
    PORT
      LAYER M5 ;
        RECT  110.448 0 110.472 0.084 ;
    END
  END xbi[127]
  PIN xbi[128]
    DIRECTION INPUT ;
    USE SIGNAL ;
    PORT
      LAYER M5 ;
        RECT  110.592 0 110.616 0.084 ;
    END
  END xbi[128]
  PIN xbi[129]
    DIRECTION INPUT ;
    USE SIGNAL ;
    PORT
      LAYER M5 ;
        RECT  110.736 0 110.76 0.084 ;
    END
  END xbi[129]
  PIN xbi[12]
    DIRECTION INPUT ;
    USE SIGNAL ;
    PORT
      LAYER M5 ;
        RECT  93.888 0 93.912 0.084 ;
    END
  END xbi[12]
  PIN xbi[130]
    DIRECTION INPUT ;
    USE SIGNAL ;
    PORT
      LAYER M5 ;
        RECT  110.88 0 110.904 0.084 ;
    END
  END xbi[130]
  PIN xbi[131]
    DIRECTION INPUT ;
    USE SIGNAL ;
    PORT
      LAYER M5 ;
        RECT  111.024 0 111.048 0.084 ;
    END
  END xbi[131]
  PIN xbi[132]
    DIRECTION INPUT ;
    USE SIGNAL ;
    PORT
      LAYER M5 ;
        RECT  111.168 0 111.192 0.084 ;
    END
  END xbi[132]
  PIN xbi[133]
    DIRECTION INPUT ;
    USE SIGNAL ;
    PORT
      LAYER M5 ;
        RECT  111.312 0 111.336 0.084 ;
    END
  END xbi[133]
  PIN xbi[134]
    DIRECTION INPUT ;
    USE SIGNAL ;
    PORT
      LAYER M5 ;
        RECT  111.456 0 111.48 0.084 ;
    END
  END xbi[134]
  PIN xbi[135]
    DIRECTION INPUT ;
    USE SIGNAL ;
    PORT
      LAYER M5 ;
        RECT  111.6 0 111.624 0.084 ;
    END
  END xbi[135]
  PIN xbi[136]
    DIRECTION INPUT ;
    USE SIGNAL ;
    PORT
      LAYER M5 ;
        RECT  111.744 0 111.768 0.084 ;
    END
  END xbi[136]
  PIN xbi[137]
    DIRECTION INPUT ;
    USE SIGNAL ;
    PORT
      LAYER M5 ;
        RECT  111.888 0 111.912 0.084 ;
    END
  END xbi[137]
  PIN xbi[138]
    DIRECTION INPUT ;
    USE SIGNAL ;
    PORT
      LAYER M5 ;
        RECT  112.032 0 112.056 0.084 ;
    END
  END xbi[138]
  PIN xbi[139]
    DIRECTION INPUT ;
    USE SIGNAL ;
    PORT
      LAYER M5 ;
        RECT  112.176 0 112.2 0.084 ;
    END
  END xbi[139]
  PIN xbi[13]
    DIRECTION INPUT ;
    USE SIGNAL ;
    PORT
      LAYER M5 ;
        RECT  94.032 0 94.056 0.084 ;
    END
  END xbi[13]
  PIN xbi[140]
    DIRECTION INPUT ;
    USE SIGNAL ;
    PORT
      LAYER M5 ;
        RECT  112.32 0 112.344 0.084 ;
    END
  END xbi[140]
  PIN xbi[141]
    DIRECTION INPUT ;
    USE SIGNAL ;
    PORT
      LAYER M5 ;
        RECT  112.464 0 112.488 0.084 ;
    END
  END xbi[141]
  PIN xbi[142]
    DIRECTION INPUT ;
    USE SIGNAL ;
    PORT
      LAYER M5 ;
        RECT  112.608 0 112.632 0.084 ;
    END
  END xbi[142]
  PIN xbi[143]
    DIRECTION INPUT ;
    USE SIGNAL ;
    PORT
      LAYER M5 ;
        RECT  112.752 0 112.776 0.084 ;
    END
  END xbi[143]
  PIN xbi[144]
    DIRECTION INPUT ;
    USE SIGNAL ;
    PORT
      LAYER M5 ;
        RECT  112.896 0 112.92 0.084 ;
    END
  END xbi[144]
  PIN xbi[145]
    DIRECTION INPUT ;
    USE SIGNAL ;
    PORT
      LAYER M5 ;
        RECT  113.04 0 113.064 0.084 ;
    END
  END xbi[145]
  PIN xbi[146]
    DIRECTION INPUT ;
    USE SIGNAL ;
    PORT
      LAYER M5 ;
        RECT  113.184 0 113.208 0.084 ;
    END
  END xbi[146]
  PIN xbi[147]
    DIRECTION INPUT ;
    USE SIGNAL ;
    PORT
      LAYER M5 ;
        RECT  113.328 0 113.352 0.084 ;
    END
  END xbi[147]
  PIN xbi[148]
    DIRECTION INPUT ;
    USE SIGNAL ;
    PORT
      LAYER M5 ;
        RECT  113.472 0 113.496 0.084 ;
    END
  END xbi[148]
  PIN xbi[149]
    DIRECTION INPUT ;
    USE SIGNAL ;
    PORT
      LAYER M5 ;
        RECT  113.616 0 113.64 0.084 ;
    END
  END xbi[149]
  PIN xbi[14]
    DIRECTION INPUT ;
    USE SIGNAL ;
    PORT
      LAYER M5 ;
        RECT  94.176 0 94.2 0.084 ;
    END
  END xbi[14]
  PIN xbi[150]
    DIRECTION INPUT ;
    USE SIGNAL ;
    PORT
      LAYER M5 ;
        RECT  113.76 0 113.784 0.084 ;
    END
  END xbi[150]
  PIN xbi[151]
    DIRECTION INPUT ;
    USE SIGNAL ;
    PORT
      LAYER M5 ;
        RECT  113.904 0 113.928 0.084 ;
    END
  END xbi[151]
  PIN xbi[152]
    DIRECTION INPUT ;
    USE SIGNAL ;
    PORT
      LAYER M5 ;
        RECT  114.048 0 114.072 0.084 ;
    END
  END xbi[152]
  PIN xbi[153]
    DIRECTION INPUT ;
    USE SIGNAL ;
    PORT
      LAYER M5 ;
        RECT  114.192 0 114.216 0.084 ;
    END
  END xbi[153]
  PIN xbi[154]
    DIRECTION INPUT ;
    USE SIGNAL ;
    PORT
      LAYER M5 ;
        RECT  114.336 0 114.36 0.084 ;
    END
  END xbi[154]
  PIN xbi[155]
    DIRECTION INPUT ;
    USE SIGNAL ;
    PORT
      LAYER M5 ;
        RECT  114.48 0 114.504 0.084 ;
    END
  END xbi[155]
  PIN xbi[156]
    DIRECTION INPUT ;
    USE SIGNAL ;
    PORT
      LAYER M5 ;
        RECT  114.624 0 114.648 0.084 ;
    END
  END xbi[156]
  PIN xbi[157]
    DIRECTION INPUT ;
    USE SIGNAL ;
    PORT
      LAYER M5 ;
        RECT  114.768 0 114.792 0.084 ;
    END
  END xbi[157]
  PIN xbi[158]
    DIRECTION INPUT ;
    USE SIGNAL ;
    PORT
      LAYER M5 ;
        RECT  114.912 0 114.936 0.084 ;
    END
  END xbi[158]
  PIN xbi[159]
    DIRECTION INPUT ;
    USE SIGNAL ;
    PORT
      LAYER M5 ;
        RECT  115.056 0 115.08 0.084 ;
    END
  END xbi[159]
  PIN xbi[15]
    DIRECTION INPUT ;
    USE SIGNAL ;
    PORT
      LAYER M5 ;
        RECT  94.32 0 94.344 0.084 ;
    END
  END xbi[15]
  PIN xbi[160]
    DIRECTION INPUT ;
    USE SIGNAL ;
    PORT
      LAYER M5 ;
        RECT  115.2 0 115.224 0.084 ;
    END
  END xbi[160]
  PIN xbi[161]
    DIRECTION INPUT ;
    USE SIGNAL ;
    PORT
      LAYER M5 ;
        RECT  115.344 0 115.368 0.084 ;
    END
  END xbi[161]
  PIN xbi[162]
    DIRECTION INPUT ;
    USE SIGNAL ;
    PORT
      LAYER M5 ;
        RECT  115.488 0 115.512 0.084 ;
    END
  END xbi[162]
  PIN xbi[163]
    DIRECTION INPUT ;
    USE SIGNAL ;
    PORT
      LAYER M5 ;
        RECT  115.632 0 115.656 0.084 ;
    END
  END xbi[163]
  PIN xbi[164]
    DIRECTION INPUT ;
    USE SIGNAL ;
    PORT
      LAYER M5 ;
        RECT  115.776 0 115.8 0.084 ;
    END
  END xbi[164]
  PIN xbi[165]
    DIRECTION INPUT ;
    USE SIGNAL ;
    PORT
      LAYER M5 ;
        RECT  115.92 0 115.944 0.084 ;
    END
  END xbi[165]
  PIN xbi[166]
    DIRECTION INPUT ;
    USE SIGNAL ;
    PORT
      LAYER M5 ;
        RECT  116.064 0 116.088 0.084 ;
    END
  END xbi[166]
  PIN xbi[167]
    DIRECTION INPUT ;
    USE SIGNAL ;
    PORT
      LAYER M5 ;
        RECT  116.208 0 116.232 0.084 ;
    END
  END xbi[167]
  PIN xbi[168]
    DIRECTION INPUT ;
    USE SIGNAL ;
    PORT
      LAYER M5 ;
        RECT  116.352 0 116.376 0.084 ;
    END
  END xbi[168]
  PIN xbi[169]
    DIRECTION INPUT ;
    USE SIGNAL ;
    PORT
      LAYER M5 ;
        RECT  116.496 0 116.52 0.084 ;
    END
  END xbi[169]
  PIN xbi[16]
    DIRECTION INPUT ;
    USE SIGNAL ;
    PORT
      LAYER M5 ;
        RECT  94.464 0 94.488 0.084 ;
    END
  END xbi[16]
  PIN xbi[170]
    DIRECTION INPUT ;
    USE SIGNAL ;
    PORT
      LAYER M5 ;
        RECT  116.64 0 116.664 0.084 ;
    END
  END xbi[170]
  PIN xbi[171]
    DIRECTION INPUT ;
    USE SIGNAL ;
    PORT
      LAYER M5 ;
        RECT  116.784 0 116.808 0.084 ;
    END
  END xbi[171]
  PIN xbi[172]
    DIRECTION INPUT ;
    USE SIGNAL ;
    PORT
      LAYER M5 ;
        RECT  116.928 0 116.952 0.084 ;
    END
  END xbi[172]
  PIN xbi[173]
    DIRECTION INPUT ;
    USE SIGNAL ;
    PORT
      LAYER M5 ;
        RECT  117.072 0 117.096 0.084 ;
    END
  END xbi[173]
  PIN xbi[174]
    DIRECTION INPUT ;
    USE SIGNAL ;
    PORT
      LAYER M5 ;
        RECT  117.216 0 117.24 0.084 ;
    END
  END xbi[174]
  PIN xbi[175]
    DIRECTION INPUT ;
    USE SIGNAL ;
    PORT
      LAYER M5 ;
        RECT  117.36 0 117.384 0.084 ;
    END
  END xbi[175]
  PIN xbi[176]
    DIRECTION INPUT ;
    USE SIGNAL ;
    PORT
      LAYER M5 ;
        RECT  117.504 0 117.528 0.084 ;
    END
  END xbi[176]
  PIN xbi[177]
    DIRECTION INPUT ;
    USE SIGNAL ;
    PORT
      LAYER M5 ;
        RECT  117.648 0 117.672 0.084 ;
    END
  END xbi[177]
  PIN xbi[178]
    DIRECTION INPUT ;
    USE SIGNAL ;
    PORT
      LAYER M5 ;
        RECT  117.792 0 117.816 0.084 ;
    END
  END xbi[178]
  PIN xbi[179]
    DIRECTION INPUT ;
    USE SIGNAL ;
    PORT
      LAYER M5 ;
        RECT  117.936 0 117.96 0.084 ;
    END
  END xbi[179]
  PIN xbi[17]
    DIRECTION INPUT ;
    USE SIGNAL ;
    PORT
      LAYER M5 ;
        RECT  94.608 0 94.632 0.084 ;
    END
  END xbi[17]
  PIN xbi[180]
    DIRECTION INPUT ;
    USE SIGNAL ;
    PORT
      LAYER M5 ;
        RECT  118.08 0 118.104 0.084 ;
    END
  END xbi[180]
  PIN xbi[181]
    DIRECTION INPUT ;
    USE SIGNAL ;
    PORT
      LAYER M5 ;
        RECT  118.224 0 118.248 0.084 ;
    END
  END xbi[181]
  PIN xbi[182]
    DIRECTION INPUT ;
    USE SIGNAL ;
    PORT
      LAYER M5 ;
        RECT  118.368 0 118.392 0.084 ;
    END
  END xbi[182]
  PIN xbi[183]
    DIRECTION INPUT ;
    USE SIGNAL ;
    PORT
      LAYER M5 ;
        RECT  118.512 0 118.536 0.084 ;
    END
  END xbi[183]
  PIN xbi[184]
    DIRECTION INPUT ;
    USE SIGNAL ;
    PORT
      LAYER M5 ;
        RECT  118.656 0 118.68 0.084 ;
    END
  END xbi[184]
  PIN xbi[185]
    DIRECTION INPUT ;
    USE SIGNAL ;
    PORT
      LAYER M5 ;
        RECT  118.8 0 118.824 0.084 ;
    END
  END xbi[185]
  PIN xbi[186]
    DIRECTION INPUT ;
    USE SIGNAL ;
    PORT
      LAYER M5 ;
        RECT  118.944 0 118.968 0.084 ;
    END
  END xbi[186]
  PIN xbi[187]
    DIRECTION INPUT ;
    USE SIGNAL ;
    PORT
      LAYER M5 ;
        RECT  119.088 0 119.112 0.084 ;
    END
  END xbi[187]
  PIN xbi[188]
    DIRECTION INPUT ;
    USE SIGNAL ;
    PORT
      LAYER M5 ;
        RECT  119.232 0 119.256 0.084 ;
    END
  END xbi[188]
  PIN xbi[189]
    DIRECTION INPUT ;
    USE SIGNAL ;
    PORT
      LAYER M5 ;
        RECT  119.376 0 119.4 0.084 ;
    END
  END xbi[189]
  PIN xbi[18]
    DIRECTION INPUT ;
    USE SIGNAL ;
    PORT
      LAYER M5 ;
        RECT  94.752 0 94.776 0.084 ;
    END
  END xbi[18]
  PIN xbi[190]
    DIRECTION INPUT ;
    USE SIGNAL ;
    PORT
      LAYER M5 ;
        RECT  119.52 0 119.544 0.084 ;
    END
  END xbi[190]
  PIN xbi[191]
    DIRECTION INPUT ;
    USE SIGNAL ;
    PORT
      LAYER M5 ;
        RECT  119.664 0 119.688 0.084 ;
    END
  END xbi[191]
  PIN xbi[192]
    DIRECTION INPUT ;
    USE SIGNAL ;
    PORT
      LAYER M5 ;
        RECT  119.808 0 119.832 0.084 ;
    END
  END xbi[192]
  PIN xbi[193]
    DIRECTION INPUT ;
    USE SIGNAL ;
    PORT
      LAYER M5 ;
        RECT  119.952 0 119.976 0.084 ;
    END
  END xbi[193]
  PIN xbi[194]
    DIRECTION INPUT ;
    USE SIGNAL ;
    PORT
      LAYER M5 ;
        RECT  120.096 0 120.12 0.084 ;
    END
  END xbi[194]
  PIN xbi[195]
    DIRECTION INPUT ;
    USE SIGNAL ;
    PORT
      LAYER M5 ;
        RECT  120.24 0 120.264 0.084 ;
    END
  END xbi[195]
  PIN xbi[196]
    DIRECTION INPUT ;
    USE SIGNAL ;
    PORT
      LAYER M5 ;
        RECT  120.384 0 120.408 0.084 ;
    END
  END xbi[196]
  PIN xbi[197]
    DIRECTION INPUT ;
    USE SIGNAL ;
    PORT
      LAYER M5 ;
        RECT  120.528 0 120.552 0.084 ;
    END
  END xbi[197]
  PIN xbi[198]
    DIRECTION INPUT ;
    USE SIGNAL ;
    PORT
      LAYER M5 ;
        RECT  120.672 0 120.696 0.084 ;
    END
  END xbi[198]
  PIN xbi[199]
    DIRECTION INPUT ;
    USE SIGNAL ;
    PORT
      LAYER M5 ;
        RECT  120.816 0 120.84 0.084 ;
    END
  END xbi[199]
  PIN xbi[19]
    DIRECTION INPUT ;
    USE SIGNAL ;
    PORT
      LAYER M5 ;
        RECT  94.896 0 94.92 0.084 ;
    END
  END xbi[19]
  PIN xbi[1]
    DIRECTION INPUT ;
    USE SIGNAL ;
    PORT
      LAYER M5 ;
        RECT  92.304 0 92.328 0.084 ;
    END
  END xbi[1]
  PIN xbi[200]
    DIRECTION INPUT ;
    USE SIGNAL ;
    PORT
      LAYER M5 ;
        RECT  120.96 0 120.984 0.084 ;
    END
  END xbi[200]
  PIN xbi[201]
    DIRECTION INPUT ;
    USE SIGNAL ;
    PORT
      LAYER M5 ;
        RECT  121.104 0 121.128 0.084 ;
    END
  END xbi[201]
  PIN xbi[202]
    DIRECTION INPUT ;
    USE SIGNAL ;
    PORT
      LAYER M5 ;
        RECT  121.248 0 121.272 0.084 ;
    END
  END xbi[202]
  PIN xbi[203]
    DIRECTION INPUT ;
    USE SIGNAL ;
    PORT
      LAYER M5 ;
        RECT  121.392 0 121.416 0.084 ;
    END
  END xbi[203]
  PIN xbi[204]
    DIRECTION INPUT ;
    USE SIGNAL ;
    PORT
      LAYER M5 ;
        RECT  121.536 0 121.56 0.084 ;
    END
  END xbi[204]
  PIN xbi[205]
    DIRECTION INPUT ;
    USE SIGNAL ;
    PORT
      LAYER M5 ;
        RECT  121.68 0 121.704 0.084 ;
    END
  END xbi[205]
  PIN xbi[206]
    DIRECTION INPUT ;
    USE SIGNAL ;
    PORT
      LAYER M5 ;
        RECT  121.824 0 121.848 0.084 ;
    END
  END xbi[206]
  PIN xbi[207]
    DIRECTION INPUT ;
    USE SIGNAL ;
    PORT
      LAYER M5 ;
        RECT  121.968 0 121.992 0.084 ;
    END
  END xbi[207]
  PIN xbi[208]
    DIRECTION INPUT ;
    USE SIGNAL ;
    PORT
      LAYER M5 ;
        RECT  122.112 0 122.136 0.084 ;
    END
  END xbi[208]
  PIN xbi[209]
    DIRECTION INPUT ;
    USE SIGNAL ;
    PORT
      LAYER M5 ;
        RECT  122.256 0 122.28 0.084 ;
    END
  END xbi[209]
  PIN xbi[20]
    DIRECTION INPUT ;
    USE SIGNAL ;
    PORT
      LAYER M5 ;
        RECT  95.04 0 95.064 0.084 ;
    END
  END xbi[20]
  PIN xbi[210]
    DIRECTION INPUT ;
    USE SIGNAL ;
    PORT
      LAYER M5 ;
        RECT  122.4 0 122.424 0.084 ;
    END
  END xbi[210]
  PIN xbi[211]
    DIRECTION INPUT ;
    USE SIGNAL ;
    PORT
      LAYER M5 ;
        RECT  122.544 0 122.568 0.084 ;
    END
  END xbi[211]
  PIN xbi[212]
    DIRECTION INPUT ;
    USE SIGNAL ;
    PORT
      LAYER M5 ;
        RECT  122.688 0 122.712 0.084 ;
    END
  END xbi[212]
  PIN xbi[213]
    DIRECTION INPUT ;
    USE SIGNAL ;
    PORT
      LAYER M5 ;
        RECT  122.832 0 122.856 0.084 ;
    END
  END xbi[213]
  PIN xbi[214]
    DIRECTION INPUT ;
    USE SIGNAL ;
    PORT
      LAYER M5 ;
        RECT  122.976 0 123 0.084 ;
    END
  END xbi[214]
  PIN xbi[215]
    DIRECTION INPUT ;
    USE SIGNAL ;
    PORT
      LAYER M5 ;
        RECT  123.12 0 123.144 0.084 ;
    END
  END xbi[215]
  PIN xbi[216]
    DIRECTION INPUT ;
    USE SIGNAL ;
    PORT
      LAYER M5 ;
        RECT  123.264 0 123.288 0.084 ;
    END
  END xbi[216]
  PIN xbi[217]
    DIRECTION INPUT ;
    USE SIGNAL ;
    PORT
      LAYER M5 ;
        RECT  123.408 0 123.432 0.084 ;
    END
  END xbi[217]
  PIN xbi[218]
    DIRECTION INPUT ;
    USE SIGNAL ;
    PORT
      LAYER M5 ;
        RECT  123.552 0 123.576 0.084 ;
    END
  END xbi[218]
  PIN xbi[219]
    DIRECTION INPUT ;
    USE SIGNAL ;
    PORT
      LAYER M5 ;
        RECT  123.696 0 123.72 0.084 ;
    END
  END xbi[219]
  PIN xbi[21]
    DIRECTION INPUT ;
    USE SIGNAL ;
    PORT
      LAYER M5 ;
        RECT  95.184 0 95.208 0.084 ;
    END
  END xbi[21]
  PIN xbi[220]
    DIRECTION INPUT ;
    USE SIGNAL ;
    PORT
      LAYER M5 ;
        RECT  123.84 0 123.864 0.084 ;
    END
  END xbi[220]
  PIN xbi[221]
    DIRECTION INPUT ;
    USE SIGNAL ;
    PORT
      LAYER M5 ;
        RECT  123.984 0 124.008 0.084 ;
    END
  END xbi[221]
  PIN xbi[222]
    DIRECTION INPUT ;
    USE SIGNAL ;
    PORT
      LAYER M5 ;
        RECT  124.128 0 124.152 0.084 ;
    END
  END xbi[222]
  PIN xbi[223]
    DIRECTION INPUT ;
    USE SIGNAL ;
    PORT
      LAYER M5 ;
        RECT  124.272 0 124.296 0.084 ;
    END
  END xbi[223]
  PIN xbi[224]
    DIRECTION INPUT ;
    USE SIGNAL ;
    PORT
      LAYER M5 ;
        RECT  124.416 0 124.44 0.084 ;
    END
  END xbi[224]
  PIN xbi[225]
    DIRECTION INPUT ;
    USE SIGNAL ;
    PORT
      LAYER M5 ;
        RECT  124.56 0 124.584 0.084 ;
    END
  END xbi[225]
  PIN xbi[226]
    DIRECTION INPUT ;
    USE SIGNAL ;
    PORT
      LAYER M5 ;
        RECT  124.704 0 124.728 0.084 ;
    END
  END xbi[226]
  PIN xbi[227]
    DIRECTION INPUT ;
    USE SIGNAL ;
    PORT
      LAYER M5 ;
        RECT  124.848 0 124.872 0.084 ;
    END
  END xbi[227]
  PIN xbi[228]
    DIRECTION INPUT ;
    USE SIGNAL ;
    PORT
      LAYER M5 ;
        RECT  124.992 0 125.016 0.084 ;
    END
  END xbi[228]
  PIN xbi[229]
    DIRECTION INPUT ;
    USE SIGNAL ;
    PORT
      LAYER M5 ;
        RECT  125.136 0 125.16 0.084 ;
    END
  END xbi[229]
  PIN xbi[22]
    DIRECTION INPUT ;
    USE SIGNAL ;
    PORT
      LAYER M5 ;
        RECT  95.328 0 95.352 0.084 ;
    END
  END xbi[22]
  PIN xbi[230]
    DIRECTION INPUT ;
    USE SIGNAL ;
    PORT
      LAYER M5 ;
        RECT  125.28 0 125.304 0.084 ;
    END
  END xbi[230]
  PIN xbi[231]
    DIRECTION INPUT ;
    USE SIGNAL ;
    PORT
      LAYER M5 ;
        RECT  125.424 0 125.448 0.084 ;
    END
  END xbi[231]
  PIN xbi[232]
    DIRECTION INPUT ;
    USE SIGNAL ;
    PORT
      LAYER M5 ;
        RECT  125.568 0 125.592 0.084 ;
    END
  END xbi[232]
  PIN xbi[233]
    DIRECTION INPUT ;
    USE SIGNAL ;
    PORT
      LAYER M5 ;
        RECT  125.712 0 125.736 0.084 ;
    END
  END xbi[233]
  PIN xbi[234]
    DIRECTION INPUT ;
    USE SIGNAL ;
    PORT
      LAYER M5 ;
        RECT  125.856 0 125.88 0.084 ;
    END
  END xbi[234]
  PIN xbi[235]
    DIRECTION INPUT ;
    USE SIGNAL ;
    PORT
      LAYER M5 ;
        RECT  126 0 126.024 0.084 ;
    END
  END xbi[235]
  PIN xbi[236]
    DIRECTION INPUT ;
    USE SIGNAL ;
    PORT
      LAYER M5 ;
        RECT  126.144 0 126.168 0.084 ;
    END
  END xbi[236]
  PIN xbi[237]
    DIRECTION INPUT ;
    USE SIGNAL ;
    PORT
      LAYER M5 ;
        RECT  126.288 0 126.312 0.084 ;
    END
  END xbi[237]
  PIN xbi[238]
    DIRECTION INPUT ;
    USE SIGNAL ;
    PORT
      LAYER M5 ;
        RECT  126.432 0 126.456 0.084 ;
    END
  END xbi[238]
  PIN xbi[239]
    DIRECTION INPUT ;
    USE SIGNAL ;
    PORT
      LAYER M5 ;
        RECT  126.576 0 126.6 0.084 ;
    END
  END xbi[239]
  PIN xbi[23]
    DIRECTION INPUT ;
    USE SIGNAL ;
    PORT
      LAYER M5 ;
        RECT  95.472 0 95.496 0.084 ;
    END
  END xbi[23]
  PIN xbi[240]
    DIRECTION INPUT ;
    USE SIGNAL ;
    PORT
      LAYER M5 ;
        RECT  126.72 0 126.744 0.084 ;
    END
  END xbi[240]
  PIN xbi[241]
    DIRECTION INPUT ;
    USE SIGNAL ;
    PORT
      LAYER M5 ;
        RECT  126.864 0 126.888 0.084 ;
    END
  END xbi[241]
  PIN xbi[242]
    DIRECTION INPUT ;
    USE SIGNAL ;
    PORT
      LAYER M5 ;
        RECT  127.008 0 127.032 0.084 ;
    END
  END xbi[242]
  PIN xbi[243]
    DIRECTION INPUT ;
    USE SIGNAL ;
    PORT
      LAYER M5 ;
        RECT  127.152 0 127.176 0.084 ;
    END
  END xbi[243]
  PIN xbi[244]
    DIRECTION INPUT ;
    USE SIGNAL ;
    PORT
      LAYER M5 ;
        RECT  127.296 0 127.32 0.084 ;
    END
  END xbi[244]
  PIN xbi[245]
    DIRECTION INPUT ;
    USE SIGNAL ;
    PORT
      LAYER M5 ;
        RECT  127.44 0 127.464 0.084 ;
    END
  END xbi[245]
  PIN xbi[246]
    DIRECTION INPUT ;
    USE SIGNAL ;
    PORT
      LAYER M5 ;
        RECT  127.584 0 127.608 0.084 ;
    END
  END xbi[246]
  PIN xbi[247]
    DIRECTION INPUT ;
    USE SIGNAL ;
    PORT
      LAYER M5 ;
        RECT  127.728 0 127.752 0.084 ;
    END
  END xbi[247]
  PIN xbi[248]
    DIRECTION INPUT ;
    USE SIGNAL ;
    PORT
      LAYER M5 ;
        RECT  127.872 0 127.896 0.084 ;
    END
  END xbi[248]
  PIN xbi[249]
    DIRECTION INPUT ;
    USE SIGNAL ;
    PORT
      LAYER M5 ;
        RECT  128.016 0 128.04 0.084 ;
    END
  END xbi[249]
  PIN xbi[24]
    DIRECTION INPUT ;
    USE SIGNAL ;
    PORT
      LAYER M5 ;
        RECT  95.616 0 95.64 0.084 ;
    END
  END xbi[24]
  PIN xbi[250]
    DIRECTION INPUT ;
    USE SIGNAL ;
    PORT
      LAYER M5 ;
        RECT  128.16 0 128.184 0.084 ;
    END
  END xbi[250]
  PIN xbi[251]
    DIRECTION INPUT ;
    USE SIGNAL ;
    PORT
      LAYER M5 ;
        RECT  128.304 0 128.328 0.084 ;
    END
  END xbi[251]
  PIN xbi[252]
    DIRECTION INPUT ;
    USE SIGNAL ;
    PORT
      LAYER M5 ;
        RECT  128.448 0 128.472 0.084 ;
    END
  END xbi[252]
  PIN xbi[253]
    DIRECTION INPUT ;
    USE SIGNAL ;
    PORT
      LAYER M5 ;
        RECT  128.592 0 128.616 0.084 ;
    END
  END xbi[253]
  PIN xbi[254]
    DIRECTION INPUT ;
    USE SIGNAL ;
    PORT
      LAYER M5 ;
        RECT  128.736 0 128.76 0.084 ;
    END
  END xbi[254]
  PIN xbi[255]
    DIRECTION INPUT ;
    USE SIGNAL ;
    PORT
      LAYER M5 ;
        RECT  128.88 0 128.904 0.084 ;
    END
  END xbi[255]
  PIN xbi[256]
    DIRECTION INPUT ;
    USE SIGNAL ;
    PORT
      LAYER M5 ;
        RECT  129.024 0 129.048 0.084 ;
    END
  END xbi[256]
  PIN xbi[257]
    DIRECTION INPUT ;
    USE SIGNAL ;
    PORT
      LAYER M5 ;
        RECT  129.168 0 129.192 0.084 ;
    END
  END xbi[257]
  PIN xbi[258]
    DIRECTION INPUT ;
    USE SIGNAL ;
    PORT
      LAYER M5 ;
        RECT  129.312 0 129.336 0.084 ;
    END
  END xbi[258]
  PIN xbi[259]
    DIRECTION INPUT ;
    USE SIGNAL ;
    PORT
      LAYER M5 ;
        RECT  129.456 0 129.48 0.084 ;
    END
  END xbi[259]
  PIN xbi[25]
    DIRECTION INPUT ;
    USE SIGNAL ;
    PORT
      LAYER M5 ;
        RECT  95.76 0 95.784 0.084 ;
    END
  END xbi[25]
  PIN xbi[260]
    DIRECTION INPUT ;
    USE SIGNAL ;
    PORT
      LAYER M5 ;
        RECT  129.6 0 129.624 0.084 ;
    END
  END xbi[260]
  PIN xbi[261]
    DIRECTION INPUT ;
    USE SIGNAL ;
    PORT
      LAYER M5 ;
        RECT  129.744 0 129.768 0.084 ;
    END
  END xbi[261]
  PIN xbi[262]
    DIRECTION INPUT ;
    USE SIGNAL ;
    PORT
      LAYER M5 ;
        RECT  129.888 0 129.912 0.084 ;
    END
  END xbi[262]
  PIN xbi[263]
    DIRECTION INPUT ;
    USE SIGNAL ;
    PORT
      LAYER M5 ;
        RECT  130.032 0 130.056 0.084 ;
    END
  END xbi[263]
  PIN xbi[264]
    DIRECTION INPUT ;
    USE SIGNAL ;
    PORT
      LAYER M5 ;
        RECT  130.176 0 130.2 0.084 ;
    END
  END xbi[264]
  PIN xbi[265]
    DIRECTION INPUT ;
    USE SIGNAL ;
    PORT
      LAYER M5 ;
        RECT  130.32 0 130.344 0.084 ;
    END
  END xbi[265]
  PIN xbi[26]
    DIRECTION INPUT ;
    USE SIGNAL ;
    PORT
      LAYER M5 ;
        RECT  95.904 0 95.928 0.084 ;
    END
  END xbi[26]
  PIN xbi[27]
    DIRECTION INPUT ;
    USE SIGNAL ;
    PORT
      LAYER M5 ;
        RECT  96.048 0 96.072 0.084 ;
    END
  END xbi[27]
  PIN xbi[28]
    DIRECTION INPUT ;
    USE SIGNAL ;
    PORT
      LAYER M5 ;
        RECT  96.192 0 96.216 0.084 ;
    END
  END xbi[28]
  PIN xbi[29]
    DIRECTION INPUT ;
    USE SIGNAL ;
    PORT
      LAYER M5 ;
        RECT  96.336 0 96.36 0.084 ;
    END
  END xbi[29]
  PIN xbi[2]
    DIRECTION INPUT ;
    USE SIGNAL ;
    PORT
      LAYER M5 ;
        RECT  92.448 0 92.472 0.084 ;
    END
  END xbi[2]
  PIN xbi[30]
    DIRECTION INPUT ;
    USE SIGNAL ;
    PORT
      LAYER M5 ;
        RECT  96.48 0 96.504 0.084 ;
    END
  END xbi[30]
  PIN xbi[31]
    DIRECTION INPUT ;
    USE SIGNAL ;
    PORT
      LAYER M5 ;
        RECT  96.624 0 96.648 0.084 ;
    END
  END xbi[31]
  PIN xbi[32]
    DIRECTION INPUT ;
    USE SIGNAL ;
    PORT
      LAYER M5 ;
        RECT  96.768 0 96.792 0.084 ;
    END
  END xbi[32]
  PIN xbi[33]
    DIRECTION INPUT ;
    USE SIGNAL ;
    PORT
      LAYER M5 ;
        RECT  96.912 0 96.936 0.084 ;
    END
  END xbi[33]
  PIN xbi[34]
    DIRECTION INPUT ;
    USE SIGNAL ;
    PORT
      LAYER M5 ;
        RECT  97.056 0 97.08 0.084 ;
    END
  END xbi[34]
  PIN xbi[35]
    DIRECTION INPUT ;
    USE SIGNAL ;
    PORT
      LAYER M5 ;
        RECT  97.2 0 97.224 0.084 ;
    END
  END xbi[35]
  PIN xbi[36]
    DIRECTION INPUT ;
    USE SIGNAL ;
    PORT
      LAYER M5 ;
        RECT  97.344 0 97.368 0.084 ;
    END
  END xbi[36]
  PIN xbi[37]
    DIRECTION INPUT ;
    USE SIGNAL ;
    PORT
      LAYER M5 ;
        RECT  97.488 0 97.512 0.084 ;
    END
  END xbi[37]
  PIN xbi[38]
    DIRECTION INPUT ;
    USE SIGNAL ;
    PORT
      LAYER M5 ;
        RECT  97.632 0 97.656 0.084 ;
    END
  END xbi[38]
  PIN xbi[39]
    DIRECTION INPUT ;
    USE SIGNAL ;
    PORT
      LAYER M5 ;
        RECT  97.776 0 97.8 0.084 ;
    END
  END xbi[39]
  PIN xbi[3]
    DIRECTION INPUT ;
    USE SIGNAL ;
    PORT
      LAYER M5 ;
        RECT  92.592 0 92.616 0.084 ;
    END
  END xbi[3]
  PIN xbi[40]
    DIRECTION INPUT ;
    USE SIGNAL ;
    PORT
      LAYER M5 ;
        RECT  97.92 0 97.944 0.084 ;
    END
  END xbi[40]
  PIN xbi[41]
    DIRECTION INPUT ;
    USE SIGNAL ;
    PORT
      LAYER M5 ;
        RECT  98.064 0 98.088 0.084 ;
    END
  END xbi[41]
  PIN xbi[42]
    DIRECTION INPUT ;
    USE SIGNAL ;
    PORT
      LAYER M5 ;
        RECT  98.208 0 98.232 0.084 ;
    END
  END xbi[42]
  PIN xbi[43]
    DIRECTION INPUT ;
    USE SIGNAL ;
    PORT
      LAYER M5 ;
        RECT  98.352 0 98.376 0.084 ;
    END
  END xbi[43]
  PIN xbi[44]
    DIRECTION INPUT ;
    USE SIGNAL ;
    PORT
      LAYER M5 ;
        RECT  98.496 0 98.52 0.084 ;
    END
  END xbi[44]
  PIN xbi[45]
    DIRECTION INPUT ;
    USE SIGNAL ;
    PORT
      LAYER M5 ;
        RECT  98.64 0 98.664 0.084 ;
    END
  END xbi[45]
  PIN xbi[46]
    DIRECTION INPUT ;
    USE SIGNAL ;
    PORT
      LAYER M5 ;
        RECT  98.784 0 98.808 0.084 ;
    END
  END xbi[46]
  PIN xbi[47]
    DIRECTION INPUT ;
    USE SIGNAL ;
    PORT
      LAYER M5 ;
        RECT  98.928 0 98.952 0.084 ;
    END
  END xbi[47]
  PIN xbi[48]
    DIRECTION INPUT ;
    USE SIGNAL ;
    PORT
      LAYER M5 ;
        RECT  99.072 0 99.096 0.084 ;
    END
  END xbi[48]
  PIN xbi[49]
    DIRECTION INPUT ;
    USE SIGNAL ;
    PORT
      LAYER M5 ;
        RECT  99.216 0 99.24 0.084 ;
    END
  END xbi[49]
  PIN xbi[4]
    DIRECTION INPUT ;
    USE SIGNAL ;
    PORT
      LAYER M5 ;
        RECT  92.736 0 92.76 0.084 ;
    END
  END xbi[4]
  PIN xbi[50]
    DIRECTION INPUT ;
    USE SIGNAL ;
    PORT
      LAYER M5 ;
        RECT  99.36 0 99.384 0.084 ;
    END
  END xbi[50]
  PIN xbi[51]
    DIRECTION INPUT ;
    USE SIGNAL ;
    PORT
      LAYER M5 ;
        RECT  99.504 0 99.528 0.084 ;
    END
  END xbi[51]
  PIN xbi[52]
    DIRECTION INPUT ;
    USE SIGNAL ;
    PORT
      LAYER M5 ;
        RECT  99.648 0 99.672 0.084 ;
    END
  END xbi[52]
  PIN xbi[53]
    DIRECTION INPUT ;
    USE SIGNAL ;
    PORT
      LAYER M5 ;
        RECT  99.792 0 99.816 0.084 ;
    END
  END xbi[53]
  PIN xbi[54]
    DIRECTION INPUT ;
    USE SIGNAL ;
    PORT
      LAYER M5 ;
        RECT  99.936 0 99.96 0.084 ;
    END
  END xbi[54]
  PIN xbi[55]
    DIRECTION INPUT ;
    USE SIGNAL ;
    PORT
      LAYER M5 ;
        RECT  100.08 0 100.104 0.084 ;
    END
  END xbi[55]
  PIN xbi[56]
    DIRECTION INPUT ;
    USE SIGNAL ;
    PORT
      LAYER M5 ;
        RECT  100.224 0 100.248 0.084 ;
    END
  END xbi[56]
  PIN xbi[57]
    DIRECTION INPUT ;
    USE SIGNAL ;
    PORT
      LAYER M5 ;
        RECT  100.368 0 100.392 0.084 ;
    END
  END xbi[57]
  PIN xbi[58]
    DIRECTION INPUT ;
    USE SIGNAL ;
    PORT
      LAYER M5 ;
        RECT  100.512 0 100.536 0.084 ;
    END
  END xbi[58]
  PIN xbi[59]
    DIRECTION INPUT ;
    USE SIGNAL ;
    PORT
      LAYER M5 ;
        RECT  100.656 0 100.68 0.084 ;
    END
  END xbi[59]
  PIN xbi[5]
    DIRECTION INPUT ;
    USE SIGNAL ;
    PORT
      LAYER M5 ;
        RECT  92.88 0 92.904 0.084 ;
    END
  END xbi[5]
  PIN xbi[60]
    DIRECTION INPUT ;
    USE SIGNAL ;
    PORT
      LAYER M5 ;
        RECT  100.8 0 100.824 0.084 ;
    END
  END xbi[60]
  PIN xbi[61]
    DIRECTION INPUT ;
    USE SIGNAL ;
    PORT
      LAYER M5 ;
        RECT  100.944 0 100.968 0.084 ;
    END
  END xbi[61]
  PIN xbi[62]
    DIRECTION INPUT ;
    USE SIGNAL ;
    PORT
      LAYER M5 ;
        RECT  101.088 0 101.112 0.084 ;
    END
  END xbi[62]
  PIN xbi[63]
    DIRECTION INPUT ;
    USE SIGNAL ;
    PORT
      LAYER M5 ;
        RECT  101.232 0 101.256 0.084 ;
    END
  END xbi[63]
  PIN xbi[64]
    DIRECTION INPUT ;
    USE SIGNAL ;
    PORT
      LAYER M5 ;
        RECT  101.376 0 101.4 0.084 ;
    END
  END xbi[64]
  PIN xbi[65]
    DIRECTION INPUT ;
    USE SIGNAL ;
    PORT
      LAYER M5 ;
        RECT  101.52 0 101.544 0.084 ;
    END
  END xbi[65]
  PIN xbi[66]
    DIRECTION INPUT ;
    USE SIGNAL ;
    PORT
      LAYER M5 ;
        RECT  101.664 0 101.688 0.084 ;
    END
  END xbi[66]
  PIN xbi[67]
    DIRECTION INPUT ;
    USE SIGNAL ;
    PORT
      LAYER M5 ;
        RECT  101.808 0 101.832 0.084 ;
    END
  END xbi[67]
  PIN xbi[68]
    DIRECTION INPUT ;
    USE SIGNAL ;
    PORT
      LAYER M5 ;
        RECT  101.952 0 101.976 0.084 ;
    END
  END xbi[68]
  PIN xbi[69]
    DIRECTION INPUT ;
    USE SIGNAL ;
    PORT
      LAYER M5 ;
        RECT  102.096 0 102.12 0.084 ;
    END
  END xbi[69]
  PIN xbi[6]
    DIRECTION INPUT ;
    USE SIGNAL ;
    PORT
      LAYER M5 ;
        RECT  93.024 0 93.048 0.084 ;
    END
  END xbi[6]
  PIN xbi[70]
    DIRECTION INPUT ;
    USE SIGNAL ;
    PORT
      LAYER M5 ;
        RECT  102.24 0 102.264 0.084 ;
    END
  END xbi[70]
  PIN xbi[71]
    DIRECTION INPUT ;
    USE SIGNAL ;
    PORT
      LAYER M5 ;
        RECT  102.384 0 102.408 0.084 ;
    END
  END xbi[71]
  PIN xbi[72]
    DIRECTION INPUT ;
    USE SIGNAL ;
    PORT
      LAYER M5 ;
        RECT  102.528 0 102.552 0.084 ;
    END
  END xbi[72]
  PIN xbi[73]
    DIRECTION INPUT ;
    USE SIGNAL ;
    PORT
      LAYER M5 ;
        RECT  102.672 0 102.696 0.084 ;
    END
  END xbi[73]
  PIN xbi[74]
    DIRECTION INPUT ;
    USE SIGNAL ;
    PORT
      LAYER M5 ;
        RECT  102.816 0 102.84 0.084 ;
    END
  END xbi[74]
  PIN xbi[75]
    DIRECTION INPUT ;
    USE SIGNAL ;
    PORT
      LAYER M5 ;
        RECT  102.96 0 102.984 0.084 ;
    END
  END xbi[75]
  PIN xbi[76]
    DIRECTION INPUT ;
    USE SIGNAL ;
    PORT
      LAYER M5 ;
        RECT  103.104 0 103.128 0.084 ;
    END
  END xbi[76]
  PIN xbi[77]
    DIRECTION INPUT ;
    USE SIGNAL ;
    PORT
      LAYER M5 ;
        RECT  103.248 0 103.272 0.084 ;
    END
  END xbi[77]
  PIN xbi[78]
    DIRECTION INPUT ;
    USE SIGNAL ;
    PORT
      LAYER M5 ;
        RECT  103.392 0 103.416 0.084 ;
    END
  END xbi[78]
  PIN xbi[79]
    DIRECTION INPUT ;
    USE SIGNAL ;
    PORT
      LAYER M5 ;
        RECT  103.536 0 103.56 0.084 ;
    END
  END xbi[79]
  PIN xbi[7]
    DIRECTION INPUT ;
    USE SIGNAL ;
    PORT
      LAYER M5 ;
        RECT  93.168 0 93.192 0.084 ;
    END
  END xbi[7]
  PIN xbi[80]
    DIRECTION INPUT ;
    USE SIGNAL ;
    PORT
      LAYER M5 ;
        RECT  103.68 0 103.704 0.084 ;
    END
  END xbi[80]
  PIN xbi[81]
    DIRECTION INPUT ;
    USE SIGNAL ;
    PORT
      LAYER M5 ;
        RECT  103.824 0 103.848 0.084 ;
    END
  END xbi[81]
  PIN xbi[82]
    DIRECTION INPUT ;
    USE SIGNAL ;
    PORT
      LAYER M5 ;
        RECT  103.968 0 103.992 0.084 ;
    END
  END xbi[82]
  PIN xbi[83]
    DIRECTION INPUT ;
    USE SIGNAL ;
    PORT
      LAYER M5 ;
        RECT  104.112 0 104.136 0.084 ;
    END
  END xbi[83]
  PIN xbi[84]
    DIRECTION INPUT ;
    USE SIGNAL ;
    PORT
      LAYER M5 ;
        RECT  104.256 0 104.28 0.084 ;
    END
  END xbi[84]
  PIN xbi[85]
    DIRECTION INPUT ;
    USE SIGNAL ;
    PORT
      LAYER M5 ;
        RECT  104.4 0 104.424 0.084 ;
    END
  END xbi[85]
  PIN xbi[86]
    DIRECTION INPUT ;
    USE SIGNAL ;
    PORT
      LAYER M5 ;
        RECT  104.544 0 104.568 0.084 ;
    END
  END xbi[86]
  PIN xbi[87]
    DIRECTION INPUT ;
    USE SIGNAL ;
    PORT
      LAYER M5 ;
        RECT  104.688 0 104.712 0.084 ;
    END
  END xbi[87]
  PIN xbi[88]
    DIRECTION INPUT ;
    USE SIGNAL ;
    PORT
      LAYER M5 ;
        RECT  104.832 0 104.856 0.084 ;
    END
  END xbi[88]
  PIN xbi[89]
    DIRECTION INPUT ;
    USE SIGNAL ;
    PORT
      LAYER M5 ;
        RECT  104.976 0 105 0.084 ;
    END
  END xbi[89]
  PIN xbi[8]
    DIRECTION INPUT ;
    USE SIGNAL ;
    PORT
      LAYER M5 ;
        RECT  93.312 0 93.336 0.084 ;
    END
  END xbi[8]
  PIN xbi[90]
    DIRECTION INPUT ;
    USE SIGNAL ;
    PORT
      LAYER M5 ;
        RECT  105.12 0 105.144 0.084 ;
    END
  END xbi[90]
  PIN xbi[91]
    DIRECTION INPUT ;
    USE SIGNAL ;
    PORT
      LAYER M5 ;
        RECT  105.264 0 105.288 0.084 ;
    END
  END xbi[91]
  PIN xbi[92]
    DIRECTION INPUT ;
    USE SIGNAL ;
    PORT
      LAYER M5 ;
        RECT  105.408 0 105.432 0.084 ;
    END
  END xbi[92]
  PIN xbi[93]
    DIRECTION INPUT ;
    USE SIGNAL ;
    PORT
      LAYER M5 ;
        RECT  105.552 0 105.576 0.084 ;
    END
  END xbi[93]
  PIN xbi[94]
    DIRECTION INPUT ;
    USE SIGNAL ;
    PORT
      LAYER M5 ;
        RECT  105.696 0 105.72 0.084 ;
    END
  END xbi[94]
  PIN xbi[95]
    DIRECTION INPUT ;
    USE SIGNAL ;
    PORT
      LAYER M5 ;
        RECT  105.84 0 105.864 0.084 ;
    END
  END xbi[95]
  PIN xbi[96]
    DIRECTION INPUT ;
    USE SIGNAL ;
    PORT
      LAYER M5 ;
        RECT  105.984 0 106.008 0.084 ;
    END
  END xbi[96]
  PIN xbi[97]
    DIRECTION INPUT ;
    USE SIGNAL ;
    PORT
      LAYER M5 ;
        RECT  106.128 0 106.152 0.084 ;
    END
  END xbi[97]
  PIN xbi[98]
    DIRECTION INPUT ;
    USE SIGNAL ;
    PORT
      LAYER M5 ;
        RECT  106.272 0 106.296 0.084 ;
    END
  END xbi[98]
  PIN xbi[99]
    DIRECTION INPUT ;
    USE SIGNAL ;
    PORT
      LAYER M5 ;
        RECT  106.416 0 106.44 0.084 ;
    END
  END xbi[99]
  PIN xbi[9]
    DIRECTION INPUT ;
    USE SIGNAL ;
    PORT
      LAYER M5 ;
        RECT  93.456 0 93.48 0.084 ;
    END
  END xbi[9]
  PIN VDD
    DIRECTION INOUT ;
    USE POWER ;
    PORT
      LAYER M5 ;
        RECT  169.992 2.151 170.112 28.089 ;
        RECT  167.292 2.151 167.412 28.089 ;
        RECT  164.592 2.151 164.712 28.089 ;
        RECT  161.892 2.151 162.012 28.089 ;
        RECT  159.192 2.151 159.312 28.089 ;
        RECT  156.492 2.151 156.612 28.089 ;
        RECT  153.792 2.151 153.912 28.089 ;
        RECT  151.092 2.151 151.212 28.089 ;
        RECT  148.392 2.151 148.512 28.089 ;
        RECT  145.692 2.151 145.812 28.089 ;
        RECT  142.992 2.151 143.112 28.089 ;
        RECT  140.292 2.151 140.412 28.089 ;
        RECT  137.592 2.151 137.712 28.089 ;
        RECT  134.892 2.151 135.012 28.089 ;
        RECT  132.192 2.151 132.312 28.089 ;
        RECT  129.492 2.151 129.612 28.089 ;
        RECT  126.792 2.151 126.912 28.089 ;
        RECT  124.092 2.151 124.212 28.089 ;
        RECT  121.392 2.151 121.512 28.089 ;
        RECT  118.692 2.151 118.812 28.089 ;
        RECT  115.992 2.151 116.112 28.089 ;
        RECT  113.292 2.151 113.412 28.089 ;
        RECT  110.592 2.151 110.712 28.089 ;
        RECT  107.892 2.151 108.012 28.089 ;
        RECT  105.192 2.151 105.312 28.089 ;
        RECT  102.492 2.151 102.612 28.089 ;
        RECT  99.792 2.151 99.912 28.089 ;
        RECT  97.092 2.151 97.212 28.089 ;
        RECT  94.392 2.151 94.512 28.089 ;
        RECT  91.692 2.151 91.812 28.089 ;
        RECT  88.992 2.151 89.112 28.089 ;
        RECT  86.292 2.151 86.412 28.089 ;
        RECT  83.592 2.151 83.712 28.089 ;
        RECT  80.892 2.151 81.012 28.089 ;
        RECT  78.192 2.151 78.312 28.089 ;
        RECT  75.492 2.151 75.612 28.089 ;
        RECT  72.792 2.151 72.912 28.089 ;
        RECT  70.092 2.151 70.212 28.089 ;
        RECT  67.392 2.151 67.512 28.089 ;
        RECT  64.692 2.151 64.812 28.089 ;
        RECT  61.992 2.151 62.112 28.089 ;
        RECT  59.292 2.151 59.412 28.089 ;
        RECT  56.592 2.151 56.712 28.089 ;
        RECT  53.892 2.151 54.012 28.089 ;
        RECT  51.192 2.151 51.312 28.089 ;
        RECT  48.492 2.151 48.612 28.089 ;
        RECT  45.792 2.151 45.912 28.089 ;
        RECT  43.092 2.151 43.212 28.089 ;
        RECT  40.392 2.151 40.512 28.089 ;
        RECT  37.692 2.151 37.812 28.089 ;
        RECT  34.992 2.151 35.112 28.089 ;
        RECT  32.292 2.151 32.412 28.089 ;
        RECT  29.592 2.151 29.712 28.089 ;
        RECT  26.892 2.151 27.012 28.089 ;
        RECT  24.192 2.151 24.312 28.089 ;
        RECT  21.492 2.151 21.612 28.089 ;
        RECT  18.792 2.151 18.912 28.089 ;
        RECT  16.092 2.151 16.212 28.089 ;
        RECT  13.392 2.151 13.512 28.089 ;
        RECT  10.692 2.151 10.812 28.089 ;
        RECT  7.992 2.151 8.112 28.089 ;
        RECT  5.292 2.151 5.412 28.089 ;
        RECT  2.592 2.151 2.712 28.089 ;
    END
  END VDD
  PIN VSS
    DIRECTION INOUT ;
    USE GROUND ;
    PORT
      LAYER M5 ;
        RECT  169.8 2.137 169.92 28.103 ;
        RECT  167.1 2.137 167.22 28.103 ;
        RECT  164.4 2.137 164.52 28.103 ;
        RECT  161.7 2.137 161.82 28.103 ;
        RECT  159 2.137 159.12 28.103 ;
        RECT  156.3 2.137 156.42 28.103 ;
        RECT  153.6 2.137 153.72 28.103 ;
        RECT  150.9 2.137 151.02 28.103 ;
        RECT  148.2 2.137 148.32 28.103 ;
        RECT  145.5 2.137 145.62 28.103 ;
        RECT  142.8 2.137 142.92 28.103 ;
        RECT  140.1 2.137 140.22 28.103 ;
        RECT  137.4 2.137 137.52 28.103 ;
        RECT  134.7 2.137 134.82 28.103 ;
        RECT  132 2.137 132.12 28.103 ;
        RECT  129.3 2.137 129.42 28.103 ;
        RECT  126.6 2.137 126.72 28.103 ;
        RECT  123.9 2.137 124.02 28.103 ;
        RECT  121.2 2.137 121.32 28.103 ;
        RECT  118.5 2.137 118.62 28.103 ;
        RECT  115.8 2.137 115.92 28.103 ;
        RECT  113.1 2.137 113.22 28.103 ;
        RECT  110.4 2.137 110.52 28.103 ;
        RECT  107.7 2.137 107.82 28.103 ;
        RECT  105 2.137 105.12 28.103 ;
        RECT  102.3 2.137 102.42 28.103 ;
        RECT  99.6 2.137 99.72 28.103 ;
        RECT  96.9 2.137 97.02 28.103 ;
        RECT  94.2 2.137 94.32 28.103 ;
        RECT  91.5 2.137 91.62 28.103 ;
        RECT  88.8 2.137 88.92 28.103 ;
        RECT  86.1 2.137 86.22 28.103 ;
        RECT  83.4 2.137 83.52 28.103 ;
        RECT  80.7 2.137 80.82 28.103 ;
        RECT  78 2.137 78.12 28.103 ;
        RECT  75.3 2.137 75.42 28.103 ;
        RECT  72.6 2.137 72.72 28.103 ;
        RECT  69.9 2.137 70.02 28.103 ;
        RECT  67.2 2.137 67.32 28.103 ;
        RECT  64.5 2.137 64.62 28.103 ;
        RECT  61.8 2.137 61.92 28.103 ;
        RECT  59.1 2.137 59.22 28.103 ;
        RECT  56.4 2.137 56.52 28.103 ;
        RECT  53.7 2.137 53.82 28.103 ;
        RECT  51 2.137 51.12 28.103 ;
        RECT  48.3 2.137 48.42 28.103 ;
        RECT  45.6 2.137 45.72 28.103 ;
        RECT  42.9 2.137 43.02 28.103 ;
        RECT  40.2 2.137 40.32 28.103 ;
        RECT  37.5 2.137 37.62 28.103 ;
        RECT  34.8 2.137 34.92 28.103 ;
        RECT  32.1 2.137 32.22 28.103 ;
        RECT  29.4 2.137 29.52 28.103 ;
        RECT  26.7 2.137 26.82 28.103 ;
        RECT  24 2.137 24.12 28.103 ;
        RECT  21.3 2.137 21.42 28.103 ;
        RECT  18.6 2.137 18.72 28.103 ;
        RECT  15.9 2.137 16.02 28.103 ;
        RECT  13.2 2.137 13.32 28.103 ;
        RECT  10.5 2.137 10.62 28.103 ;
        RECT  7.8 2.137 7.92 28.103 ;
        RECT  5.1 2.137 5.22 28.103 ;
        RECT  2.4 2.137 2.52 28.103 ;
    END
  END VSS
  # OT_OBS_CLOSED layer=M5 d_um=1.536 added=126
  OBS
    LAYER RVTN ;
     RECT  2.16 2.16 170.64 2.295 ;
     RECT  2.16 2.565 170.64 2.835 ;
     RECT  2.16 3.105 170.64 3.375 ;
     RECT  2.16 3.645 170.64 3.915 ;
     RECT  2.16 4.185 170.64 4.455 ;
     RECT  2.16 4.725 170.64 4.995 ;
     RECT  2.16 5.265 170.64 5.535 ;
     RECT  2.16 5.805 170.64 6.075 ;
     RECT  2.16 6.345 170.64 6.615 ;
     RECT  2.16 6.885 170.64 7.155 ;
     RECT  2.16 7.425 170.64 7.695 ;
     RECT  2.16 7.965 170.64 8.235 ;
     RECT  2.16 8.505 170.64 8.775 ;
     RECT  2.16 9.045 170.64 9.315 ;
     RECT  2.16 9.585 170.64 9.855 ;
     RECT  2.16 10.125 170.64 10.395 ;
     RECT  2.16 10.665 170.64 10.935 ;
     RECT  2.16 11.205 170.64 11.475 ;
     RECT  2.16 11.745 170.64 12.015 ;
     RECT  2.16 12.285 170.64 12.555 ;
     RECT  2.16 12.825 170.64 13.095 ;
     RECT  2.16 13.365 170.64 13.635 ;
     RECT  2.16 13.905 170.64 14.175 ;
     RECT  2.16 14.445 170.64 14.715 ;
     RECT  2.16 14.985 170.64 15.255 ;
     RECT  2.16 15.525 170.64 15.795 ;
     RECT  2.16 16.065 170.64 16.335 ;
     RECT  2.16 16.605 170.64 16.875 ;
     RECT  2.16 17.145 170.64 17.415 ;
     RECT  2.16 17.685 170.64 17.955 ;
     RECT  2.16 18.225 170.64 18.495 ;
     RECT  2.16 18.765 170.64 19.035 ;
     RECT  2.16 19.305 170.64 19.575 ;
     RECT  2.16 19.845 170.64 20.115 ;
     RECT  2.16 20.385 170.64 20.655 ;
     RECT  2.16 20.925 170.64 21.195 ;
     RECT  2.16 21.465 170.64 21.735 ;
     RECT  2.16 22.005 170.64 22.275 ;
     RECT  2.16 22.545 170.64 22.815 ;
     RECT  2.16 23.085 170.64 23.355 ;
     RECT  2.16 23.625 170.64 23.895 ;
     RECT  2.16 24.165 170.64 24.435 ;
     RECT  2.16 24.705 170.64 24.975 ;
     RECT  2.16 25.245 170.64 25.515 ;
     RECT  2.16 25.785 170.64 26.055 ;
     RECT  2.16 26.325 170.64 26.595 ;
     RECT  2.16 26.865 170.64 27.135 ;
     RECT  2.16 27.405 170.64 27.675 ;
     RECT  2.16 27.945 170.64 28.08 ;
    LAYER RVTP ;
     RECT  2.16 2.295 170.64 2.565 ;
     RECT  2.16 2.835 170.64 3.105 ;
     RECT  2.16 3.375 170.64 3.645 ;
     RECT  2.16 3.915 170.64 4.185 ;
     RECT  2.16 4.455 170.64 4.725 ;
     RECT  2.16 4.995 170.64 5.265 ;
     RECT  2.16 5.535 170.64 5.805 ;
     RECT  2.16 6.075 170.64 6.345 ;
     RECT  2.16 6.615 170.64 6.885 ;
     RECT  2.16 7.155 170.64 7.425 ;
     RECT  2.16 7.695 170.64 7.965 ;
     RECT  2.16 8.235 170.64 8.505 ;
     RECT  2.16 8.775 170.64 9.045 ;
     RECT  2.16 9.315 170.64 9.585 ;
     RECT  2.16 9.855 170.64 10.125 ;
     RECT  2.16 10.395 170.64 10.665 ;
     RECT  2.16 10.935 170.64 11.205 ;
     RECT  2.16 11.475 170.64 11.745 ;
     RECT  2.16 12.015 170.64 12.285 ;
     RECT  2.16 12.555 170.64 12.825 ;
     RECT  2.16 13.095 170.64 13.365 ;
     RECT  2.16 13.635 170.64 13.905 ;
     RECT  2.16 14.175 170.64 14.445 ;
     RECT  2.16 14.715 170.64 14.985 ;
     RECT  2.16 15.255 170.64 15.525 ;
     RECT  2.16 15.795 170.64 16.065 ;
     RECT  2.16 16.335 170.64 16.605 ;
     RECT  2.16 16.875 170.64 17.145 ;
     RECT  2.16 17.415 170.64 17.685 ;
     RECT  2.16 17.955 170.64 18.225 ;
     RECT  2.16 18.495 170.64 18.765 ;
     RECT  2.16 19.035 170.64 19.305 ;
     RECT  2.16 19.575 170.64 19.845 ;
     RECT  2.16 20.115 170.64 20.385 ;
     RECT  2.16 20.655 170.64 20.925 ;
     RECT  2.16 21.195 170.64 21.465 ;
     RECT  2.16 21.735 170.64 22.005 ;
     RECT  2.16 22.275 170.64 22.545 ;
     RECT  2.16 22.815 170.64 23.085 ;
     RECT  2.16 23.355 170.64 23.625 ;
     RECT  2.16 23.895 170.64 24.165 ;
     RECT  2.16 24.435 170.64 24.705 ;
     RECT  2.16 24.975 170.64 25.245 ;
     RECT  2.16 25.515 170.64 25.785 ;
     RECT  2.16 26.055 170.64 26.325 ;
     RECT  2.16 26.595 170.64 26.865 ;
     RECT  2.16 27.135 170.64 27.405 ;
     RECT  2.16 27.675 170.64 27.945 ;
    LAYER M1 ;
     RECT  2.16 2.151 170.64 28.089 ;
    LAYER M2 ;
     RECT  70.375 29.034 70.475 29.052 ;
     RECT  81.247 29.034 81.455 29.052 ;
     RECT  2.16 2.151 87.007 28.089 ;
     RECT  87.007 2.034 88.583 28.089 ;
     RECT  88.583 2.106 89.015 28.089 ;
     RECT  94.639 1.224 94.739 1.242 ;
     RECT  89.015 2.151 95.323 28.089 ;
     RECT  95.323 2.106 95.755 28.089 ;
     RECT  95.755 1.8 97.051 28.089 ;
     RECT  97.051 1.728 99.499 28.089 ;
     RECT  99.499 1.152 99.599 28.089 ;
     RECT  104.935 29.034 105.395 29.052 ;
     RECT  113.611 29.034 113.855 29.052 ;
     RECT  99.599 1.728 117.311 28.089 ;
     RECT  117.311 1.764 119.947 28.089 ;
     RECT  119.947 1.728 122.531 28.089 ;
     RECT  122.531 1.764 124.735 28.089 ;
     RECT  124.735 1.728 131.459 28.089 ;
     RECT  131.459 1.764 133.195 28.089 ;
     RECT  133.195 1.728 140.531 28.089 ;
     RECT  140.531 1.764 152.779 28.089 ;
     RECT  152.779 1.728 153.635 28.089 ;
     RECT  153.635 1.764 157.379 28.089 ;
     RECT  157.379 1.836 164.363 28.089 ;
     RECT  164.363 1.926 164.399 28.089 ;
     RECT  164.399 1.962 167.315 28.089 ;
     RECT  167.315 2.07 169.475 28.089 ;
     RECT  169.475 2.106 169.799 28.089 ;
     RECT  169.799 2.151 170.64 28.089 ;
     RECT  170.64 2.88 170.699 5.526 ;
     RECT  170.699 2.88 171.023 5.454 ;
     RECT  171.023 4.122 171.095 5.454 ;
     RECT  171.095 4.734 171.275 5.454 ;
     RECT  171.023 2.88 171.311 2.898 ;
     RECT  171.275 4.968 171.563 5.454 ;
     RECT  171.563 4.968 171.635 4.986 ;
    LAYER M3 ;
     RECT  169.596 0.091 170.226 0.139 ;
     RECT  94.716 0.091 94.734 0.283 ;
     RECT  171.612 0.091 171.63 0.523 ;
     RECT  131.616 0.091 131.634 0.571 ;
     RECT  87.804 0.571 87.822 1.051 ;
     RECT  87.804 1.051 88.002 1.099 ;
     RECT  89.388 0.091 89.406 1.099 ;
     RECT  131.112 0.571 131.634 1.099 ;
     RECT  91.008 0.091 91.026 1.147 ;
     RECT  99.576 0.523 99.594 1.147 ;
     RECT  169.596 0.139 170.334 1.627 ;
     RECT  171.252 0.523 171.63 1.627 ;
     RECT  87.804 1.099 89.406 1.723 ;
     RECT  92.196 0.091 92.214 1.723 ;
     RECT  94.644 0.283 94.734 1.723 ;
     RECT  99.504 1.147 99.594 1.723 ;
     RECT  108.756 1.099 108.774 1.723 ;
     RECT  116.136 0.091 116.154 1.723 ;
     RECT  123.048 0.523 123.066 1.723 ;
     RECT  131.112 1.099 132.246 1.723 ;
     RECT  144.72 0.523 145.17 1.723 ;
     RECT  169.596 1.627 171.63 1.723 ;
     RECT  97.812 1.723 100.674 1.759 ;
     RECT  101.772 1.723 102.726 1.759 ;
     RECT  103.5 1.723 104.418 1.759 ;
     RECT  127.656 1.723 128.034 1.759 ;
     RECT  129.24 1.723 129.87 1.759 ;
     RECT  131.112 1.723 133.866 1.759 ;
     RECT  91.944 1.723 95.994 1.771 ;
     RECT  96.768 1.723 97.074 1.771 ;
     RECT  97.812 1.759 100.998 1.771 ;
     RECT  108.756 1.723 111.222 1.771 ;
     RECT  112.032 1.723 112.986 1.771 ;
     RECT  114.048 1.723 120.114 1.771 ;
     RECT  125.532 1.723 126.594 1.771 ;
     RECT  127.368 1.759 128.034 1.771 ;
     RECT  129.24 1.759 133.866 1.771 ;
     RECT  138.924 1.723 142.614 1.771 ;
     RECT  148.104 1.723 150.174 1.771 ;
     RECT  151.056 1.723 155.898 1.771 ;
     RECT  157.212 1.723 157.518 1.771 ;
     RECT  158.256 1.723 158.886 1.771 ;
     RECT  165.708 1.723 166.878 1.771 ;
     RECT  167.868 1.723 167.886 1.771 ;
     RECT  168.66 1.723 171.63 1.771 ;
     RECT  108.756 1.771 112.986 1.795 ;
     RECT  121.716 1.723 121.734 1.795 ;
     RECT  122.508 1.723 124.758 1.795 ;
     RECT  125.532 1.771 128.106 1.795 ;
     RECT  105.372 1.723 107.622 1.819 ;
     RECT  108.684 1.795 112.986 1.819 ;
     RECT  120.96 1.723 120.978 1.819 ;
     RECT  121.716 1.795 128.106 1.819 ;
     RECT  134.604 1.723 134.622 1.819 ;
     RECT  137.844 1.723 137.862 1.819 ;
     RECT  138.672 1.771 142.614 1.819 ;
     RECT  143.496 1.723 147.258 1.819 ;
     RECT  137.592 1.819 137.862 1.831 ;
     RECT  138.672 1.819 147.258 1.831 ;
     RECT  148.104 1.771 156.294 1.831 ;
     RECT  157.212 1.771 159.606 1.831 ;
     RECT  160.596 1.723 164.142 1.831 ;
     RECT  91.944 1.771 100.998 1.876 ;
     RECT  101.772 1.759 104.418 1.876 ;
     RECT  105.372 1.819 113.022 1.876 ;
     RECT  165.204 1.771 166.878 1.915 ;
     RECT  167.652 1.771 171.63 1.915 ;
     RECT  91.944 1.876 113.058 1.921 ;
     RECT  113.796 1.771 120.114 1.921 ;
     RECT  148.104 1.831 159.606 1.921 ;
     RECT  160.596 1.831 164.358 1.921 ;
     RECT  91.944 1.921 120.114 1.957 ;
     RECT  120.96 1.819 128.106 1.957 ;
     RECT  134.604 1.819 134.658 1.963 ;
     RECT  135.54 1.723 135.558 1.963 ;
     RECT  128.988 1.771 133.866 2.011 ;
     RECT  134.604 1.963 135.558 2.011 ;
     RECT  136.476 1.723 136.818 2.011 ;
     RECT  137.592 1.831 147.258 2.011 ;
     RECT  91.944 1.957 128.106 2.029 ;
     RECT  128.988 2.011 135.558 2.029 ;
     RECT  136.476 2.011 147.258 2.029 ;
     RECT  160.596 1.921 164.394 2.029 ;
     RECT  90.936 1.147 91.026 2.143 ;
     RECT  91.944 2.029 147.258 2.143 ;
     RECT  160.38 2.029 164.394 2.143 ;
     RECT  165.204 1.915 171.63 2.143 ;
     RECT  90.936 2.143 147.258 2.191 ;
     RECT  148.068 1.921 159.606 2.191 ;
     RECT  160.38 2.143 171.63 2.191 ;
     RECT  87.012 2.029 87.03 2.227 ;
     RECT  87.804 1.723 90.054 2.227 ;
     RECT  86.115 2.143 86.205 2.371 ;
     RECT  87.012 2.227 90.054 2.371 ;
     RECT  90.936 2.191 171.63 2.371 ;
     RECT  2.415 2.143 2.505 2.413 ;
     RECT  5.115 2.143 5.205 2.413 ;
     RECT  7.815 2.143 7.905 2.413 ;
     RECT  10.515 2.143 10.605 2.413 ;
     RECT  13.215 2.143 13.305 2.413 ;
     RECT  15.915 2.143 16.005 2.413 ;
     RECT  18.615 2.143 18.705 2.413 ;
     RECT  21.315 2.143 21.405 2.413 ;
     RECT  24.015 2.143 24.105 2.413 ;
     RECT  26.715 2.143 26.805 2.413 ;
     RECT  29.415 2.143 29.505 2.413 ;
     RECT  32.115 2.143 32.205 2.413 ;
     RECT  34.815 2.143 34.905 2.413 ;
     RECT  37.515 2.143 37.605 2.413 ;
     RECT  40.215 2.143 40.305 2.413 ;
     RECT  42.915 2.143 43.005 2.413 ;
     RECT  45.615 2.143 45.705 2.413 ;
     RECT  48.315 2.143 48.405 2.413 ;
     RECT  51.015 2.143 51.105 2.413 ;
     RECT  53.715 2.143 53.805 2.413 ;
     RECT  56.415 2.143 56.505 2.413 ;
     RECT  59.115 2.143 59.205 2.413 ;
     RECT  61.815 2.143 61.905 2.413 ;
     RECT  64.515 2.143 64.605 2.413 ;
     RECT  67.215 2.143 67.305 2.413 ;
     RECT  69.915 2.143 70.005 2.413 ;
     RECT  72.615 2.143 72.705 2.413 ;
     RECT  75.315 2.143 75.405 2.413 ;
     RECT  78.015 2.143 78.105 2.413 ;
     RECT  80.715 2.143 80.805 2.413 ;
     RECT  83.415 2.143 83.505 2.413 ;
     RECT  83.415 2.413 83.697 2.497 ;
     RECT  64.515 2.413 64.797 2.569 ;
     RECT  86.115 2.371 171.63 2.605 ;
     RECT  82.728 2.497 83.697 2.669 ;
     RECT  85.752 2.605 171.63 2.759 ;
     RECT  85.752 2.759 89.406 2.795 ;
     RECT  85.752 2.795 89.298 3.029 ;
     RECT  76.644 2.497 76.662 3.109 ;
     RECT  90.468 2.759 171.63 3.407 ;
     RECT  74.088 3.115 74.106 3.721 ;
     RECT  90.468 3.407 95.454 3.875 ;
     RECT  85.752 3.029 89.19 3.919 ;
     RECT  90.468 3.875 92.862 3.919 ;
     RECT  75.315 2.413 75.597 3.955 ;
     RECT  76.608 3.109 76.662 3.955 ;
     RECT  94.032 3.875 95.454 4.219 ;
     RECT  96.228 3.407 171.63 4.219 ;
     RECT  85.752 3.919 92.862 4.379 ;
     RECT  64.515 2.569 65.286 4.459 ;
     RECT  72.615 2.413 72.897 4.495 ;
     RECT  73.836 3.721 74.106 4.495 ;
     RECT  78.015 2.413 78.297 4.531 ;
     RECT  94.032 4.219 171.63 4.757 ;
     RECT  94.032 4.757 170.73 4.793 ;
     RECT  83.415 2.669 83.697 4.891 ;
     RECT  84.672 3.271 84.69 4.891 ;
     RECT  171.54 4.757 171.63 4.991 ;
     RECT  71.532 4.963 71.55 4.999 ;
     RECT  72.615 4.495 74.106 4.999 ;
     RECT  71.532 4.999 74.106 5.035 ;
     RECT  83.415 4.891 84.69 5.431 ;
     RECT  171.54 4.991 171.558 5.459 ;
     RECT  94.032 4.793 170.694 5.531 ;
     RECT  67.215 2.413 67.497 5.539 ;
     RECT  68.4 4.261 68.418 5.539 ;
     RECT  83.415 5.431 84.726 5.575 ;
     RECT  85.752 4.379 92.61 5.575 ;
     RECT  94.032 5.531 170.622 5.999 ;
     RECT  64.515 4.459 65.97 6.007 ;
     RECT  94.032 5.999 152.73 6.071 ;
     RECT  63.72 3.145 63.738 6.547 ;
     RECT  75.315 3.955 76.662 6.817 ;
     RECT  63.144 6.547 63.738 7.159 ;
     RECT  64.515 6.007 66.402 7.159 ;
     RECT  67.215 5.539 68.418 7.231 ;
     RECT  83.415 5.575 92.61 7.663 ;
     RECT  75.315 6.817 76.698 7.897 ;
     RECT  69.915 2.413 70.197 8.203 ;
     RECT  70.956 5.035 74.106 8.203 ;
     RECT  83.415 7.663 93.186 8.239 ;
     RECT  94.032 6.071 152.658 8.239 ;
     RECT  75.315 7.897 76.734 8.509 ;
     RECT  153.615 5.999 170.622 8.969 ;
     RECT  67.215 7.231 68.634 9.013 ;
     RECT  69.915 8.203 74.106 9.013 ;
     RECT  78.015 4.531 78.75 9.391 ;
     RECT  61.815 2.413 62.097 9.481 ;
     RECT  63.144 7.159 66.402 9.481 ;
     RECT  162.864 8.969 170.622 10.229 ;
     RECT  165.924 10.229 170.622 11.039 ;
     RECT  165.924 11.039 170.586 11.129 ;
     RECT  165.924 11.129 170.097 11.165 ;
     RECT  67.215 9.013 74.106 11.245 ;
     RECT  74.916 8.509 76.734 11.245 ;
     RECT  83.415 8.239 152.658 11.849 ;
     RECT  67.215 11.245 76.734 12.289 ;
     RECT  77.616 9.391 78.75 12.289 ;
     RECT  67.215 12.289 78.75 12.325 ;
     RECT  79.524 12.253 79.542 12.325 ;
     RECT  80.715 2.413 80.997 12.451 ;
     RECT  83.415 11.849 136.674 12.811 ;
     RECT  137.415 11.849 152.658 12.811 ;
     RECT  61.815 9.481 66.402 12.829 ;
     RECT  67.215 12.325 79.542 12.829 ;
     RECT  81.756 2.533 81.774 13.567 ;
     RECT  81.756 13.567 82.422 13.973 ;
     RECT  80.316 12.451 80.997 14.071 ;
     RECT  83.415 12.811 152.658 14.513 ;
     RECT  82.404 13.973 82.422 14.611 ;
     RECT  83.415 14.513 140.397 14.611 ;
     RECT  153.615 8.969 161.997 15.251 ;
     RECT  165.924 11.165 169.038 15.287 ;
     RECT  59.115 2.413 59.397 15.565 ;
     RECT  2.415 2.413 2.697 15.592 ;
     RECT  5.115 2.413 5.397 15.592 ;
     RECT  10.515 2.413 10.797 15.595 ;
     RECT  2.304 15.592 2.697 15.629 ;
     RECT  5.004 15.592 5.397 15.629 ;
     RECT  6.84 15.499 6.858 15.629 ;
     RECT  153.615 15.251 160.83 15.629 ;
     RECT  21.315 2.413 21.597 15.691 ;
     RECT  26.715 2.413 26.997 15.691 ;
     RECT  58.716 15.565 59.397 15.719 ;
     RECT  141.372 14.513 152.658 15.719 ;
     RECT  15.915 2.413 16.197 15.727 ;
     RECT  21.204 15.691 21.597 15.728 ;
     RECT  10.515 15.595 10.854 15.773 ;
     RECT  15.516 15.727 16.197 15.773 ;
     RECT  26.676 15.691 26.997 15.821 ;
     RECT  15.732 15.773 16.197 15.827 ;
     RECT  30.924 15.787 30.942 15.863 ;
     RECT  159.015 15.629 160.83 15.899 ;
     RECT  149.4 15.719 152.658 16.259 ;
     RECT  166.14 15.287 169.038 16.301 ;
     RECT  80.316 14.071 81.522 16.339 ;
     RECT  82.404 14.611 140.397 16.339 ;
     RECT  160.128 15.899 160.83 16.439 ;
     RECT  61.815 12.829 79.542 16.771 ;
     RECT  80.316 16.339 140.397 16.771 ;
     RECT  153.615 15.629 158.238 16.835 ;
     RECT  154.764 16.835 158.238 16.943 ;
     RECT  167.115 16.301 169.038 17.105 ;
     RECT  154.764 16.943 158.166 17.609 ;
     RECT  168.336 17.105 169.038 17.645 ;
     RECT  166.14 16.301 166.374 17.951 ;
     RECT  149.4 16.259 152.586 17.987 ;
     RECT  154.764 17.609 157.806 18.023 ;
     RECT  149.4 17.987 152.514 18.149 ;
     RECT  160.128 16.439 160.47 18.185 ;
     RECT  141.372 15.719 148.497 18.221 ;
     RECT  154.764 18.023 155.394 18.527 ;
     RECT  160.452 18.185 160.47 18.563 ;
     RECT  162.864 10.229 165.042 18.599 ;
     RECT  61.815 16.771 140.397 18.725 ;
     RECT  149.4 18.149 149.85 18.761 ;
     RECT  61.815 18.725 136.026 18.833 ;
     RECT  162.864 18.599 164.697 19.139 ;
     RECT  156.315 18.023 157.806 19.265 ;
     RECT  149.4 18.761 149.634 19.301 ;
     RECT  136.908 18.725 140.397 19.337 ;
     RECT  156.315 19.265 157.41 19.607 ;
     RECT  141.372 18.221 147.474 19.679 ;
     RECT  150.915 18.149 152.514 19.769 ;
     RECT  168.336 17.645 168.642 19.805 ;
     RECT  162.864 19.139 163.314 19.877 ;
     RECT  149.616 19.301 149.634 19.913 ;
     RECT  154.764 18.527 155.322 19.949 ;
     RECT  155.304 19.949 155.322 20.219 ;
     RECT  168.336 19.805 168.354 20.309 ;
     RECT  166.176 17.951 166.374 20.333 ;
     RECT  141.372 19.679 147.222 20.345 ;
     RECT  141.372 20.345 146.934 20.381 ;
     RECT  150.915 19.769 151.974 20.417 ;
     RECT  146.592 20.381 146.934 20.453 ;
     RECT  166.176 20.333 166.338 20.849 ;
     RECT  166.32 20.849 166.338 20.885 ;
     RECT  156.315 19.607 156.978 20.921 ;
     RECT  163.296 19.877 163.314 20.957 ;
     RECT  150.915 20.417 151.902 20.993 ;
     RECT  146.592 20.453 146.61 21.029 ;
     RECT  136.908 19.337 138.402 21.091 ;
     RECT  136.908 21.091 138.51 21.271 ;
     RECT  61.815 18.833 132.297 21.361 ;
     RECT  133.02 18.833 136.026 21.361 ;
     RECT  139.392 19.337 140.397 21.361 ;
     RECT  141.372 20.381 145.797 21.361 ;
     RECT  136.908 21.271 138.582 21.424 ;
     RECT  136.908 21.424 138.618 21.499 ;
     RECT  61.815 21.361 136.026 21.667 ;
     RECT  136.872 21.499 138.618 21.667 ;
     RECT  139.392 21.361 145.797 21.929 ;
     RECT  61.815 21.667 138.618 22.009 ;
     RECT  139.392 21.929 144.126 22.009 ;
     RECT  61.815 22.009 144.126 22.891 ;
     RECT  144.864 21.929 145.797 22.891 ;
     RECT  61.815 22.891 145.797 24.511 ;
     RECT  46.764 24.667 46.782 24.797 ;
     RECT  54.72 24.667 54.738 24.797 ;
     RECT  61.815 24.511 145.962 25.321 ;
     RECT  61.815 25.321 146.25 25.591 ;
     RECT  46.764 25.963 46.782 26.093 ;
     RECT  54.72 25.963 54.738 26.093 ;
     RECT  61.815 25.591 146.322 26.491 ;
     RECT  61.815 26.491 146.394 26.671 ;
     RECT  61.815 26.671 146.754 27.139 ;
     RECT  61.632 27.139 146.754 27.481 ;
     RECT  61.056 27.481 147.078 27.571 ;
     RECT  61.056 27.571 147.15 27.629 ;
     RECT  61.056 27.629 147.078 27.635 ;
     RECT  2.415 15.629 2.697 27.827 ;
     RECT  5.115 15.629 5.397 27.827 ;
     RECT  7.815 2.413 8.097 27.827 ;
     RECT  10.515 15.773 10.797 27.827 ;
     RECT  13.215 2.413 13.497 27.827 ;
     RECT  15.915 15.827 16.197 27.827 ;
     RECT  18.615 2.413 18.897 27.827 ;
     RECT  21.315 15.728 21.597 27.827 ;
     RECT  24.015 2.413 24.297 27.827 ;
     RECT  26.715 15.821 26.997 27.827 ;
     RECT  29.415 2.413 29.697 27.827 ;
     RECT  32.115 2.413 32.397 27.827 ;
     RECT  34.815 2.413 35.097 27.827 ;
     RECT  37.515 2.413 37.797 27.827 ;
     RECT  40.215 2.413 40.497 27.827 ;
     RECT  42.915 2.413 43.197 27.827 ;
     RECT  45.615 2.413 45.897 27.827 ;
     RECT  48.315 2.413 48.597 27.827 ;
     RECT  51.015 2.413 51.297 27.827 ;
     RECT  53.715 2.413 53.997 27.827 ;
     RECT  56.415 2.413 56.697 27.827 ;
     RECT  59.115 15.719 59.397 27.827 ;
     RECT  148.215 18.221 148.497 27.827 ;
     RECT  150.915 20.993 151.197 27.827 ;
     RECT  153.615 16.835 153.897 27.827 ;
     RECT  156.315 20.921 156.597 27.827 ;
     RECT  159.015 15.899 159.297 27.827 ;
     RECT  161.715 15.251 161.997 27.827 ;
     RECT  164.415 19.139 164.697 27.827 ;
     RECT  167.115 17.105 167.397 27.827 ;
     RECT  169.815 11.165 170.097 27.827 ;
     RECT  61.056 27.635 146.97 27.869 ;
     RECT  116.64 27.869 116.838 27.875 ;
     RECT  61.056 27.869 67.806 27.905 ;
     RECT  104.796 27.869 110.505 27.917 ;
     RECT  68.832 27.869 70.47 27.941 ;
     RECT  74.88 27.869 75.798 27.941 ;
     RECT  76.752 27.869 78.105 27.941 ;
     RECT  79.452 27.869 79.47 27.941 ;
     RECT  82.26 27.869 84.222 27.941 ;
     RECT  85.248 27.869 86.205 27.941 ;
     RECT  88.272 27.869 89.586 27.941 ;
     RECT  93.384 27.869 93.402 27.941 ;
     RECT  94.215 27.869 97.578 27.941 ;
     RECT  98.46 27.869 100.422 27.941 ;
     RECT  101.448 27.869 103.086 27.941 ;
     RECT  103.824 27.869 103.842 27.941 ;
     RECT  104.796 27.917 109.638 27.941 ;
     RECT  111.312 27.869 115.905 27.941 ;
     RECT  117.792 27.869 118.605 27.941 ;
     RECT  122.472 27.869 125.334 27.941 ;
     RECT  126.615 27.869 127.278 27.941 ;
     RECT  130.896 27.869 130.95 27.941 ;
     RECT  131.796 27.869 132.105 27.941 ;
     RECT  133.2 27.869 135.414 27.941 ;
     RECT  138.6 27.869 141.822 27.941 ;
     RECT  142.74 27.869 146.754 27.941 ;
     RECT  82.98 27.941 84.114 27.965 ;
     RECT  125.172 27.941 125.334 27.965 ;
     RECT  128.556 27.869 129.87 27.965 ;
     RECT  130.896 27.941 130.914 27.965 ;
     RECT  133.812 27.941 134.805 27.965 ;
     RECT  140.115 27.941 141.822 27.965 ;
     RECT  91.332 27.869 92.286 27.977 ;
     RECT  2.415 27.827 2.505 28.097 ;
     RECT  5.115 27.827 5.205 28.097 ;
     RECT  7.815 27.827 7.905 28.097 ;
     RECT  10.515 27.827 10.605 28.097 ;
     RECT  13.215 27.827 13.305 28.097 ;
     RECT  15.915 27.827 16.005 28.097 ;
     RECT  18.615 27.827 18.705 28.097 ;
     RECT  21.315 27.827 21.405 28.097 ;
     RECT  24.015 27.827 24.105 28.097 ;
     RECT  26.715 27.827 26.805 28.097 ;
     RECT  29.415 27.827 29.505 28.097 ;
     RECT  32.115 27.827 32.205 28.097 ;
     RECT  34.815 27.827 34.905 28.097 ;
     RECT  37.515 27.827 37.605 28.097 ;
     RECT  40.215 27.827 40.305 28.097 ;
     RECT  42.915 27.827 43.005 28.097 ;
     RECT  45.615 27.827 45.705 28.097 ;
     RECT  48.315 27.827 48.405 28.097 ;
     RECT  51.015 27.827 51.105 28.097 ;
     RECT  53.715 27.827 53.805 28.097 ;
     RECT  56.415 27.827 56.505 28.097 ;
     RECT  59.115 27.827 59.205 28.097 ;
     RECT  69.588 27.941 70.47 28.097 ;
     RECT  71.496 27.869 73.998 28.097 ;
     RECT  74.988 27.941 75.798 28.097 ;
     RECT  78.015 27.941 78.105 28.097 ;
     RECT  80.64 27.869 81.45 28.097 ;
     RECT  82.98 27.965 84.042 28.097 ;
     RECT  85.68 27.941 86.205 28.097 ;
     RECT  88.815 27.941 88.905 28.097 ;
     RECT  94.215 27.941 97.47 28.097 ;
     RECT  98.964 27.941 99.705 28.097 ;
     RECT  110.415 27.917 110.505 28.097 ;
     RECT  113.115 27.941 113.85 28.097 ;
     RECT  115.815 27.941 115.905 28.097 ;
     RECT  118.26 27.941 118.605 28.097 ;
     RECT  121.104 27.869 121.305 28.097 ;
     RECT  122.76 27.941 124.005 28.097 ;
     RECT  126.615 27.941 127.026 28.097 ;
     RECT  128.556 27.965 129.405 28.097 ;
     RECT  132.015 27.941 132.105 28.097 ;
     RECT  134.316 27.965 134.805 28.097 ;
     RECT  136.512 27.869 137.505 28.097 ;
     RECT  140.115 27.965 141.642 28.097 ;
     RECT  148.215 27.827 148.305 28.097 ;
     RECT  150.915 27.827 151.005 28.097 ;
     RECT  153.615 27.827 153.705 28.097 ;
     RECT  156.315 27.827 156.405 28.097 ;
     RECT  159.015 27.827 159.105 28.097 ;
     RECT  161.715 27.827 161.805 28.097 ;
     RECT  164.415 27.827 164.505 28.097 ;
     RECT  167.115 27.827 167.205 28.097 ;
     RECT  169.815 27.827 169.905 28.097 ;
     RECT  140.544 28.097 141.642 28.205 ;
     RECT  142.74 27.941 143.19 28.205 ;
     RECT  83.772 28.097 84.042 28.253 ;
     RECT  102.24 27.941 103.086 28.253 ;
     RECT  121.104 28.097 121.122 28.253 ;
     RECT  122.76 28.097 123.714 28.253 ;
     RECT  142.74 28.205 142.758 28.253 ;
     RECT  122.76 28.253 123.39 28.301 ;
     RECT  143.964 27.941 146.286 28.301 ;
     RECT  116.64 27.875 116.802 28.349 ;
     RECT  134.316 28.097 134.694 28.349 ;
     RECT  146.088 28.301 146.286 28.349 ;
     RECT  146.268 28.349 146.286 28.397 ;
     RECT  61.668 27.905 67.806 28.493 ;
     RECT  77.22 27.941 77.238 28.493 ;
     RECT  94.608 28.097 96.354 28.493 ;
     RECT  102.24 28.253 102.834 28.493 ;
     RECT  116.64 28.349 116.658 28.493 ;
     RECT  119.808 27.869 120.258 28.493 ;
     RECT  143.964 28.301 145.206 28.493 ;
     RECT  71.496 28.097 72.414 28.541 ;
     RECT  74.988 28.097 75.006 28.541 ;
     RECT  75.78 28.097 75.798 28.541 ;
     RECT  84.024 28.253 84.042 28.541 ;
     RECT  85.68 28.097 85.698 28.541 ;
     RECT  87.444 27.869 87.462 28.541 ;
     RECT  90.504 27.869 90.522 28.541 ;
     RECT  91.332 27.977 92.07 28.541 ;
     RECT  94.608 28.493 95.346 28.541 ;
     RECT  96.336 28.493 96.354 28.541 ;
     RECT  97.452 28.097 97.47 28.541 ;
     RECT  98.964 28.097 99.054 28.541 ;
     RECT  104.94 27.941 105.75 28.541 ;
     RECT  107.1 27.941 109.422 28.541 ;
     RECT  111.312 27.941 111.33 28.541 ;
     RECT  118.26 28.097 118.278 28.541 ;
     RECT  123.372 28.301 123.39 28.541 ;
     RECT  125.172 27.965 125.298 28.541 ;
     RECT  128.556 28.097 129.078 28.541 ;
     RECT  136.512 28.097 137.286 28.541 ;
     RECT  139.212 27.941 139.374 28.541 ;
     RECT  140.616 28.205 141.642 28.541 ;
     RECT  125.28 28.541 125.298 28.589 ;
     RECT  128.808 28.541 128.826 28.589 ;
     RECT  71.532 28.541 71.802 28.637 ;
     RECT  73.26 28.097 73.998 28.637 ;
     RECT  94.608 28.541 94.626 28.637 ;
     RECT  109.368 28.541 109.422 28.685 ;
     RECT  109.368 28.685 109.386 28.877 ;
     RECT  139.212 28.541 139.23 28.877 ;
     RECT  107.1 28.541 108.45 29.021 ;
     RECT  70.452 28.097 70.47 29.029 ;
     RECT  80.64 28.097 80.658 29.029 ;
     RECT  81.432 28.097 81.45 29.029 ;
     RECT  113.832 28.097 113.85 29.029 ;
     RECT  70.38 29.029 70.47 29.057 ;
     RECT  80.64 29.029 81.45 29.057 ;
     RECT  104.94 28.541 105.714 29.057 ;
     RECT  113.616 29.029 113.85 29.057 ;
     RECT  61.668 28.493 63.954 29.069 ;
     RECT  66.78 28.493 67.806 29.069 ;
     RECT  69.588 28.097 69.606 29.069 ;
     RECT  71.784 28.637 71.802 29.069 ;
     RECT  99.036 28.541 99.054 29.069 ;
     RECT  102.24 28.493 102.258 29.069 ;
     RECT  105.372 29.057 105.714 29.069 ;
     RECT  107.1 29.021 108.27 29.069 ;
     RECT  112.356 27.941 112.374 29.069 ;
     RECT  114.804 27.941 114.822 29.069 ;
     RECT  127.008 28.097 127.026 29.069 ;
     RECT  136.62 28.541 137.286 29.069 ;
     RECT  140.76 28.541 141.102 29.069 ;
     RECT  65.088 28.493 66.006 29.117 ;
     RECT  107.1 29.069 107.118 29.117 ;
     RECT  134.316 28.349 134.334 29.117 ;
     RECT  62.496 29.069 63.954 29.645 ;
     RECT  65.088 29.117 65.466 29.645 ;
     RECT  67.608 29.069 67.806 29.645 ;
     RECT  68.832 27.941 68.85 29.645 ;
     RECT  73.26 28.637 73.278 29.645 ;
     RECT  80.64 29.057 81.27 29.645 ;
     RECT  82.98 28.097 82.998 29.645 ;
     RECT  92.052 28.541 92.07 29.645 ;
     RECT  143.964 28.493 144.846 29.645 ;
     RECT  62.496 29.645 63.234 29.693 ;
     RECT  67.608 29.645 67.698 29.693 ;
     RECT  113.616 29.057 113.634 29.693 ;
     RECT  119.808 28.493 119.826 29.693 ;
     RECT  62.496 29.693 62.694 29.741 ;
     RECT  61.668 29.069 61.686 29.789 ;
     RECT  69.336 29.659 69.354 29.837 ;
     RECT  77.544 29.659 77.562 29.837 ;
     RECT  86.616 28.939 86.634 29.899 ;
     RECT  85.896 29.899 86.634 30.077 ;
     RECT  112.824 29.083 112.842 30.077 ;
     RECT  124.596 29.899 124.614 30.077 ;
     RECT  62.496 29.741 62.514 30.125 ;
     RECT  65.088 29.645 65.106 30.125 ;
     RECT  66.78 29.069 66.798 30.125 ;
     RECT  67.608 29.693 67.626 30.125 ;
     RECT  70.38 29.057 70.398 30.125 ;
     RECT  80.64 29.645 80.658 30.125 ;
     RECT  86.04 30.077 86.058 30.125 ;
     RECT  97.848 29.947 97.866 30.125 ;
     RECT  105.372 29.069 105.39 30.125 ;
     RECT  140.58 30.043 140.598 30.173 ;
     RECT  144.828 29.645 144.846 30.173 ;
     RECT  143.964 29.645 143.982 30.221 ;
    LAYER M4 ;
     RECT  0.181 21.168 2.408 21.192 ;
     RECT  2.408 2.148 2.512 28.092 ;
     RECT  2.512 2.418 2.704 27.822 ;
     RECT  2.704 15.6 5.108 15.624 ;
     RECT  2.704 21.168 5.108 21.192 ;
     RECT  5.108 2.148 5.212 28.092 ;
     RECT  5.212 2.418 5.404 27.822 ;
     RECT  5.404 15.6 6.829 15.624 ;
     RECT  6.829 15.504 7.808 15.624 ;
     RECT  5.404 21.168 7.808 21.192 ;
     RECT  7.808 2.148 7.912 28.092 ;
     RECT  7.912 2.418 8.104 27.822 ;
     RECT  8.104 15.504 10.508 15.528 ;
     RECT  8.104 21.168 10.508 21.192 ;
     RECT  10.508 2.148 10.612 28.092 ;
     RECT  10.612 2.418 10.804 27.822 ;
     RECT  10.804 15.6 10.865 15.768 ;
     RECT  10.865 15.744 13.208 15.768 ;
     RECT  10.804 21.168 13.208 21.192 ;
     RECT  13.208 2.148 13.312 28.092 ;
     RECT  13.312 2.418 13.504 27.822 ;
     RECT  13.504 15.744 15.721 15.768 ;
     RECT  15.721 15.744 15.908 15.816 ;
     RECT  13.504 21.168 15.908 21.192 ;
     RECT  15.908 2.148 16.012 28.092 ;
     RECT  16.012 2.418 16.204 27.822 ;
     RECT  16.204 15.792 18.608 15.816 ;
     RECT  16.204 21.168 18.608 21.192 ;
     RECT  18.608 2.148 18.712 28.092 ;
     RECT  18.712 2.418 18.904 27.822 ;
     RECT  18.904 15.696 21.308 15.72 ;
     RECT  18.904 21.168 21.308 21.192 ;
     RECT  21.308 2.148 21.412 28.092 ;
     RECT  21.412 2.418 21.604 27.822 ;
     RECT  21.604 15.696 23.893 15.72 ;
     RECT  23.893 15.696 24.008 15.816 ;
     RECT  21.604 21.168 24.008 21.192 ;
     RECT  24.008 2.148 24.112 28.092 ;
     RECT  24.112 2.418 24.304 27.822 ;
     RECT  24.304 15.792 26.708 15.816 ;
     RECT  24.304 21.168 26.708 21.192 ;
     RECT  26.708 2.148 26.812 28.092 ;
     RECT  26.812 2.418 27.004 27.822 ;
     RECT  27.004 15.792 29.408 15.816 ;
     RECT  27.004 21.168 29.408 21.192 ;
     RECT  29.408 2.148 29.512 28.092 ;
     RECT  29.512 2.418 29.704 27.822 ;
     RECT  29.704 15.792 30.953 15.816 ;
     RECT  29.704 21.168 32.108 21.192 ;
     RECT  32.108 2.148 32.212 28.092 ;
     RECT  32.212 2.418 32.404 27.822 ;
     RECT  32.404 21.168 34.808 21.192 ;
     RECT  34.808 2.148 34.912 28.092 ;
     RECT  34.912 2.418 35.104 27.822 ;
     RECT  35.104 21.168 37.508 21.192 ;
     RECT  37.508 2.148 37.612 28.092 ;
     RECT  37.612 2.418 37.804 27.822 ;
     RECT  37.804 21.168 40.208 21.192 ;
     RECT  40.208 2.148 40.312 28.092 ;
     RECT  40.312 2.418 40.504 27.822 ;
     RECT  40.504 21.168 42.908 21.192 ;
     RECT  42.037 24.912 42.908 24.936 ;
     RECT  42.181 26.064 42.908 26.088 ;
     RECT  42.908 2.148 43.012 28.092 ;
     RECT  43.012 2.418 43.204 27.822 ;
     RECT  43.204 21.168 45.608 21.192 ;
     RECT  43.204 24.912 45.608 26.088 ;
     RECT  45.608 2.148 45.712 28.092 ;
     RECT  45.712 2.418 45.904 27.822 ;
     RECT  45.904 21.168 48.308 21.192 ;
     RECT  45.904 24.672 48.308 26.088 ;
     RECT  48.308 2.148 48.412 28.092 ;
     RECT  48.412 2.418 48.604 27.822 ;
     RECT  48.604 21.168 51.008 21.192 ;
     RECT  48.604 24.672 51.008 26.088 ;
     RECT  51.008 2.148 51.112 28.092 ;
     RECT  51.112 2.418 51.304 27.822 ;
     RECT  51.304 21.168 53.708 21.192 ;
     RECT  51.304 24.672 53.708 26.088 ;
     RECT  53.708 2.148 53.812 28.092 ;
     RECT  53.812 2.418 54.004 27.822 ;
     RECT  54.004 21.168 56.408 21.192 ;
     RECT  54.004 24.672 56.408 26.088 ;
     RECT  56.408 2.148 56.512 28.092 ;
     RECT  56.512 2.418 56.704 27.822 ;
     RECT  56.704 21.168 59.108 21.192 ;
     RECT  56.704 24.672 59.108 26.088 ;
     RECT  59.108 2.148 59.212 28.092 ;
     RECT  59.212 2.418 59.404 27.822 ;
     RECT  59.404 21.168 61.808 21.192 ;
     RECT  59.404 24.672 61.808 26.088 ;
     RECT  61.808 2.148 61.912 28.092 ;
     RECT  61.912 2.418 62.104 28.056 ;
     RECT  61.657 29.76 62.269 29.784 ;
     RECT  62.269 29.04 62.485 29.784 ;
     RECT  62.485 29.04 62.723 30.12 ;
     RECT  62.723 29.04 63.011 29.784 ;
     RECT  62.104 27.36 63.203 28.056 ;
     RECT  62.104 24.624 63.241 26.088 ;
     RECT  63.011 29.04 63.299 29.688 ;
     RECT  63.299 29.616 63.395 29.688 ;
     RECT  63.203 27.84 63.541 28.056 ;
     RECT  63.241 24.48 63.836 26.088 ;
     RECT  62.104 21.168 63.853 21.192 ;
     RECT  63.529 22.752 63.853 22.776 ;
     RECT  63.836 24.48 63.853 26.856 ;
     RECT  63.395 29.616 63.965 29.64 ;
     RECT  63.853 21.168 64.508 26.856 ;
     RECT  63.541 27.84 64.508 28.488 ;
     RECT  64.508 2.148 64.612 28.488 ;
     RECT  64.612 2.418 64.804 28.488 ;
     RECT  64.804 21.168 64.865 22.824 ;
     RECT  64.981 30.096 65.117 30.12 ;
     RECT  64.804 27.936 65.125 28.488 ;
     RECT  65.125 27.936 65.269 29.064 ;
     RECT  65.269 27.936 65.477 29.64 ;
     RECT  65.477 27.936 66.035 29.112 ;
     RECT  66.035 27.936 66.997 28.488 ;
     RECT  64.804 24.624 67.045 26.088 ;
     RECT  64.865 21.168 67.165 22.776 ;
     RECT  66.997 27.936 67.169 29.064 ;
     RECT  67.169 27.936 67.187 28.248 ;
     RECT  65.905 14.496 67.208 14.52 ;
     RECT  67.165 21.168 67.208 22.824 ;
     RECT  67.045 24.624 67.208 26.568 ;
     RECT  67.187 27.936 67.208 28.092 ;
     RECT  67.208 2.148 67.312 28.092 ;
     RECT  66.709 30.096 67.429 30.12 ;
     RECT  67.312 2.418 67.504 27.822 ;
     RECT  67.504 21.168 67.601 22.824 ;
     RECT  67.429 29.616 67.637 30.12 ;
     RECT  67.637 29.616 67.763 29.688 ;
     RECT  67.504 23.904 68.357 27.48 ;
     RECT  67.601 21.168 68.537 22.68 ;
     RECT  68.537 21.168 68.867 22.2 ;
     RECT  68.357 24.528 69.157 27.48 ;
     RECT  67.763 29.616 69.281 29.64 ;
     RECT  69.281 29.616 69.301 29.832 ;
     RECT  69.157 24.528 69.433 27.528 ;
     RECT  69.301 29.568 69.577 29.832 ;
     RECT  69.577 29.04 69.661 29.832 ;
     RECT  67.504 14.496 69.908 14.52 ;
     RECT  68.867 21.168 69.908 22.056 ;
     RECT  69.493 23.376 69.908 23.4 ;
     RECT  69.433 24.384 69.908 27.528 ;
     RECT  69.908 2.148 70.012 28.092 ;
     RECT  70.012 2.418 70.204 27.822 ;
     RECT  69.685 29.952 70.309 30.072 ;
     RECT  70.309 29.952 70.355 30.12 ;
     RECT  70.355 30.048 70.409 30.12 ;
     RECT  71.317 28.512 71.461 28.536 ;
     RECT  70.204 24.048 71.593 26.856 ;
     RECT  70.204 21.168 71.612 22.776 ;
     RECT  71.593 24.048 71.612 27.528 ;
     RECT  71.461 28.512 71.729 28.632 ;
     RECT  71.729 28.512 71.813 29.064 ;
     RECT  71.612 21.168 71.941 27.528 ;
     RECT  71.813 28.512 71.941 28.536 ;
     RECT  70.409 30.048 72.085 30.072 ;
     RECT  70.204 14.496 72.608 14.52 ;
     RECT  71.941 21.168 72.608 28.536 ;
     RECT  72.608 2.148 72.659 28.536 ;
     RECT  72.659 2.148 72.712 28.2 ;
     RECT  72.712 2.418 72.904 28.2 ;
     RECT  72.904 24.384 72.965 27.048 ;
     RECT  72.085 30 73.045 30.072 ;
     RECT  73.045 29.616 73.289 30.072 ;
     RECT  72.904 21.168 73.763 23.4 ;
     RECT  72.965 24.528 73.865 27.048 ;
     RECT  73.621 28.512 73.909 28.536 ;
     RECT  73.909 28.512 74.009 28.632 ;
     RECT  74.069 19.92 74.153 19.944 ;
     RECT  73.865 24.528 74.197 26.856 ;
     RECT  73.289 30.048 74.627 30.072 ;
     RECT  73.763 21.168 74.725 23.112 ;
     RECT  74.197 24.336 74.725 26.856 ;
     RECT  74.009 28.512 74.965 28.536 ;
     RECT  74.725 21.168 75.085 26.856 ;
     RECT  74.965 28.176 75.085 28.536 ;
     RECT  74.077 3.12 75.308 3.144 ;
     RECT  72.904 11.664 75.308 11.688 ;
     RECT  72.904 14.496 75.308 14.52 ;
     RECT  75.157 20.112 75.308 20.136 ;
     RECT  75.085 21.168 75.308 28.536 ;
     RECT  75.308 2.148 75.412 28.536 ;
     RECT  75.412 2.418 75.604 28.536 ;
     RECT  75.604 21.168 75.809 28.536 ;
     RECT  75.809 21.168 75.923 27.576 ;
     RECT  75.923 21.168 76.211 27 ;
     RECT  76.211 21.168 77.173 26.232 ;
     RECT  76.885 27.36 77.173 27.384 ;
     RECT  76.933 28.464 77.249 28.488 ;
     RECT  75.637 30.048 77.489 30.072 ;
     RECT  77.489 29.808 77.509 30.072 ;
     RECT  77.173 21.168 77.797 27.384 ;
     RECT  77.509 29.568 77.843 30.072 ;
     RECT  77.797 21.168 77.987 28.248 ;
     RECT  75.604 3.12 78.008 3.144 ;
     RECT  75.604 11.664 78.008 11.688 ;
     RECT  75.604 14.496 78.008 14.52 ;
     RECT  77.987 21.168 78.008 28.092 ;
     RECT  78.008 2.148 78.112 28.092 ;
     RECT  78.112 2.418 78.304 27.822 ;
     RECT  77.843 30 78.611 30.072 ;
     RECT  78.304 21.168 78.653 27.384 ;
     RECT  78.653 21.168 79.381 27.192 ;
     RECT  78.611 30.048 79.813 30.072 ;
     RECT  79.813 29.904 80.003 30.072 ;
     RECT  80.003 30 80.389 30.072 ;
     RECT  80.389 30 80.669 30.12 ;
     RECT  78.304 3.12 80.708 3.144 ;
     RECT  78.304 11.664 80.708 11.688 ;
     RECT  78.304 14.496 80.708 14.52 ;
     RECT  79.693 19.008 80.708 19.032 ;
     RECT  79.381 21.168 80.708 26.856 ;
     RECT  80.708 2.148 80.812 28.092 ;
     RECT  80.812 2.418 81.004 27.822 ;
     RECT  80.669 30 81.109 30.072 ;
     RECT  81.109 29.616 81.251 30.072 ;
     RECT  81.251 29.616 81.281 29.64 ;
     RECT  81.004 21.168 82.861 27.384 ;
     RECT  82.453 30.048 82.969 30.072 ;
     RECT  82.969 29.616 83.053 30.072 ;
     RECT  81.004 3.12 83.408 3.144 ;
     RECT  81.004 11.664 83.408 11.688 ;
     RECT  81.004 14.496 83.408 14.52 ;
     RECT  81.004 17.424 83.408 17.448 ;
     RECT  81.004 19.008 83.408 19.032 ;
     RECT  82.861 21.168 83.408 27.672 ;
     RECT  83.408 2.148 83.413 28.092 ;
     RECT  83.413 2.148 83.512 28.248 ;
     RECT  83.512 2.418 83.704 28.248 ;
     RECT  83.704 21.168 83.845 28.248 ;
     RECT  83.845 21.168 83.987 29.064 ;
     RECT  83.987 21.168 84.076 28.536 ;
     RECT  84.076 21.168 84.179 27.96 ;
     RECT  84.179 21.168 84.197 27.192 ;
     RECT  83.704 19.008 85.201 19.032 ;
     RECT  84.197 21.168 85.409 26.856 ;
     RECT  83.053 30.048 85.868 30.072 ;
     RECT  85.868 29.904 86.005 30.072 ;
     RECT  86.005 29.904 86.092 30.12 ;
     RECT  83.704 3.12 86.108 3.144 ;
     RECT  83.704 11.664 86.108 11.688 ;
     RECT  83.704 14.496 86.108 14.52 ;
     RECT  83.704 17.424 86.108 17.448 ;
     RECT  85.201 19.008 86.108 19.08 ;
     RECT  85.409 21.168 86.108 27.384 ;
     RECT  85.573 28.512 86.108 28.536 ;
     RECT  86.108 2.148 86.212 28.536 ;
     RECT  86.212 2.418 86.404 27.822 ;
     RECT  86.092 29.904 86.437 30.072 ;
     RECT  86.404 19.008 86.501 19.128 ;
     RECT  86.437 29.856 86.605 30.072 ;
     RECT  86.605 28.944 86.627 30.072 ;
     RECT  86.627 30.048 86.668 30.072 ;
     RECT  86.404 21.168 86.675 27.48 ;
     RECT  86.404 17.328 86.681 17.448 ;
     RECT  86.627 28.944 86.867 29.064 ;
     RECT  87.301 28.512 87.473 28.536 ;
     RECT  86.675 21.168 87.637 27.384 ;
     RECT  86.404 3.12 87.757 3.144 ;
     RECT  87.637 21.168 87.779 27.96 ;
     RECT  87.749 0.576 87.833 0.6 ;
     RECT  87.829 1.776 87.893 1.8 ;
     RECT  87.893 1.728 87.973 1.8 ;
     RECT  87.973 1.056 88.513 1.8 ;
     RECT  87.757 2.784 88.513 3.144 ;
     RECT  88.513 1.056 88.547 3.144 ;
     RECT  88.597 29.952 88.645 30.072 ;
     RECT  88.547 1.104 88.808 3.144 ;
     RECT  86.404 11.664 88.808 11.688 ;
     RECT  86.404 14.496 88.808 14.52 ;
     RECT  86.681 17.424 88.808 17.448 ;
     RECT  86.501 19.056 88.808 19.128 ;
     RECT  87.779 21.168 88.808 27.384 ;
     RECT  88.645 29.856 88.931 30.072 ;
     RECT  88.808 1.104 89.029 28.092 ;
     RECT  89.029 1.104 89.104 28.2 ;
     RECT  89.104 1.104 89.123 3.144 ;
     RECT  89.104 28.176 89.219 28.2 ;
     RECT  89.123 1.728 89.267 3.144 ;
     RECT  88.931 30.048 89.459 30.072 ;
     RECT  89.377 0.096 89.555 0.12 ;
     RECT  89.267 1.728 90.065 1.752 ;
     RECT  89.104 21.168 90.205 26.664 ;
     RECT  90.205 21.168 90.371 27.48 ;
     RECT  90.325 29.04 90.467 29.064 ;
     RECT  89.104 19.056 90.637 19.128 ;
     RECT  90.881 1.152 90.965 1.176 ;
     RECT  89.267 3.12 90.997 3.144 ;
     RECT  90.997 0.096 91.091 0.12 ;
     RECT  90.997 3.12 91.213 3.72 ;
     RECT  91.213 3.12 91.508 3.96 ;
     RECT  89.104 7.104 91.508 7.176 ;
     RECT  89.104 11.664 91.508 11.688 ;
     RECT  89.104 14.496 91.508 14.52 ;
     RECT  89.104 17.424 91.508 17.448 ;
     RECT  90.637 19.008 91.508 19.128 ;
     RECT  90.371 21.168 91.508 27.384 ;
     RECT  90.469 28.512 91.508 28.536 ;
     RECT  91.508 2.148 91.667 28.536 ;
     RECT  91.667 2.148 91.804 27.822 ;
     RECT  91.804 2.148 91.933 3.96 ;
     RECT  90.613 30.048 92.041 30.072 ;
     RECT  92.185 0.096 92.483 0.12 ;
     RECT  92.041 29.616 92.629 30.072 ;
     RECT  91.933 1.728 92.693 3.96 ;
     RECT  91.804 21.168 92.771 27.384 ;
     RECT  92.629 29.04 92.819 30.072 ;
     RECT  92.693 1.728 92.915 3.144 ;
     RECT  92.771 21.168 94.057 26.856 ;
     RECT  92.915 1.728 94.208 1.848 ;
     RECT  92.915 3.12 94.208 3.144 ;
     RECT  91.804 7.104 94.208 7.176 ;
     RECT  91.804 11.664 94.208 11.688 ;
     RECT  91.804 14.496 94.208 14.52 ;
     RECT  91.804 17.424 94.208 17.448 ;
     RECT  91.804 19.008 94.208 19.08 ;
     RECT  94.057 21.168 94.208 26.952 ;
     RECT  94.208 1.728 94.213 28.092 ;
     RECT  94.213 1.728 94.501 28.632 ;
     RECT  92.819 29.952 94.501 30.072 ;
     RECT  94.501 1.728 94.504 30.072 ;
     RECT  94.453 0.288 94.597 0.312 ;
     RECT  94.504 1.728 94.597 3.144 ;
     RECT  94.504 19.008 94.609 19.128 ;
     RECT  94.597 0.096 94.673 3.144 ;
     RECT  94.673 1.152 94.684 3.144 ;
     RECT  94.673 0.096 94.745 0.12 ;
     RECT  94.504 21.168 94.835 30.072 ;
     RECT  94.835 28.512 94.931 30.072 ;
     RECT  94.931 29.952 95.075 30.072 ;
     RECT  95.075 29.952 95.123 29.976 ;
     RECT  94.931 28.512 95.357 28.536 ;
     RECT  94.684 1.728 95.641 3.144 ;
     RECT  95.641 1.728 95.929 3.384 ;
     RECT  96.085 30.048 96.133 30.072 ;
     RECT  95.941 28.464 96.325 28.488 ;
     RECT  95.929 1.728 96.908 4.248 ;
     RECT  94.504 7.104 96.908 7.176 ;
     RECT  95.677 8.784 96.908 8.808 ;
     RECT  94.504 11.664 96.908 11.688 ;
     RECT  94.504 14.496 96.908 14.52 ;
     RECT  94.504 17.328 96.908 17.352 ;
     RECT  94.609 19.056 96.908 19.128 ;
     RECT  94.835 21.168 96.908 26.856 ;
     RECT  96.325 28.464 96.908 28.536 ;
     RECT  96.133 29.952 96.949 30.072 ;
     RECT  96.908 1.728 97.204 28.536 ;
     RECT  97.204 21.168 97.481 28.536 ;
     RECT  97.481 21.168 97.625 27.768 ;
     RECT  97.625 21.168 97.669 27.432 ;
     RECT  96.949 29.808 97.793 30.072 ;
     RECT  97.793 29.808 97.877 30.12 ;
     RECT  97.877 29.808 98.245 30.072 ;
     RECT  97.204 17.328 98.593 17.352 ;
     RECT  98.593 17.328 98.633 17.448 ;
     RECT  98.245 28.944 98.677 30.072 ;
     RECT  97.669 21.168 99.277 26.808 ;
     RECT  99.277 21.168 99.397 27.384 ;
     RECT  98.677 28.512 99.397 30.072 ;
     RECT  99.397 21.168 99.443 30.072 ;
     RECT  99.397 0.144 99.565 0.168 ;
     RECT  97.204 1.728 99.608 4.248 ;
     RECT  97.204 7.104 99.608 7.176 ;
     RECT  97.204 8.784 99.608 8.808 ;
     RECT  97.204 11.664 99.608 11.688 ;
     RECT  97.204 14.496 99.608 14.52 ;
     RECT  99.565 16.272 99.608 16.296 ;
     RECT  98.633 17.424 99.608 17.448 ;
     RECT  97.204 19.056 99.608 19.128 ;
     RECT  99.443 21.168 99.608 28.092 ;
     RECT  99.565 0.144 99.683 0.552 ;
     RECT  99.608 1.728 99.712 28.092 ;
     RECT  99.443 30 99.731 30.072 ;
     RECT  99.683 0.528 99.827 0.552 ;
     RECT  99.712 1.728 99.904 27.822 ;
     RECT  99.731 30.048 100.067 30.072 ;
     RECT  99.904 20.304 100.115 27.576 ;
     RECT  99.904 1.728 100.685 4.248 ;
     RECT  100.115 20.304 101.123 27.144 ;
     RECT  100.685 2.064 101.653 4.248 ;
     RECT  101.123 20.304 102.085 26.856 ;
     RECT  101.365 27.84 102.085 27.864 ;
     RECT  101.317 30.048 102.085 30.072 ;
     RECT  102.085 30 102.133 30.072 ;
     RECT  102.133 29.04 102.269 30.072 ;
     RECT  101.653 1.728 102.308 4.248 ;
     RECT  101.113 5.472 102.308 5.496 ;
     RECT  99.904 7.104 102.308 7.176 ;
     RECT  99.904 8.784 102.308 8.808 ;
     RECT  99.904 11.664 102.308 11.688 ;
     RECT  99.904 14.496 102.308 14.52 ;
     RECT  99.904 16.272 102.308 16.296 ;
     RECT  99.904 17.424 102.308 17.448 ;
     RECT  99.904 19.056 102.308 19.128 ;
     RECT  102.085 20.304 102.308 27.864 ;
     RECT  102.269 30 102.323 30.072 ;
     RECT  102.181 0.144 102.419 0.168 ;
     RECT  102.308 1.728 102.604 28.488 ;
     RECT  102.323 30 102.611 30.024 ;
     RECT  102.604 20.304 102.809 28.488 ;
     RECT  102.809 27.36 102.845 28.488 ;
     RECT  102.845 27.36 103.097 28.248 ;
     RECT  103.097 27.36 103.637 27.384 ;
     RECT  102.809 20.304 104.065 26.328 ;
     RECT  104.029 27.312 104.065 27.336 ;
     RECT  104.053 29.04 104.195 29.064 ;
     RECT  103.717 30.048 104.581 30.072 ;
     RECT  104.065 20.304 104.677 27.336 ;
     RECT  102.604 16.272 104.821 16.296 ;
     RECT  104.581 29.952 104.867 30.072 ;
     RECT  102.604 1.728 105.008 4.248 ;
     RECT  102.604 5.472 105.008 5.496 ;
     RECT  102.604 7.104 105.008 7.176 ;
     RECT  102.604 8.784 105.008 8.808 ;
     RECT  102.604 11.664 105.008 11.688 ;
     RECT  102.604 14.496 105.008 14.52 ;
     RECT  104.821 16.272 105.008 16.344 ;
     RECT  102.604 17.328 105.008 17.352 ;
     RECT  102.604 19.056 105.008 19.128 ;
     RECT  104.677 20.304 105.008 27.384 ;
     RECT  104.869 28.368 105.008 28.488 ;
     RECT  104.867 30.048 105.157 30.072 ;
     RECT  105.008 1.728 105.304 28.488 ;
     RECT  105.304 28.368 105.347 28.488 ;
     RECT  105.157 30.048 105.401 30.12 ;
     RECT  105.401 30.048 105.443 30.072 ;
     RECT  105.304 12.768 105.581 13.08 ;
     RECT  105.445 28.512 105.589 28.536 ;
     RECT  105.304 18.816 105.725 19.128 ;
     RECT  105.589 28.512 105.761 29.064 ;
     RECT  105.304 20.304 106.513 26.664 ;
     RECT  105.725 19.008 106.625 19.128 ;
     RECT  106.513 20.112 106.625 26.664 ;
     RECT  105.304 14.496 106.657 14.52 ;
     RECT  106.625 20.304 106.693 26.664 ;
     RECT  106.549 29.328 107.084 29.352 ;
     RECT  107.084 29.088 107.269 29.352 ;
     RECT  107.269 29.04 107.509 29.352 ;
     RECT  105.304 17.328 107.593 17.352 ;
     RECT  105.304 1.728 107.633 4.248 ;
     RECT  107.633 1.824 107.708 4.248 ;
     RECT  105.304 5.472 107.708 5.496 ;
     RECT  105.304 7.104 107.708 7.176 ;
     RECT  105.304 8.784 107.708 8.808 ;
     RECT  105.304 11.664 107.708 11.688 ;
     RECT  105.581 12.768 107.708 12.84 ;
     RECT  106.657 14.496 107.708 14.856 ;
     RECT  105.304 16.272 107.708 16.344 ;
     RECT  107.593 17.328 107.708 17.448 ;
     RECT  106.625 19.008 107.708 19.08 ;
     RECT  106.693 20.304 107.708 26.76 ;
     RECT  107.509 29.04 107.708 30.072 ;
     RECT  107.509 0.144 107.747 0.168 ;
     RECT  107.708 1.824 108.004 30.072 ;
     RECT  108.004 20.304 108.131 30.072 ;
     RECT  108.004 1.824 108.709 4.248 ;
     RECT  108.131 20.304 108.713 29.352 ;
     RECT  108.709 1.728 108.745 4.248 ;
     RECT  108.745 1.104 108.899 4.248 ;
     RECT  108.713 20.304 109.253 27.192 ;
     RECT  108.713 28.512 109.433 29.352 ;
     RECT  109.433 28.944 109.573 29.352 ;
     RECT  109.253 21.504 109.997 27.192 ;
     RECT  109.573 28.944 110.003 30.072 ;
     RECT  108.899 1.728 110.408 4.248 ;
     RECT  108.004 5.472 110.408 5.496 ;
     RECT  108.004 7.104 110.408 7.176 ;
     RECT  108.004 8.784 110.408 8.808 ;
     RECT  108.004 11.664 110.408 11.688 ;
     RECT  108.004 12.768 110.408 12.84 ;
     RECT  108.004 14.496 110.408 14.52 ;
     RECT  108.004 16.272 110.408 16.344 ;
     RECT  108.004 17.424 110.408 17.448 ;
     RECT  108.004 19.008 110.408 19.08 ;
     RECT  109.253 20.304 110.408 20.376 ;
     RECT  109.997 21.504 110.408 27.912 ;
     RECT  110.408 1.728 110.704 28.2 ;
     RECT  110.245 0.144 110.819 0.168 ;
     RECT  110.704 28.176 110.963 28.2 ;
     RECT  110.003 29.328 111.301 30.072 ;
     RECT  111.301 28.512 111.491 30.072 ;
     RECT  110.704 12.768 112.061 12.84 ;
     RECT  110.704 21.504 112.769 27.144 ;
     RECT  110.704 20.304 112.849 20.376 ;
     RECT  112.769 21.504 112.849 27.384 ;
     RECT  111.491 28.944 112.917 30.072 ;
     RECT  110.704 1.728 112.997 4.248 ;
     RECT  110.704 17.424 113.065 17.448 ;
     RECT  112.997 1.776 113.108 4.248 ;
     RECT  110.704 5.472 113.108 5.496 ;
     RECT  110.704 7.104 113.108 7.176 ;
     RECT  110.704 8.784 113.108 8.808 ;
     RECT  110.704 11.664 113.108 11.688 ;
     RECT  112.061 12.768 113.108 12.792 ;
     RECT  110.704 14.496 113.108 14.52 ;
     RECT  110.704 16.272 113.108 16.344 ;
     RECT  113.065 17.376 113.108 17.448 ;
     RECT  110.704 19.008 113.108 19.08 ;
     RECT  112.849 20.304 113.108 27.384 ;
     RECT  113.108 1.776 113.404 28.2 ;
     RECT  113.404 21.408 113.651 28.2 ;
     RECT  112.917 29.328 113.699 30.072 ;
     RECT  113.404 12.768 113.789 12.792 ;
     RECT  113.404 1.776 114.037 4.248 ;
     RECT  113.404 18.816 114.545 19.128 ;
     RECT  113.404 17.328 114.577 17.4 ;
     RECT  113.699 29.328 114.613 29.352 ;
     RECT  114.577 17.328 114.617 17.448 ;
     RECT  114.545 19.008 114.617 19.128 ;
     RECT  113.651 21.408 114.689 27.384 ;
     RECT  114.613 29.04 114.833 29.352 ;
     RECT  114.833 29.328 115.189 29.352 ;
     RECT  115.189 29.328 115.331 30.072 ;
     RECT  113.404 20.304 115.333 20.376 ;
     RECT  114.689 21.408 115.333 27.144 ;
     RECT  115.333 20.304 115.657 27.144 ;
     RECT  115.657 20.304 115.669 27.384 ;
     RECT  114.037 1.728 115.808 4.248 ;
     RECT  113.404 5.472 115.808 5.496 ;
     RECT  113.404 7.104 115.808 7.176 ;
     RECT  113.404 8.784 115.808 8.808 ;
     RECT  113.404 11.664 115.808 11.688 ;
     RECT  115.081 12.816 115.808 12.84 ;
     RECT  113.404 14.496 115.808 14.52 ;
     RECT  113.404 16.272 115.808 16.344 ;
     RECT  114.617 17.376 115.808 17.448 ;
     RECT  114.617 19.008 115.808 19.08 ;
     RECT  115.669 20.304 115.808 27.48 ;
     RECT  115.808 1.728 115.909 28.092 ;
     RECT  115.909 1.728 116.053 28.248 ;
     RECT  116.053 1.728 116.104 28.344 ;
     RECT  116.053 0.72 116.125 0.744 ;
     RECT  116.125 0.096 116.243 0.744 ;
     RECT  115.331 29.328 116.341 30.024 ;
     RECT  116.104 20.304 116.629 28.344 ;
     RECT  116.341 29.328 116.629 30.072 ;
     RECT  116.629 20.304 116.813 30.072 ;
     RECT  116.813 20.304 116.849 27.864 ;
     RECT  116.849 20.304 116.867 27.384 ;
     RECT  116.867 20.304 117.065 27.192 ;
     RECT  116.813 28.944 117.155 30.072 ;
     RECT  116.104 16.272 117.173 16.344 ;
     RECT  117.155 28.944 117.251 30.024 ;
     RECT  117.251 29.04 118.213 30.024 ;
     RECT  118.213 28.512 118.261 30.024 ;
     RECT  116.104 1.728 118.508 4.248 ;
     RECT  116.104 5.472 118.508 5.496 ;
     RECT  116.104 7.104 118.508 7.176 ;
     RECT  116.104 8.784 118.508 8.808 ;
     RECT  116.104 11.664 118.508 11.688 ;
     RECT  116.104 12.816 118.508 12.84 ;
     RECT  116.104 14.496 118.508 14.52 ;
     RECT  117.173 16.272 118.508 16.296 ;
     RECT  116.104 17.376 118.508 17.448 ;
     RECT  116.104 19.008 118.508 19.08 ;
     RECT  117.065 20.304 118.508 20.328 ;
     RECT  117.065 21.36 118.508 27.192 ;
     RECT  118.261 28.512 118.508 30.072 ;
     RECT  118.261 0.144 118.547 0.168 ;
     RECT  118.508 1.728 118.789 30.072 ;
     RECT  118.789 1.536 118.804 30.072 ;
     RECT  118.804 1.536 118.931 4.248 ;
     RECT  118.804 21.504 119.027 30.072 ;
     RECT  119.027 21.504 119.075 28.344 ;
     RECT  118.931 1.728 119.729 4.248 ;
     RECT  119.075 21.504 119.891 27.432 ;
     RECT  118.804 19.008 119.977 19.08 ;
     RECT  118.804 20.304 119.977 20.328 ;
     RECT  119.891 21.504 119.977 27.144 ;
     RECT  119.027 29.328 120.085 30.072 ;
     RECT  118.804 5.472 120.161 7.176 ;
     RECT  119.977 18.864 120.161 19.08 ;
     RECT  120.085 29.04 120.229 30.072 ;
     RECT  120.229 28.464 120.313 30.072 ;
     RECT  119.977 20.304 120.853 27.144 ;
     RECT  120.997 0.144 121.045 0.168 ;
     RECT  119.729 1.728 121.045 3.144 ;
     RECT  119.729 4.224 121.045 4.248 ;
     RECT  120.853 20.304 121.093 27.432 ;
     RECT  121.045 1.728 121.208 4.248 ;
     RECT  120.161 5.472 121.208 5.496 ;
     RECT  120.161 7.104 121.208 7.176 ;
     RECT  118.804 8.784 121.208 8.808 ;
     RECT  118.804 11.664 121.208 11.688 ;
     RECT  118.804 12.816 121.208 12.84 ;
     RECT  118.804 14.496 121.208 14.52 ;
     RECT  118.804 16.272 121.208 16.296 ;
     RECT  118.804 17.376 121.208 17.448 ;
     RECT  120.161 19.008 121.208 19.08 ;
     RECT  121.093 20.304 121.208 28.248 ;
     RECT  121.045 0.144 121.283 0.264 ;
     RECT  121.208 1.728 121.283 28.248 ;
     RECT  121.283 1.728 121.312 28.092 ;
     RECT  121.283 0.24 121.427 0.264 ;
     RECT  121.312 1.728 121.504 27.822 ;
     RECT  120.313 29.328 121.667 30.072 ;
     RECT  121.667 29.328 121.811 29.976 ;
     RECT  121.504 17.328 122.533 17.4 ;
     RECT  121.504 20.304 122.533 27.384 ;
     RECT  122.533 17.328 122.573 17.448 ;
     RECT  121.504 19.008 122.573 19.128 ;
     RECT  121.504 1.728 122.821 3.144 ;
     RECT  122.533 20.304 122.941 28.296 ;
     RECT  122.941 28.224 123.109 28.296 ;
     RECT  121.811 29.328 123.109 29.352 ;
     RECT  123.037 0.528 123.155 0.552 ;
     RECT  123.109 28.224 123.401 29.352 ;
     RECT  122.821 1.728 123.908 3.192 ;
     RECT  121.504 4.224 123.908 4.248 ;
     RECT  121.504 5.472 123.908 5.496 ;
     RECT  121.504 7.104 123.908 7.176 ;
     RECT  121.504 8.784 123.908 8.808 ;
     RECT  121.504 11.664 123.908 11.688 ;
     RECT  121.504 12.816 123.908 12.84 ;
     RECT  121.504 14.496 123.908 14.52 ;
     RECT  121.504 16.272 123.908 16.296 ;
     RECT  122.573 17.376 123.908 17.448 ;
     RECT  122.573 19.008 123.908 19.08 ;
     RECT  122.941 20.304 123.908 27.144 ;
     RECT  123.401 28.224 123.908 28.344 ;
     RECT  123.908 1.728 124.204 28.344 ;
     RECT  123.401 29.328 124.261 29.352 ;
     RECT  124.204 20.304 124.549 28.344 ;
     RECT  124.261 29.328 124.549 30.072 ;
     RECT  124.549 20.304 124.636 30.072 ;
     RECT  124.636 20.304 124.835 30.024 ;
     RECT  124.835 20.304 125.309 29.352 ;
     RECT  125.309 20.304 125.356 27.96 ;
     RECT  125.309 29.328 125.989 29.352 ;
     RECT  125.989 29.328 126.133 29.928 ;
     RECT  124.204 12.816 126.205 12.84 ;
     RECT  124.204 1.728 126.608 3.144 ;
     RECT  124.204 4.224 126.608 4.248 ;
     RECT  124.204 5.472 126.608 5.496 ;
     RECT  124.204 7.104 126.608 7.176 ;
     RECT  124.204 8.784 126.608 8.808 ;
     RECT  124.204 11.664 126.608 11.688 ;
     RECT  126.205 12.768 126.608 12.84 ;
     RECT  124.204 14.496 126.608 14.52 ;
     RECT  124.204 16.272 126.608 16.296 ;
     RECT  124.204 17.424 126.608 17.448 ;
     RECT  124.204 19.008 126.608 19.08 ;
     RECT  125.356 20.304 126.608 27.384 ;
     RECT  126.608 1.728 126.853 28.092 ;
     RECT  126.133 29.328 126.853 30.024 ;
     RECT  126.709 0.288 126.901 0.312 ;
     RECT  126.853 1.728 126.901 30.024 ;
     RECT  126.901 0.192 126.904 30.072 ;
     RECT  126.904 0.192 127.043 3.192 ;
     RECT  126.904 20.304 127.043 30.072 ;
     RECT  127.043 1.152 127.091 3.192 ;
     RECT  127.043 20.304 127.091 29.88 ;
     RECT  127.091 20.304 127.187 29.352 ;
     RECT  127.187 29.04 127.283 29.352 ;
     RECT  127.091 1.728 127.657 3.192 ;
     RECT  126.904 4.224 127.865 5.496 ;
     RECT  127.283 29.328 128.053 29.352 ;
     RECT  127.187 20.304 128.117 27.432 ;
     RECT  128.053 29.328 128.437 30.072 ;
     RECT  127.657 1.728 128.833 3.144 ;
     RECT  128.833 1.728 128.905 3.192 ;
     RECT  127.865 4.224 128.905 4.248 ;
     RECT  128.905 1.728 129.308 4.248 ;
     RECT  127.865 5.472 129.308 5.496 ;
     RECT  126.904 7.104 129.308 7.176 ;
     RECT  126.904 8.784 129.308 8.808 ;
     RECT  126.904 11.664 129.308 11.688 ;
     RECT  126.904 12.768 129.308 12.84 ;
     RECT  126.904 14.496 129.308 14.52 ;
     RECT  126.904 16.272 129.308 16.296 ;
     RECT  126.904 17.424 129.308 17.448 ;
     RECT  126.904 19.008 129.308 19.08 ;
     RECT  128.117 20.304 129.308 27.384 ;
     RECT  128.437 28.512 129.308 30.072 ;
     RECT  129.308 1.728 129.412 30.072 ;
     RECT  129.412 1.728 129.604 27.96 ;
     RECT  129.412 28.944 129.827 30.072 ;
     RECT  129.604 1.728 129.881 4.248 ;
     RECT  129.604 20.304 129.881 27.96 ;
     RECT  129.827 29.04 129.971 30.072 ;
     RECT  129.604 7.104 130.835 7.176 ;
     RECT  129.881 20.304 130.844 27.48 ;
     RECT  129.881 1.776 131.173 4.248 ;
     RECT  131.101 0.576 131.459 0.6 ;
     RECT  131.605 0.096 131.747 0.12 ;
     RECT  131.173 1.728 131.749 4.248 ;
     RECT  129.971 29.328 131.845 30.072 ;
     RECT  131.749 1.104 132.008 4.248 ;
     RECT  129.604 5.472 132.008 5.496 ;
     RECT  130.835 7.104 132.008 7.128 ;
     RECT  129.604 8.784 132.008 8.808 ;
     RECT  129.604 11.664 132.008 11.688 ;
     RECT  129.604 12.768 132.008 12.84 ;
     RECT  129.604 14.496 132.008 14.52 ;
     RECT  129.604 16.272 132.008 16.296 ;
     RECT  129.604 17.424 132.008 17.448 ;
     RECT  129.604 19.008 132.008 19.08 ;
     RECT  130.844 20.304 132.008 27.96 ;
     RECT  131.845 29.04 132.008 30.072 ;
     RECT  132.008 1.104 132.112 30.072 ;
     RECT  132.112 29.04 132.227 30.072 ;
     RECT  132.112 1.104 132.304 27.822 ;
     RECT  132.304 1.104 132.323 4.248 ;
     RECT  132.227 29.328 132.419 30.072 ;
     RECT  132.419 29.328 133.477 29.976 ;
     RECT  132.304 20.304 133.765 27.288 ;
     RECT  133.477 29.328 134.3 30.072 ;
     RECT  133.765 20.304 134.629 27.96 ;
     RECT  134.3 29.088 134.629 30.072 ;
     RECT  132.323 1.728 134.708 4.248 ;
     RECT  132.304 5.472 134.708 5.496 ;
     RECT  134.305 6.528 134.708 6.552 ;
     RECT  132.304 8.784 134.708 8.808 ;
     RECT  132.304 11.664 134.708 11.688 ;
     RECT  132.304 12.768 134.708 12.84 ;
     RECT  132.304 16.272 134.708 16.296 ;
     RECT  132.304 17.424 134.708 17.448 ;
     RECT  132.304 19.008 134.708 19.08 ;
     RECT  134.629 20.304 134.708 30.072 ;
     RECT  134.708 1.728 135.004 30.072 ;
     RECT  135.004 28.176 135.251 30.072 ;
     RECT  135.004 1.728 135.641 4.248 ;
     RECT  135.641 1.728 136.145 3.192 ;
     RECT  135.004 20.304 136.213 27.144 ;
     RECT  135.251 28.944 136.453 30.072 ;
     RECT  136.453 28.512 136.787 30.072 ;
     RECT  136.213 20.304 136.933 27.384 ;
     RECT  136.787 28.512 136.933 30.024 ;
     RECT  136.145 1.728 137.173 3.144 ;
     RECT  135.641 4.224 137.173 4.248 ;
     RECT  137.173 1.728 137.408 4.248 ;
     RECT  135.004 5.472 137.408 5.496 ;
     RECT  135.004 8.784 137.408 8.808 ;
     RECT  135.004 11.664 137.408 11.688 ;
     RECT  135.004 12.768 137.408 12.84 ;
     RECT  135.004 16.272 137.408 16.296 ;
     RECT  135.004 17.424 137.408 17.448 ;
     RECT  135.004 19.008 137.408 19.08 ;
     RECT  136.933 20.304 137.408 30.024 ;
     RECT  137.408 1.728 137.704 30.024 ;
     RECT  137.704 20.304 138.083 30.024 ;
     RECT  138.083 29.04 138.085 30.024 ;
     RECT  138.085 29.04 138.179 30.072 ;
     RECT  138.083 20.304 138.323 27.384 ;
     RECT  137.704 17.328 138.557 17.448 ;
     RECT  137.704 19.008 138.557 19.128 ;
     RECT  138.179 29.328 139.201 30.072 ;
     RECT  139.201 28.848 139.34 30.072 ;
     RECT  139.957 0.144 140.099 0.168 ;
     RECT  137.704 1.728 140.108 3.144 ;
     RECT  137.704 4.224 140.108 4.248 ;
     RECT  137.704 5.472 140.108 5.496 ;
     RECT  137.704 8.784 140.108 8.808 ;
     RECT  137.704 11.664 140.108 11.688 ;
     RECT  137.704 12.768 140.108 12.792 ;
     RECT  137.704 16.272 140.108 16.296 ;
     RECT  138.557 17.424 140.108 17.448 ;
     RECT  138.557 19.008 140.108 19.08 ;
     RECT  138.323 20.304 140.108 20.328 ;
     RECT  138.323 21.456 140.108 27.384 ;
     RECT  139.34 28.512 140.108 30.072 ;
     RECT  140.108 1.728 140.404 30.072 ;
     RECT  140.404 28.176 140.569 30.072 ;
     RECT  140.569 28.176 140.573 30.168 ;
     RECT  140.404 21.456 140.905 27.192 ;
     RECT  140.404 1.728 141.257 3.096 ;
     RECT  140.905 21.456 141.299 23.928 ;
     RECT  140.573 28.512 141.653 30.168 ;
     RECT  140.905 24.912 141.685 27.192 ;
     RECT  141.299 21.456 141.973 22.584 ;
     RECT  141.299 23.904 142.268 23.928 ;
     RECT  141.685 24.912 142.268 27.96 ;
     RECT  141.257 1.728 142.693 2.904 ;
     RECT  140.404 4.224 142.693 4.248 ;
     RECT  141.973 21.36 142.693 22.584 ;
     RECT  142.268 23.904 142.729 27.96 ;
     RECT  142.693 1.728 142.808 4.248 ;
     RECT  140.404 5.472 142.808 5.496 ;
     RECT  140.404 8.784 142.808 8.808 ;
     RECT  140.404 12.768 142.808 12.792 ;
     RECT  140.404 16.272 142.808 16.296 ;
     RECT  140.404 17.424 142.808 17.448 ;
     RECT  140.404 19.008 142.808 19.08 ;
     RECT  140.404 20.304 142.808 20.328 ;
     RECT  142.693 21.36 142.808 22.776 ;
     RECT  142.729 23.904 142.808 28.248 ;
     RECT  142.693 0.144 142.979 0.168 ;
     RECT  142.808 1.728 143.104 28.248 ;
     RECT  143.104 24.624 143.269 28.248 ;
     RECT  141.653 29.328 143.269 30.168 ;
     RECT  143.269 24.624 143.273 30.168 ;
     RECT  143.104 14.832 143.345 14.856 ;
     RECT  143.273 26.016 143.381 30.168 ;
     RECT  143.104 21.504 143.651 23.256 ;
     RECT  143.104 12.768 143.813 12.792 ;
     RECT  143.651 21.504 143.849 22.776 ;
     RECT  143.381 26.064 143.953 30.168 ;
     RECT  143.104 17.424 144.101 17.448 ;
     RECT  143.849 21.504 144.425 21.816 ;
     RECT  144.425 21.792 144.533 21.816 ;
     RECT  144.709 0.528 145.427 0.552 ;
     RECT  143.104 1.728 145.508 3.144 ;
     RECT  143.104 4.224 145.508 4.248 ;
     RECT  143.104 5.472 145.508 5.496 ;
     RECT  143.104 8.784 145.508 8.808 ;
     RECT  143.104 16.272 145.508 16.296 ;
     RECT  143.104 19.008 145.508 19.08 ;
     RECT  143.104 20.304 145.508 20.328 ;
     RECT  143.273 24.624 145.508 24.984 ;
     RECT  143.953 26.064 145.508 30.216 ;
     RECT  145.508 1.728 145.804 30.216 ;
     RECT  145.804 26.064 145.901 30.216 ;
     RECT  145.804 24.96 146.003 24.984 ;
     RECT  145.901 27.12 146.147 30.216 ;
     RECT  146.147 27.6 146.297 30.216 ;
     RECT  145.804 1.728 146.435 3.192 ;
     RECT  146.297 27.6 147.161 27.624 ;
     RECT  146.297 29.328 147.395 30.216 ;
     RECT  146.435 1.728 148.208 3.096 ;
     RECT  145.804 4.224 148.208 4.248 ;
     RECT  145.804 5.472 148.208 5.496 ;
     RECT  145.804 8.784 148.208 8.808 ;
     RECT  145.804 16.272 148.208 16.296 ;
     RECT  145.804 19.056 148.208 19.08 ;
     RECT  145.804 20.304 148.208 20.328 ;
     RECT  145.901 26.064 148.208 26.136 ;
     RECT  148.208 1.728 148.312 28.092 ;
     RECT  147.395 30.192 148.357 30.216 ;
     RECT  148.357 30.096 148.403 30.216 ;
     RECT  148.403 30.096 148.499 30.12 ;
     RECT  148.312 1.728 148.504 27.822 ;
     RECT  148.504 26.064 148.643 26.088 ;
     RECT  148.504 1.728 148.817 3.096 ;
     RECT  148.817 1.728 149.813 2.904 ;
     RECT  149.813 1.728 149.897 3.096 ;
     RECT  149.897 1.728 150.908 2.856 ;
     RECT  148.504 4.224 150.908 4.248 ;
     RECT  148.504 5.472 150.908 5.496 ;
     RECT  148.504 8.784 150.908 8.808 ;
     RECT  148.504 16.272 150.908 16.296 ;
     RECT  148.504 19.056 150.908 19.08 ;
     RECT  148.504 20.304 150.908 20.328 ;
     RECT  150.908 1.728 151.012 28.092 ;
     RECT  151.012 1.728 151.204 27.822 ;
     RECT  151.204 19.056 151.949 19.08 ;
     RECT  151.204 1.728 153.301 2.904 ;
     RECT  151.204 4.224 153.301 4.248 ;
     RECT  153.301 1.728 153.608 4.248 ;
     RECT  151.204 5.472 153.608 5.496 ;
     RECT  151.204 8.784 153.608 8.808 ;
     RECT  151.204 16.272 153.608 16.296 ;
     RECT  151.204 20.304 153.608 20.328 ;
     RECT  153.608 1.728 153.712 28.092 ;
     RECT  153.712 1.728 153.904 27.822 ;
     RECT  153.904 1.728 154.885 2.568 ;
     RECT  154.885 1.728 156.308 2.904 ;
     RECT  153.904 4.224 156.308 4.248 ;
     RECT  153.904 5.472 156.308 5.496 ;
     RECT  153.904 8.784 156.308 8.808 ;
     RECT  153.904 16.272 156.308 16.296 ;
     RECT  153.904 20.304 156.308 20.328 ;
     RECT  156.308 1.728 156.412 28.092 ;
     RECT  156.412 1.728 156.604 27.822 ;
     RECT  156.613 0.144 156.755 0.168 ;
     RECT  156.604 1.728 156.809 4.248 ;
     RECT  156.809 1.728 156.845 3 ;
     RECT  156.845 1.728 157.385 2.952 ;
     RECT  157.385 2.88 158.173 2.952 ;
     RECT  157.385 1.728 158.629 1.8 ;
     RECT  158.173 2.88 158.629 3.096 ;
     RECT  158.629 1.728 158.897 3.096 ;
     RECT  158.897 1.776 159.008 3.096 ;
     RECT  156.809 4.224 159.008 4.248 ;
     RECT  156.604 5.472 159.008 5.496 ;
     RECT  156.604 8.784 159.008 8.808 ;
     RECT  156.604 16.272 159.008 16.296 ;
     RECT  156.604 20.304 159.008 20.328 ;
     RECT  159.008 1.776 159.112 28.092 ;
     RECT  159.112 1.776 159.304 27.822 ;
     RECT  159.304 1.776 159.437 4.248 ;
     RECT  159.437 1.776 159.473 1.896 ;
     RECT  158.821 0.144 159.491 0.168 ;
     RECT  159.473 1.776 159.617 1.8 ;
     RECT  159.437 2.88 160.589 4.248 ;
     RECT  160.213 1.728 160.901 1.752 ;
     RECT  160.901 1.728 161.197 1.8 ;
     RECT  161.197 1.728 161.485 1.848 ;
     RECT  160.589 2.88 161.485 2.904 ;
     RECT  161.485 1.728 161.557 2.904 ;
     RECT  161.557 0.144 161.699 0.168 ;
     RECT  161.557 1.728 161.708 3.048 ;
     RECT  160.589 4.224 161.708 4.248 ;
     RECT  159.304 5.472 161.708 5.496 ;
     RECT  159.304 8.784 161.708 8.808 ;
     RECT  159.304 16.272 161.708 16.296 ;
     RECT  159.304 20.304 161.708 20.328 ;
     RECT  161.708 1.728 161.812 28.092 ;
     RECT  161.812 1.728 162.004 27.822 ;
     RECT  162.004 4.224 162.569 4.248 ;
     RECT  162.004 8.784 162.677 8.808 ;
     RECT  162.004 1.728 162.929 3.096 ;
     RECT  162.929 1.728 164.153 1.8 ;
     RECT  164.153 1.776 164.185 1.8 ;
     RECT  162.929 2.88 164.185 3.096 ;
     RECT  164.185 1.776 164.408 3.096 ;
     RECT  162.004 5.472 164.408 5.496 ;
     RECT  162.004 16.272 164.408 16.296 ;
     RECT  162.004 20.304 164.408 20.328 ;
     RECT  164.408 1.776 164.512 28.092 ;
     RECT  164.293 0.144 164.579 0.168 ;
     RECT  164.512 1.776 164.704 27.822 ;
     RECT  164.704 1.776 165.017 3.24 ;
     RECT  165.017 2.88 165.269 3.24 ;
     RECT  165.017 1.776 165.397 1.8 ;
     RECT  165.397 1.728 166.097 1.8 ;
     RECT  166.097 1.728 167.108 1.752 ;
     RECT  165.269 2.88 167.108 3.096 ;
     RECT  164.704 5.472 167.108 5.496 ;
     RECT  164.704 16.272 167.108 16.296 ;
     RECT  164.704 20.304 167.108 20.328 ;
     RECT  167.108 1.728 167.212 28.092 ;
     RECT  167.212 1.728 167.404 27.822 ;
     RECT  167.413 0.144 167.555 0.168 ;
     RECT  167.404 1.728 168.545 3.384 ;
     RECT  168.545 2.784 168.709 3.384 ;
     RECT  167.404 5.472 168.761 5.496 ;
     RECT  168.709 2.784 168.997 3.432 ;
     RECT  168.545 1.728 169.301 1.8 ;
     RECT  169.301 1.776 169.532 1.8 ;
     RECT  168.997 2.784 169.532 3.48 ;
     RECT  169.429 0.096 169.621 0.12 ;
     RECT  169.532 1.776 169.621 3.48 ;
     RECT  169.225 4.752 169.621 4.776 ;
     RECT  169.621 1.776 169.808 4.776 ;
     RECT  169.808 1.776 169.912 28.092 ;
     RECT  169.912 1.776 170.104 27.822 ;
     RECT  169.621 0.096 170.237 0.168 ;
     RECT  170.104 1.776 170.269 3.432 ;
     RECT  170.269 1.2 170.339 3.432 ;
     RECT  170.237 0.144 170.345 0.168 ;
     RECT  170.339 2.832 170.785 3.432 ;
     RECT  170.339 1.2 171.203 1.704 ;
     RECT  171.203 1.632 171.347 1.704 ;
     RECT  170.785 2.832 171.491 2.856 ;
     RECT  171.241 0.528 171.557 0.552 ;
     RECT  171.557 0.096 171.641 0.552 ;
     RECT  171.529 3.984 171.779 4.008 ;
     RECT  171.347 1.632 171.923 1.656 ;
     RECT  171.641 0.528 172.067 0.552 ;
    LAYER M5 ;
     RECT  90.912 0.016 91.08 0.131 ;
     RECT  131.424 0.016 172.056 0.563 ;
     RECT  87.792 0.016 89.832 0.611 ;
     RECT  131.424 0.563 171.912 0.611 ;
     RECT  90.912 0.131 90.936 1.187 ;
     RECT  131.568 0.611 171.912 1.667 ;
     RECT  87.936 0.611 89.832 1.763 ;
     RECT  88.08 1.763 89.256 1.811 ;
     RECT  92.16 0.016 130.344 1.859 ;
     RECT  131.568 1.667 171.768 1.859 ;
     RECT  96.192 1.859 130.344 2.003 ;
     RECT  94.2 1.859 94.776 2.099 ;
     RECT  152.592 1.859 171.768 2.099 ;
     RECT  92.16 1.859 92.904 2.137 ;
     RECT  2.4 2.137 2.52 2.151 ;
     RECT  5.1 2.137 5.22 2.151 ;
     RECT  7.8 2.137 7.92 2.151 ;
     RECT  10.5 2.137 10.62 2.151 ;
     RECT  13.2 2.137 13.32 2.151 ;
     RECT  15.9 2.137 16.02 2.151 ;
     RECT  18.6 2.137 18.72 2.151 ;
     RECT  21.3 2.137 21.42 2.151 ;
     RECT  24 2.137 24.12 2.151 ;
     RECT  26.7 2.137 26.82 2.151 ;
     RECT  29.4 2.137 29.52 2.151 ;
     RECT  32.1 2.137 32.22 2.151 ;
     RECT  34.8 2.137 34.92 2.151 ;
     RECT  37.5 2.137 37.62 2.151 ;
     RECT  40.2 2.137 40.32 2.151 ;
     RECT  42.9 2.137 43.02 2.151 ;
     RECT  45.6 2.137 45.72 2.151 ;
     RECT  48.3 2.137 48.42 2.151 ;
     RECT  51 2.137 51.12 2.151 ;
     RECT  53.7 2.137 53.82 2.151 ;
     RECT  56.4 2.137 56.52 2.151 ;
     RECT  59.1 2.137 59.22 2.151 ;
     RECT  61.8 2.137 61.92 2.151 ;
     RECT  64.5 2.137 64.62 2.151 ;
     RECT  67.2 2.137 67.32 2.151 ;
     RECT  69.9 2.137 70.02 2.151 ;
     RECT  72.6 2.137 72.72 2.151 ;
     RECT  75.3 2.137 75.42 2.151 ;
     RECT  78 2.137 78.12 2.151 ;
     RECT  80.7 2.137 80.82 2.151 ;
     RECT  83.4 2.137 83.52 2.151 ;
     RECT  86.1 2.137 86.22 2.151 ;
     RECT  106.992 2.003 130.344 2.243 ;
     RECT  131.568 1.859 151.608 2.245 ;
     RECT  88.656 1.811 89.256 2.291 ;
     RECT  91.5 2.137 92.904 2.291 ;
     RECT  96.192 2.003 106.008 2.291 ;
     RECT  131.328 2.245 151.608 2.291 ;
     RECT  107.52 2.243 130.344 2.485 ;
     RECT  131.328 2.291 149.88 2.485 ;
     RECT  107.52 2.485 149.88 2.723 ;
     RECT  110.256 2.723 149.88 2.867 ;
     RECT  154.896 2.099 171.768 2.867 ;
     RECT  94.2 2.099 94.632 2.915 ;
     RECT  96.192 2.291 105.432 2.915 ;
     RECT  107.52 2.723 109.176 2.915 ;
     RECT  110.256 2.867 127.608 2.915 ;
     RECT  128.592 2.867 149.88 2.915 ;
     RECT  150.9 2.291 151.608 2.915 ;
     RECT  152.592 2.099 153.912 2.915 ;
     RECT  154.896 2.867 170.76 2.915 ;
     RECT  112.032 2.915 122.856 2.963 ;
     RECT  123.9 2.915 125.304 2.963 ;
     RECT  134.16 2.915 138.216 2.963 ;
     RECT  157.776 2.915 160.536 2.963 ;
     RECT  107.52 2.915 108.456 3.011 ;
     RECT  110.256 2.915 110.808 3.011 ;
     RECT  112.032 2.963 118.92 3.011 ;
     RECT  120.384 2.963 121.512 3.011 ;
     RECT  128.592 2.915 133.032 3.011 ;
     RECT  139.968 2.915 141.24 3.011 ;
     RECT  99.408 2.915 100.248 3.059 ;
     RECT  112.032 3.011 116.232 3.059 ;
     RECT  117.36 3.011 118.92 3.059 ;
     RECT  121.008 3.011 121.512 3.059 ;
     RECT  161.568 2.915 165.72 3.059 ;
     RECT  99.6 3.059 100.248 3.107 ;
     RECT  104.544 2.915 105.432 3.107 ;
     RECT  110.4 3.011 110.808 3.107 ;
     RECT  112.032 3.059 112.056 3.107 ;
     RECT  113.1 3.059 116.112 3.107 ;
     RECT  117.36 3.059 118.812 3.107 ;
     RECT  123.9 2.963 124.584 3.107 ;
     RECT  128.592 3.011 132.888 3.107 ;
     RECT  134.16 2.963 136.056 3.107 ;
     RECT  137.184 2.963 138.216 3.107 ;
     RECT  140.1 3.011 141.24 3.107 ;
     RECT  142.704 2.915 144.408 3.107 ;
     RECT  147.408 2.915 148.728 3.107 ;
     RECT  149.856 2.915 149.88 3.107 ;
     RECT  156.3 2.915 156.744 3.107 ;
     RECT  158.208 2.963 160.536 3.107 ;
     RECT  161.7 3.059 165.72 3.107 ;
     RECT  166.704 2.915 167.544 3.107 ;
     RECT  96.336 2.915 97.212 3.203 ;
     RECT  101.376 2.915 103.128 3.203 ;
     RECT  104.832 3.107 105.432 3.203 ;
     RECT  122.832 2.963 122.856 3.203 ;
     RECT  126.6 2.915 127.608 3.203 ;
     RECT  134.304 3.107 135.012 3.203 ;
     RECT  145.5 2.915 146.424 3.203 ;
     RECT  129.3 3.107 132.888 3.299 ;
     RECT  96.624 3.203 97.212 3.347 ;
     RECT  104.832 3.203 105.312 3.347 ;
     RECT  121.056 3.059 121.512 3.347 ;
     RECT  137.184 3.107 137.712 3.347 ;
     RECT  142.704 3.107 143.112 3.347 ;
     RECT  153.312 2.915 153.912 3.347 ;
     RECT  107.52 3.011 108.012 3.395 ;
     RECT  159 3.107 160.536 3.395 ;
     RECT  101.376 3.203 102.612 3.443 ;
     RECT  168.72 2.915 170.76 3.443 ;
     RECT  169.008 3.443 170.112 3.491 ;
     RECT  91.5 2.291 91.812 3.685 ;
     RECT  171.744 2.867 171.768 4.019 ;
     RECT  169.632 3.491 170.112 4.115 ;
     RECT  129.3 3.299 132.312 14.531 ;
     RECT  24 2.151 24.312 15.685 ;
     RECT  23.904 15.685 24.312 15.827 ;
     RECT  75.3 2.151 75.612 20.101 ;
     RECT  105 3.347 105.312 20.965 ;
     RECT  105 20.965 105.432 21.109 ;
     RECT  0.192 14.581 0.216 21.203 ;
     RECT  104.16 21.109 105.432 21.203 ;
     RECT  129.3 14.531 130.488 21.205 ;
     RECT  137.4 3.347 137.712 21.205 ;
     RECT  121.2 3.347 121.512 21.301 ;
     RECT  75.168 20.101 75.612 21.443 ;
     RECT  91.008 3.685 91.812 21.443 ;
     RECT  104.16 21.203 105.312 21.443 ;
     RECT  128.832 21.205 130.488 21.491 ;
     RECT  129.3 21.491 130.488 21.493 ;
     RECT  137.4 21.205 138.312 21.539 ;
     RECT  110.4 3.107 110.712 21.541 ;
     RECT  140.1 3.107 140.412 21.589 ;
     RECT  96.9 3.347 97.212 21.637 ;
     RECT  99.6 3.107 99.912 21.637 ;
     RECT  80.7 2.151 81.012 22.165 ;
     RECT  86.1 2.151 86.412 22.165 ;
     RECT  142.8 3.347 143.112 22.213 ;
     RECT  83.4 2.151 83.712 22.597 ;
     RECT  88.8 2.291 89.112 22.693 ;
     RECT  142.8 22.213 143.64 22.741 ;
     RECT  88.8 22.693 89.832 22.789 ;
     RECT  94.2 2.915 94.512 22.789 ;
     RECT  115.8 3.107 116.112 22.933 ;
     RECT  118.5 3.107 118.812 22.933 ;
     RECT  126.6 3.203 126.912 22.933 ;
     RECT  78 2.151 78.312 23.077 ;
     RECT  74.112 19.909 74.136 23.123 ;
     RECT  86.1 22.165 86.568 23.221 ;
     RECT  142.704 22.741 143.64 23.267 ;
     RECT  96.9 21.637 97.8 23.269 ;
     RECT  121.2 21.301 121.608 23.269 ;
     RECT  72.6 2.151 72.912 23.317 ;
     RECT  77.904 23.077 78.312 23.317 ;
     RECT  68.832 22.021 68.856 23.365 ;
     RECT  69.9 2.151 70.212 23.365 ;
     RECT  72.288 23.317 72.912 23.365 ;
     RECT  77.712 23.317 78.312 23.365 ;
     RECT  94.2 22.789 95.208 23.365 ;
     RECT  104.256 21.443 105.312 23.365 ;
     RECT  139.68 21.589 140.412 23.365 ;
     RECT  75.3 21.443 75.612 23.413 ;
     RECT  102.3 3.443 102.612 23.413 ;
     RECT  129.3 21.493 131.016 23.413 ;
     RECT  132 14.531 132.312 23.413 ;
     RECT  137.4 21.539 137.712 23.413 ;
     RECT  139.68 23.365 141.288 23.413 ;
     RECT  91.5 21.443 91.812 23.605 ;
     RECT  77.712 23.365 79.128 23.653 ;
     RECT  75.3 23.413 75.816 23.701 ;
     RECT  113.1 3.107 113.412 23.749 ;
     RECT  114.528 23.557 114.552 23.749 ;
     RECT  75.12 23.701 75.816 23.797 ;
     RECT  134.7 3.203 135.012 23.797 ;
     RECT  75.12 23.797 76.104 23.845 ;
     RECT  139.056 23.413 141.288 23.845 ;
     RECT  67.2 2.151 67.512 23.893 ;
     RECT  86.1 23.221 87.384 23.893 ;
     RECT  88.368 22.789 90.408 23.893 ;
     RECT  133.68 23.413 133.704 23.893 ;
     RECT  134.7 23.797 135.192 23.893 ;
     RECT  91.5 23.605 91.992 23.941 ;
     RECT  94.08 23.365 95.208 23.941 ;
     RECT  118.32 22.933 118.812 23.941 ;
     RECT  119.856 23.221 119.88 23.941 ;
     RECT  123.9 3.107 124.212 23.941 ;
     RECT  128.784 23.413 132.312 23.941 ;
     RECT  109.776 21.541 110.712 23.989 ;
     RECT  83.4 22.597 83.928 24.085 ;
     RECT  118.32 23.941 119.88 24.085 ;
     RECT  77.712 23.653 79.656 24.131 ;
     RECT  128.16 23.941 132.312 24.133 ;
     RECT  83.4 24.085 84.6 24.181 ;
     RECT  121.2 23.269 121.704 24.277 ;
     RECT  122.88 23.269 122.904 24.277 ;
     RECT  71.664 23.365 73.752 24.325 ;
     RECT  75.12 23.845 76.2 24.325 ;
     RECT  83.232 24.181 84.6 24.325 ;
     RECT  86.1 23.893 90.408 24.325 ;
     RECT  133.68 23.893 135.192 24.325 ;
     RECT  107.7 3.395 108.012 24.373 ;
     RECT  109.584 23.989 110.712 24.373 ;
     RECT  83.232 24.325 90.408 24.421 ;
     RECT  91.5 23.941 92.184 24.421 ;
     RECT  94.08 23.941 95.736 24.421 ;
     RECT  96.9 23.269 98.568 24.421 ;
     RECT  115.8 22.933 116.856 24.421 ;
     RECT  117.936 24.085 119.88 24.421 ;
     RECT  94.08 24.421 98.568 24.469 ;
     RECT  99.6 21.637 100.2 24.469 ;
     RECT  128.16 24.133 132.456 24.469 ;
     RECT  133.632 24.325 135.816 24.469 ;
     RECT  137.04 23.413 137.712 24.469 ;
     RECT  71.664 24.325 76.2 24.517 ;
     RECT  77.712 24.131 79.56 24.517 ;
     RECT  113.1 23.749 114.552 24.517 ;
     RECT  115.8 24.421 120.216 24.517 ;
     RECT  126.096 22.933 126.912 24.517 ;
     RECT  128.16 24.469 135.816 24.517 ;
     RECT  136.944 24.469 137.712 24.517 ;
     RECT  142.704 23.267 143.112 24.517 ;
     RECT  80.7 22.165 81.624 24.565 ;
     RECT  101.52 23.413 102.612 24.565 ;
     RECT  121.2 24.277 122.904 24.565 ;
     RECT  123.9 23.941 124.536 24.565 ;
     RECT  64.5 2.151 64.812 24.661 ;
     RECT  42.9 2.151 43.212 24.901 ;
     RECT  145.5 3.203 145.812 24.949 ;
     RECT  68.832 23.365 70.212 24.997 ;
     RECT  68.784 24.997 70.212 25.045 ;
     RECT  71.616 24.517 79.56 25.045 ;
     RECT  83.232 24.421 92.184 25.091 ;
     RECT  93.504 24.469 100.2 25.093 ;
     RECT  101.376 24.565 102.612 25.093 ;
     RECT  104.208 23.365 105.312 25.093 ;
     RECT  107.7 24.373 110.712 25.093 ;
     RECT  126 24.517 126.912 25.093 ;
     RECT  128.16 24.517 137.712 25.093 ;
     RECT  138.768 23.845 141.288 25.093 ;
     RECT  142.32 24.517 143.112 25.093 ;
     RECT  83.184 25.091 92.184 25.141 ;
     RECT  93.504 25.093 102.612 25.141 ;
     RECT  104.16 25.093 105.312 25.141 ;
     RECT  126 25.093 137.712 25.141 ;
     RECT  138.768 25.093 143.112 25.141 ;
     RECT  64.176 24.661 64.812 25.187 ;
     RECT  112.8 24.517 120.216 25.333 ;
     RECT  121.2 24.565 124.536 25.333 ;
     RECT  42.048 24.901 43.212 25.477 ;
     RECT  67.2 23.893 67.8 25.669 ;
     RECT  68.784 25.045 79.56 25.669 ;
     RECT  80.7 24.565 81.672 25.669 ;
     RECT  83.184 25.141 105.312 25.669 ;
     RECT  107.7 25.093 110.856 25.669 ;
     RECT  112.8 25.333 124.536 25.669 ;
     RECT  126 25.141 143.112 25.669 ;
     RECT  66.864 25.669 67.8 25.717 ;
     RECT  68.784 25.669 105.312 25.717 ;
     RECT  107.7 25.669 110.904 25.717 ;
     RECT  112.8 25.669 143.112 25.717 ;
     RECT  107.7 25.717 111.336 25.765 ;
     RECT  112.656 25.717 143.112 25.765 ;
     RECT  42.048 25.477 43.32 26.005 ;
     RECT  106.56 25.621 106.584 26.005 ;
     RECT  107.568 25.765 143.112 26.005 ;
     RECT  148.2 3.107 148.512 26.053 ;
     RECT  148.2 26.053 148.632 26.101 ;
     RECT  66.864 25.717 105.312 26.149 ;
     RECT  64.5 25.187 64.812 26.581 ;
     RECT  106.56 26.005 143.112 26.629 ;
     RECT  144.144 26.341 144.168 26.629 ;
     RECT  64.32 26.581 64.812 26.725 ;
     RECT  106.56 26.629 144.168 26.725 ;
     RECT  63.888 26.725 64.812 26.867 ;
     RECT  145.5 24.949 145.992 27.109 ;
     RECT  106.56 26.725 144.312 27.589 ;
     RECT  145.5 27.109 146.136 27.589 ;
     RECT  63.168 27.349 63.192 27.829 ;
     RECT  61.8 2.151 62.112 27.925 ;
     RECT  63.168 27.829 63.48 27.925 ;
     RECT  64.5 26.867 64.812 27.925 ;
     RECT  66.864 26.149 105.432 27.925 ;
     RECT  2.4 2.151 2.712 28.089 ;
     RECT  5.1 2.151 5.412 28.089 ;
     RECT  7.8 2.151 8.112 28.089 ;
     RECT  10.5 2.151 10.812 28.089 ;
     RECT  13.2 2.151 13.512 28.089 ;
     RECT  15.9 2.151 16.212 28.089 ;
     RECT  18.6 2.151 18.912 28.089 ;
     RECT  21.3 2.151 21.612 28.089 ;
     RECT  24 15.827 24.312 28.089 ;
     RECT  26.7 2.151 27.012 28.089 ;
     RECT  29.4 2.151 29.712 28.089 ;
     RECT  32.1 2.151 32.412 28.089 ;
     RECT  34.8 2.151 35.112 28.089 ;
     RECT  37.5 2.151 37.812 28.089 ;
     RECT  40.2 2.151 40.512 28.089 ;
     RECT  45.6 2.151 45.912 28.089 ;
     RECT  48.3 2.151 48.612 28.089 ;
     RECT  51 2.151 51.312 28.089 ;
     RECT  53.7 2.151 54.012 28.089 ;
     RECT  56.4 2.151 56.712 28.089 ;
     RECT  59.1 2.151 59.412 28.089 ;
     RECT  150.9 2.915 151.212 28.089 ;
     RECT  153.6 3.347 153.912 28.089 ;
     RECT  156.3 3.107 156.612 28.089 ;
     RECT  159 3.395 159.312 28.089 ;
     RECT  161.7 3.107 162.012 28.089 ;
     RECT  164.4 3.107 164.712 28.089 ;
     RECT  167.1 3.107 167.412 28.089 ;
     RECT  169.8 4.115 170.112 28.089 ;
     RECT  2.4 28.089 2.52 28.103 ;
     RECT  5.1 28.089 5.22 28.103 ;
     RECT  7.8 28.089 7.92 28.103 ;
     RECT  10.5 28.089 10.62 28.103 ;
     RECT  13.2 28.089 13.32 28.103 ;
     RECT  15.9 28.089 16.02 28.103 ;
     RECT  18.6 28.089 18.72 28.103 ;
     RECT  21.3 28.089 21.42 28.103 ;
     RECT  24 28.089 24.12 28.103 ;
     RECT  26.7 28.089 26.82 28.103 ;
     RECT  29.4 28.089 29.52 28.103 ;
     RECT  32.1 28.089 32.22 28.103 ;
     RECT  34.8 28.089 34.92 28.103 ;
     RECT  37.5 28.089 37.62 28.103 ;
     RECT  40.2 28.089 40.32 28.103 ;
     RECT  42.048 26.005 43.464 28.103 ;
     RECT  45.6 28.089 45.72 28.103 ;
     RECT  48.3 28.089 48.42 28.103 ;
     RECT  51 28.089 51.12 28.103 ;
     RECT  53.7 28.089 53.82 28.103 ;
     RECT  56.4 28.089 56.52 28.103 ;
     RECT  59.1 28.089 59.22 28.103 ;
     RECT  61.8 27.925 105.432 28.103 ;
     RECT  106.56 27.589 146.136 28.103 ;
     RECT  147.216 26.101 148.632 28.103 ;
     RECT  150.9 28.089 151.02 28.103 ;
     RECT  153.6 28.089 153.72 28.103 ;
     RECT  156.3 28.089 156.42 28.103 ;
     RECT  159 28.089 159.12 28.103 ;
     RECT  161.7 28.089 161.82 28.103 ;
     RECT  164.4 28.089 164.52 28.103 ;
     RECT  167.1 28.089 167.22 28.103 ;
     RECT  169.8 28.089 169.92 28.103 ;
     RECT  65.136 28.103 105.432 28.501 ;
     RECT  65.136 28.501 105.48 29.029 ;
     RECT  106.56 28.103 144.888 29.029 ;
     RECT  147.216 28.103 147.24 29.317 ;
     RECT  65.136 29.029 144.888 29.363 ;
     RECT  65.136 29.363 105.624 30.085 ;
     RECT  148.608 28.103 148.632 30.085 ;
     RECT  42.048 28.103 42.216 30.224 ;
     RECT  43.296 28.103 43.464 30.224 ;
     RECT  62.592 28.103 63.96 30.224 ;
     RECT  64.992 30.085 105.624 30.224 ;
     RECT  106.704 29.363 144.888 30.224 ;
     RECT  145.968 28.103 146.136 30.224 ;
     RECT  147.216 29.317 147.384 30.224 ;
     RECT  148.368 30.085 148.632 30.224 ;
     RECT  148.368 30.224 148.392 30.227 ;
     RECT  89.88 0.016 90.864 0.132 ;
     RECT  91.128 0.016 92.112 0.132 ;
     RECT  130.392 0.016 131.376 0.132 ;
     RECT  90.984 0.131 91.008 0.132 ;
     RECT  89.832 0.132 90.912 1.187 ;
     RECT  90.936 0.132 92.16 1.187 ;
     RECT  130.344 0.132 131.424 0.611 ;
     RECT  130.344 0.611 131.568 2.245 ;
     RECT  91.5 1.187 92.16 2.137 ;
     RECT  92.904 1.859 94.2 2.291 ;
     RECT  94.776 1.859 96.192 2.099 ;
     RECT  151.608 1.859 152.592 2.915 ;
     RECT  106.008 2.003 106.992 2.243 ;
     RECT  153.912 2.099 154.896 2.915 ;
     RECT  106.008 2.243 107.52 2.291 ;
     RECT  130.344 2.245 131.328 2.485 ;
     RECT  149.88 2.291 150.9 3.107 ;
     RECT  109.176 2.723 110.256 2.915 ;
     RECT  127.608 2.867 128.592 3.107 ;
     RECT  170.76 2.867 171.744 3.443 ;
     RECT  100.248 2.915 101.376 3.107 ;
     RECT  103.128 2.915 104.544 3.107 ;
     RECT  110.808 2.915 112.032 3.107 ;
     RECT  122.856 2.915 123.9 3.203 ;
     RECT  125.304 2.915 126.6 2.963 ;
     RECT  133.032 2.915 134.16 3.011 ;
     RECT  141.24 2.915 142.704 3.107 ;
     RECT  144.408 2.915 145.5 3.107 ;
     RECT  146.424 2.915 147.408 3.107 ;
     RECT  148.728 2.915 149.856 3.107 ;
     RECT  156.744 2.915 157.776 2.963 ;
     RECT  160.536 2.915 161.568 3.059 ;
     RECT  165.72 2.915 166.704 3.107 ;
     RECT  167.544 2.915 168.72 3.107 ;
     RECT  118.92 2.963 120.384 3.011 ;
     RECT  121.512 2.963 122.832 3.203 ;
     RECT  136.056 2.963 137.184 3.107 ;
     RECT  156.744 2.963 158.208 3.107 ;
     RECT  116.232 3.011 117.36 3.059 ;
     RECT  132.888 3.011 134.16 3.107 ;
     RECT  112.056 3.059 113.1 3.107 ;
     RECT  116.112 3.059 117.36 3.107 ;
     RECT  160.536 3.059 161.7 3.395 ;
     RECT  99.912 3.107 101.376 3.443 ;
     RECT  132.888 3.107 134.304 3.203 ;
     RECT  167.412 3.107 168.72 3.443 ;
     RECT  130.488 14.531 132 21.493 ;
     RECT  72.912 19.909 74.112 23.123 ;
     RECT  74.136 19.909 75.3 20.101 ;
     RECT  74.136 20.101 75.168 21.443 ;
     RECT  74.136 21.443 75.3 23.123 ;
     RECT  91.008 21.443 91.5 22.693 ;
     RECT  131.016 21.493 132 23.413 ;
     RECT  67.512 22.021 68.832 23.893 ;
     RECT  68.856 22.021 69.9 23.365 ;
     RECT  89.832 22.693 91.5 22.789 ;
     RECT  90.408 22.789 91.5 24.421 ;
     RECT  116.856 22.933 118.32 24.085 ;
     RECT  72.912 23.123 75.3 23.365 ;
     RECT  87.384 23.221 88.368 23.893 ;
     RECT  118.812 23.221 119.856 23.941 ;
     RECT  119.88 23.221 121.2 24.421 ;
     RECT  98.568 23.269 99.6 24.469 ;
     RECT  121.704 23.269 122.88 24.277 ;
     RECT  122.904 23.269 123.9 24.565 ;
     RECT  70.212 23.365 71.664 24.517 ;
     RECT  73.752 23.365 75.3 23.701 ;
     RECT  141.288 23.365 142.704 24.517 ;
     RECT  100.2 23.413 101.52 24.565 ;
     RECT  132.312 23.413 133.68 24.133 ;
     RECT  133.704 23.413 134.7 23.893 ;
     RECT  137.712 23.413 139.056 23.845 ;
     RECT  113.412 23.557 114.528 23.749 ;
     RECT  114.552 23.557 115.8 24.517 ;
     RECT  79.656 23.653 80.7 24.131 ;
     RECT  73.752 23.701 75.12 24.325 ;
     RECT  76.2 23.845 77.712 24.517 ;
     RECT  137.712 23.845 138.768 25.141 ;
     RECT  67.8 23.893 68.832 24.997 ;
     RECT  95.736 23.941 96.9 24.421 ;
     RECT  126.912 23.941 128.16 25.093 ;
     RECT  84.6 24.085 86.1 24.325 ;
     RECT  116.856 24.085 117.936 24.421 ;
     RECT  79.56 24.131 80.7 25.669 ;
     RECT  132.456 24.133 133.68 24.325 ;
     RECT  132.456 24.325 133.632 24.469 ;
     RECT  135.816 24.325 137.04 24.469 ;
     RECT  120.216 24.421 121.2 25.333 ;
     RECT  92.184 24.469 93.504 25.141 ;
     RECT  135.816 24.469 136.944 24.517 ;
     RECT  70.212 24.517 71.616 25.045 ;
     RECT  124.536 24.517 126 25.669 ;
     RECT  141.288 24.517 142.32 25.093 ;
     RECT  100.2 24.565 101.376 25.093 ;
     RECT  67.8 24.997 68.784 25.717 ;
     RECT  81.672 25.091 83.184 25.669 ;
     RECT  64.32 25.187 64.5 26.581 ;
     RECT  105.312 25.621 106.56 26.149 ;
     RECT  106.584 25.621 107.7 25.765 ;
     RECT  111.336 25.717 112.656 25.765 ;
     RECT  106.584 25.765 107.568 26.005 ;
     RECT  145.992 26.101 147.216 27.109 ;
     RECT  105.432 26.149 106.56 28.501 ;
     RECT  143.112 26.341 144.144 26.629 ;
     RECT  144.168 26.341 145.5 26.725 ;
     RECT  144.312 26.725 145.5 27.589 ;
     RECT  63.888 26.867 64.5 27.349 ;
     RECT  146.136 27.109 147.216 30.108 ;
     RECT  62.112 27.349 63.168 27.925 ;
     RECT  63.192 27.349 64.5 27.829 ;
     RECT  63.48 27.829 64.5 27.925 ;
     RECT  42.216 28.103 43.296 30.108 ;
     RECT  63.96 28.103 65.136 30.085 ;
     RECT  144.888 28.103 145.968 30.108 ;
     RECT  147.24 28.103 148.608 29.317 ;
     RECT  105.48 28.501 106.56 29.029 ;
     RECT  147.384 29.317 148.608 30.085 ;
     RECT  105.624 29.363 106.704 30.108 ;
     RECT  63.96 30.085 64.992 30.108 ;
     RECT  147.384 30.085 148.368 30.108 ;
     RECT  42.264 30.108 43.248 30.224 ;
     RECT  64.008 30.108 64.944 30.224 ;
     RECT  105.672 30.108 106.656 30.224 ;
     RECT  144.936 30.108 145.92 30.224 ;
     RECT  146.184 30.108 147.168 30.224 ;
     RECT  147.432 30.108 148.368 30.224 ;
  END
END dsfd_sstn_e0e1c0c1si
END LIBRARY
